VERSION 5.8 ;
BUSBITCHARS "[]" ;
DIVIDERCHAR "/" ;
UNITS
    DATABASE MICRONS 1000 ;
END UNITS

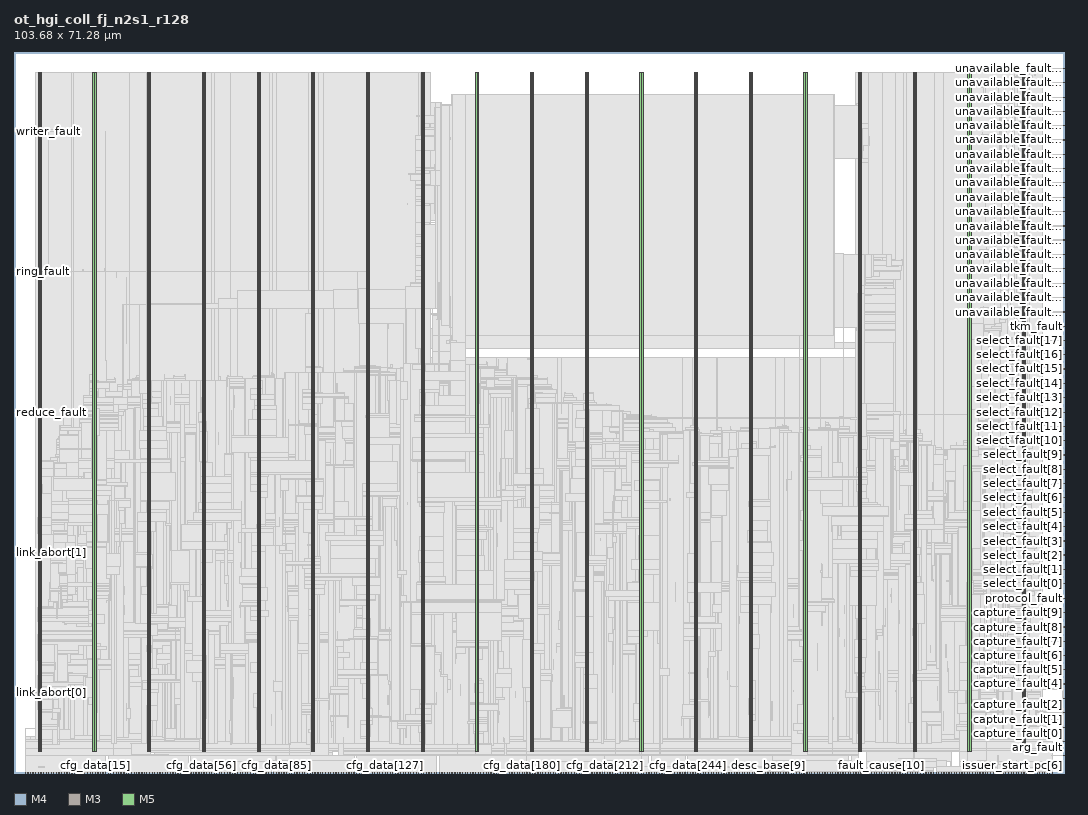
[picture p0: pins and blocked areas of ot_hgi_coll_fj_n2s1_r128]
MACRO ot_hgi_coll_fj_n2s1_r128
  FOREIGN ot_hgi_coll_fj_n2s1_r128 0 0 ;
  CLASS BLOCK ;
  SIZE 103.68 BY 71.28 ;
  PIN arg_fault
    DIRECTION INPUT ;
    USE SIGNAL ;
    PORT
      LAYER M4 ;
        RECT  103.596 1.68 103.68 1.704 ;
    END
  END arg_fault
  PIN capture_fault[0]
    DIRECTION INPUT ;
    USE SIGNAL ;
    PORT
      LAYER M4 ;
        RECT  103.596 3.12 103.68 3.144 ;
    END
  END capture_fault[0]
  PIN capture_fault[1]
    DIRECTION INPUT ;
    USE SIGNAL ;
    PORT
      LAYER M4 ;
        RECT  103.596 4.512 103.68 4.536 ;
    END
  END capture_fault[1]
  PIN capture_fault[2]
    DIRECTION INPUT ;
    USE SIGNAL ;
    PORT
      LAYER M4 ;
        RECT  103.596 5.952 103.68 5.976 ;
    END
  END capture_fault[2]
  PIN capture_fault[3]
    DIRECTION INPUT ;
    USE SIGNAL ;
    PORT
      LAYER M4 ;
        RECT  103.596 7.344 103.68 7.368 ;
    END
  END capture_fault[3]
  PIN capture_fault[4]
    DIRECTION INPUT ;
    USE SIGNAL ;
    PORT
      LAYER M4 ;
        RECT  103.596 8.784 103.68 8.808 ;
    END
  END capture_fault[4]
  PIN capture_fault[5]
    DIRECTION INPUT ;
    USE SIGNAL ;
    PORT
      LAYER M4 ;
        RECT  103.596 10.176 103.68 10.2 ;
    END
  END capture_fault[5]
  PIN capture_fault[6]
    DIRECTION INPUT ;
    USE SIGNAL ;
    PORT
      LAYER M4 ;
        RECT  103.596 11.616 103.68 11.64 ;
    END
  END capture_fault[6]
  PIN capture_fault[7]
    DIRECTION INPUT ;
    USE SIGNAL ;
    PORT
      LAYER M4 ;
        RECT  103.596 13.008 103.68 13.032 ;
    END
  END capture_fault[7]
  PIN capture_fault[8]
    DIRECTION INPUT ;
    USE SIGNAL ;
    PORT
      LAYER M4 ;
        RECT  103.596 14.4 103.68 14.424 ;
    END
  END capture_fault[8]
  PIN capture_fault[9]
    DIRECTION INPUT ;
    USE SIGNAL ;
    PORT
      LAYER M4 ;
        RECT  103.596 15.84 103.68 15.864 ;
    END
  END capture_fault[9]
  PIN cfg_addr[0]
    DIRECTION INPUT ;
    USE SIGNAL ;
    PORT
      LAYER M3 ;
        RECT  1.116 0 1.134 0.038 ;
    END
  END cfg_addr[0]
  PIN cfg_addr[10]
    DIRECTION INPUT ;
    USE SIGNAL ;
    PORT
      LAYER M3 ;
        RECT  3.672 0 3.69 0.038 ;
    END
  END cfg_addr[10]
  PIN cfg_addr[11]
    DIRECTION INPUT ;
    USE SIGNAL ;
    PORT
      LAYER M3 ;
        RECT  3.924 0 3.942 0.038 ;
    END
  END cfg_addr[11]
  PIN cfg_addr[1]
    DIRECTION INPUT ;
    USE SIGNAL ;
    PORT
      LAYER M3 ;
        RECT  1.368 0 1.386 0.038 ;
    END
  END cfg_addr[1]
  PIN cfg_addr[2]
    DIRECTION INPUT ;
    USE SIGNAL ;
    PORT
      LAYER M3 ;
        RECT  1.62 0 1.638 0.038 ;
    END
  END cfg_addr[2]
  PIN cfg_addr[3]
    DIRECTION INPUT ;
    USE SIGNAL ;
    PORT
      LAYER M3 ;
        RECT  1.872 0 1.89 0.038 ;
    END
  END cfg_addr[3]
  PIN cfg_addr[4]
    DIRECTION INPUT ;
    USE SIGNAL ;
    PORT
      LAYER M3 ;
        RECT  2.124 0 2.142 0.038 ;
    END
  END cfg_addr[4]
  PIN cfg_addr[5]
    DIRECTION INPUT ;
    USE SIGNAL ;
    PORT
      LAYER M3 ;
        RECT  2.412 0 2.43 0.038 ;
    END
  END cfg_addr[5]
  PIN cfg_addr[6]
    DIRECTION INPUT ;
    USE SIGNAL ;
    PORT
      LAYER M3 ;
        RECT  2.664 0 2.682 0.038 ;
    END
  END cfg_addr[6]
  PIN cfg_addr[7]
    DIRECTION INPUT ;
    USE SIGNAL ;
    PORT
      LAYER M3 ;
        RECT  2.916 0 2.934 0.038 ;
    END
  END cfg_addr[7]
  PIN cfg_addr[8]
    DIRECTION INPUT ;
    USE SIGNAL ;
    PORT
      LAYER M3 ;
        RECT  3.168 0 3.186 0.038 ;
    END
  END cfg_addr[8]
  PIN cfg_addr[9]
    DIRECTION INPUT ;
    USE SIGNAL ;
    PORT
      LAYER M3 ;
        RECT  3.42 0 3.438 0.038 ;
    END
  END cfg_addr[9]
  PIN cfg_data[0]
    DIRECTION INPUT ;
    USE SIGNAL ;
    PORT
      LAYER M3 ;
        RECT  4.176 0 4.194 0.038 ;
    END
  END cfg_data[0]
  PIN cfg_data[100]
    DIRECTION INPUT ;
    USE SIGNAL ;
    PORT
      LAYER M5 ;
        RECT  29.712 0 29.736 0.084 ;
    END
  END cfg_data[100]
  PIN cfg_data[101]
    DIRECTION INPUT ;
    USE SIGNAL ;
    PORT
      LAYER M5 ;
        RECT  30 0 30.024 0.084 ;
    END
  END cfg_data[101]
  PIN cfg_data[102]
    DIRECTION INPUT ;
    USE SIGNAL ;
    PORT
      LAYER M5 ;
        RECT  30.24 0 30.264 0.084 ;
    END
  END cfg_data[102]
  PIN cfg_data[103]
    DIRECTION INPUT ;
    USE SIGNAL ;
    PORT
      LAYER M5 ;
        RECT  30.48 0 30.504 0.084 ;
    END
  END cfg_data[103]
  PIN cfg_data[104]
    DIRECTION INPUT ;
    USE SIGNAL ;
    PORT
      LAYER M5 ;
        RECT  30.768 0 30.792 0.084 ;
    END
  END cfg_data[104]
  PIN cfg_data[105]
    DIRECTION INPUT ;
    USE SIGNAL ;
    PORT
      LAYER M5 ;
        RECT  31.008 0 31.032 0.084 ;
    END
  END cfg_data[105]
  PIN cfg_data[106]
    DIRECTION INPUT ;
    USE SIGNAL ;
    PORT
      LAYER M5 ;
        RECT  31.248 0 31.272 0.084 ;
    END
  END cfg_data[106]
  PIN cfg_data[107]
    DIRECTION INPUT ;
    USE SIGNAL ;
    PORT
      LAYER M5 ;
        RECT  31.536 0 31.56 0.084 ;
    END
  END cfg_data[107]
  PIN cfg_data[108]
    DIRECTION INPUT ;
    USE SIGNAL ;
    PORT
      LAYER M5 ;
        RECT  31.776 0 31.8 0.084 ;
    END
  END cfg_data[108]
  PIN cfg_data[109]
    DIRECTION INPUT ;
    USE SIGNAL ;
    PORT
      LAYER M5 ;
        RECT  32.016 0 32.04 0.084 ;
    END
  END cfg_data[109]
  PIN cfg_data[10]
    DIRECTION INPUT ;
    USE SIGNAL ;
    PORT
      LAYER M3 ;
        RECT  6.732 0 6.75 0.038 ;
    END
  END cfg_data[10]
  PIN cfg_data[110]
    DIRECTION INPUT ;
    USE SIGNAL ;
    PORT
      LAYER M5 ;
        RECT  32.304 0 32.328 0.084 ;
    END
  END cfg_data[110]
  PIN cfg_data[111]
    DIRECTION INPUT ;
    USE SIGNAL ;
    PORT
      LAYER M5 ;
        RECT  32.544 0 32.568 0.084 ;
    END
  END cfg_data[111]
  PIN cfg_data[112]
    DIRECTION INPUT ;
    USE SIGNAL ;
    PORT
      LAYER M5 ;
        RECT  32.784 0 32.808 0.084 ;
    END
  END cfg_data[112]
  PIN cfg_data[113]
    DIRECTION INPUT ;
    USE SIGNAL ;
    PORT
      LAYER M5 ;
        RECT  33.072 0 33.096 0.084 ;
    END
  END cfg_data[113]
  PIN cfg_data[114]
    DIRECTION INPUT ;
    USE SIGNAL ;
    PORT
      LAYER M5 ;
        RECT  33.312 0 33.336 0.084 ;
    END
  END cfg_data[114]
  PIN cfg_data[115]
    DIRECTION INPUT ;
    USE SIGNAL ;
    PORT
      LAYER M5 ;
        RECT  33.552 0 33.576 0.084 ;
    END
  END cfg_data[115]
  PIN cfg_data[116]
    DIRECTION INPUT ;
    USE SIGNAL ;
    PORT
      LAYER M3 ;
        RECT  33.804 0 33.822 0.038 ;
    END
  END cfg_data[116]
  PIN cfg_data[117]
    DIRECTION INPUT ;
    USE SIGNAL ;
    PORT
      LAYER M3 ;
        RECT  34.092 0 34.11 0.038 ;
    END
  END cfg_data[117]
  PIN cfg_data[118]
    DIRECTION INPUT ;
    USE SIGNAL ;
    PORT
      LAYER M3 ;
        RECT  34.344 0 34.362 0.038 ;
    END
  END cfg_data[118]
  PIN cfg_data[119]
    DIRECTION INPUT ;
    USE SIGNAL ;
    PORT
      LAYER M3 ;
        RECT  34.596 0 34.614 0.038 ;
    END
  END cfg_data[119]
  PIN cfg_data[11]
    DIRECTION INPUT ;
    USE SIGNAL ;
    PORT
      LAYER M3 ;
        RECT  6.984 0 7.002 0.038 ;
    END
  END cfg_data[11]
  PIN cfg_data[120]
    DIRECTION INPUT ;
    USE SIGNAL ;
    PORT
      LAYER M3 ;
        RECT  34.848 0 34.866 0.038 ;
    END
  END cfg_data[120]
  PIN cfg_data[121]
    DIRECTION INPUT ;
    USE SIGNAL ;
    PORT
      LAYER M3 ;
        RECT  35.1 0 35.118 0.038 ;
    END
  END cfg_data[121]
  PIN cfg_data[122]
    DIRECTION INPUT ;
    USE SIGNAL ;
    PORT
      LAYER M3 ;
        RECT  35.352 0 35.37 0.038 ;
    END
  END cfg_data[122]
  PIN cfg_data[123]
    DIRECTION INPUT ;
    USE SIGNAL ;
    PORT
      LAYER M3 ;
        RECT  35.604 0 35.622 0.038 ;
    END
  END cfg_data[123]
  PIN cfg_data[124]
    DIRECTION INPUT ;
    USE SIGNAL ;
    PORT
      LAYER M3 ;
        RECT  35.856 0 35.874 0.038 ;
    END
  END cfg_data[124]
  PIN cfg_data[125]
    DIRECTION INPUT ;
    USE SIGNAL ;
    PORT
      LAYER M3 ;
        RECT  36.108 0 36.126 0.038 ;
    END
  END cfg_data[125]
  PIN cfg_data[126]
    DIRECTION INPUT ;
    USE SIGNAL ;
    PORT
      LAYER M3 ;
        RECT  36.36 0 36.378 0.038 ;
    END
  END cfg_data[126]
  PIN cfg_data[127]
    DIRECTION INPUT ;
    USE SIGNAL ;
    PORT
      LAYER M3 ;
        RECT  36.648 0 36.666 0.038 ;
    END
  END cfg_data[127]
  PIN cfg_data[128]
    DIRECTION INPUT ;
    USE SIGNAL ;
    PORT
      LAYER M3 ;
        RECT  36.9 0 36.918 0.038 ;
    END
  END cfg_data[128]
  PIN cfg_data[129]
    DIRECTION INPUT ;
    USE SIGNAL ;
    PORT
      LAYER M3 ;
        RECT  37.152 0 37.17 0.038 ;
    END
  END cfg_data[129]
  PIN cfg_data[12]
    DIRECTION INPUT ;
    USE SIGNAL ;
    PORT
      LAYER M3 ;
        RECT  7.236 0 7.254 0.038 ;
    END
  END cfg_data[12]
  PIN cfg_data[130]
    DIRECTION INPUT ;
    USE SIGNAL ;
    PORT
      LAYER M3 ;
        RECT  37.404 0 37.422 0.038 ;
    END
  END cfg_data[130]
  PIN cfg_data[131]
    DIRECTION INPUT ;
    USE SIGNAL ;
    PORT
      LAYER M3 ;
        RECT  37.656 0 37.674 0.038 ;
    END
  END cfg_data[131]
  PIN cfg_data[132]
    DIRECTION INPUT ;
    USE SIGNAL ;
    PORT
      LAYER M3 ;
        RECT  37.908 0 37.926 0.038 ;
    END
  END cfg_data[132]
  PIN cfg_data[133]
    DIRECTION INPUT ;
    USE SIGNAL ;
    PORT
      LAYER M3 ;
        RECT  38.16 0 38.178 0.038 ;
    END
  END cfg_data[133]
  PIN cfg_data[134]
    DIRECTION INPUT ;
    USE SIGNAL ;
    PORT
      LAYER M3 ;
        RECT  38.412 0 38.43 0.038 ;
    END
  END cfg_data[134]
  PIN cfg_data[135]
    DIRECTION INPUT ;
    USE SIGNAL ;
    PORT
      LAYER M3 ;
        RECT  38.664 0 38.682 0.038 ;
    END
  END cfg_data[135]
  PIN cfg_data[136]
    DIRECTION INPUT ;
    USE SIGNAL ;
    PORT
      LAYER M3 ;
        RECT  38.916 0 38.934 0.038 ;
    END
  END cfg_data[136]
  PIN cfg_data[137]
    DIRECTION INPUT ;
    USE SIGNAL ;
    PORT
      LAYER M3 ;
        RECT  39.168 0 39.186 0.038 ;
    END
  END cfg_data[137]
  PIN cfg_data[138]
    DIRECTION INPUT ;
    USE SIGNAL ;
    PORT
      LAYER M3 ;
        RECT  39.456 0 39.474 0.038 ;
    END
  END cfg_data[138]
  PIN cfg_data[139]
    DIRECTION INPUT ;
    USE SIGNAL ;
    PORT
      LAYER M3 ;
        RECT  39.708 0 39.726 0.038 ;
    END
  END cfg_data[139]
  PIN cfg_data[13]
    DIRECTION INPUT ;
    USE SIGNAL ;
    PORT
      LAYER M3 ;
        RECT  7.524 0 7.542 0.038 ;
    END
  END cfg_data[13]
  PIN cfg_data[140]
    DIRECTION INPUT ;
    USE SIGNAL ;
    PORT
      LAYER M3 ;
        RECT  39.96 0 39.978 0.038 ;
    END
  END cfg_data[140]
  PIN cfg_data[141]
    DIRECTION INPUT ;
    USE SIGNAL ;
    PORT
      LAYER M3 ;
        RECT  40.212 0 40.23 0.038 ;
    END
  END cfg_data[141]
  PIN cfg_data[142]
    DIRECTION INPUT ;
    USE SIGNAL ;
    PORT
      LAYER M3 ;
        RECT  40.464 0 40.482 0.038 ;
    END
  END cfg_data[142]
  PIN cfg_data[143]
    DIRECTION INPUT ;
    USE SIGNAL ;
    PORT
      LAYER M3 ;
        RECT  40.716 0 40.734 0.038 ;
    END
  END cfg_data[143]
  PIN cfg_data[144]
    DIRECTION INPUT ;
    USE SIGNAL ;
    PORT
      LAYER M3 ;
        RECT  40.968 0 40.986 0.038 ;
    END
  END cfg_data[144]
  PIN cfg_data[145]
    DIRECTION INPUT ;
    USE SIGNAL ;
    PORT
      LAYER M3 ;
        RECT  41.22 0 41.238 0.038 ;
    END
  END cfg_data[145]
  PIN cfg_data[146]
    DIRECTION INPUT ;
    USE SIGNAL ;
    PORT
      LAYER M3 ;
        RECT  41.472 0 41.49 0.038 ;
    END
  END cfg_data[146]
  PIN cfg_data[147]
    DIRECTION INPUT ;
    USE SIGNAL ;
    PORT
      LAYER M3 ;
        RECT  41.724 0 41.742 0.038 ;
    END
  END cfg_data[147]
  PIN cfg_data[148]
    DIRECTION INPUT ;
    USE SIGNAL ;
    PORT
      LAYER M5 ;
        RECT  42 0 42.024 0.084 ;
    END
  END cfg_data[148]
  PIN cfg_data[149]
    DIRECTION INPUT ;
    USE SIGNAL ;
    PORT
      LAYER M5 ;
        RECT  42.24 0 42.264 0.084 ;
    END
  END cfg_data[149]
  PIN cfg_data[14]
    DIRECTION INPUT ;
    USE SIGNAL ;
    PORT
      LAYER M3 ;
        RECT  7.776 0 7.794 0.038 ;
    END
  END cfg_data[14]
  PIN cfg_data[150]
    DIRECTION INPUT ;
    USE SIGNAL ;
    PORT
      LAYER M5 ;
        RECT  42.48 0 42.504 0.084 ;
    END
  END cfg_data[150]
  PIN cfg_data[151]
    DIRECTION INPUT ;
    USE SIGNAL ;
    PORT
      LAYER M5 ;
        RECT  42.768 0 42.792 0.084 ;
    END
  END cfg_data[151]
  PIN cfg_data[152]
    DIRECTION INPUT ;
    USE SIGNAL ;
    PORT
      LAYER M5 ;
        RECT  43.008 0 43.032 0.084 ;
    END
  END cfg_data[152]
  PIN cfg_data[153]
    DIRECTION INPUT ;
    USE SIGNAL ;
    PORT
      LAYER M5 ;
        RECT  43.248 0 43.272 0.084 ;
    END
  END cfg_data[153]
  PIN cfg_data[154]
    DIRECTION INPUT ;
    USE SIGNAL ;
    PORT
      LAYER M5 ;
        RECT  43.536 0 43.56 0.084 ;
    END
  END cfg_data[154]
  PIN cfg_data[155]
    DIRECTION INPUT ;
    USE SIGNAL ;
    PORT
      LAYER M5 ;
        RECT  43.776 0 43.8 0.084 ;
    END
  END cfg_data[155]
  PIN cfg_data[156]
    DIRECTION INPUT ;
    USE SIGNAL ;
    PORT
      LAYER M5 ;
        RECT  44.016 0 44.04 0.084 ;
    END
  END cfg_data[156]
  PIN cfg_data[157]
    DIRECTION INPUT ;
    USE SIGNAL ;
    PORT
      LAYER M5 ;
        RECT  44.304 0 44.328 0.084 ;
    END
  END cfg_data[157]
  PIN cfg_data[158]
    DIRECTION INPUT ;
    USE SIGNAL ;
    PORT
      LAYER M5 ;
        RECT  44.544 0 44.568 0.084 ;
    END
  END cfg_data[158]
  PIN cfg_data[159]
    DIRECTION INPUT ;
    USE SIGNAL ;
    PORT
      LAYER M5 ;
        RECT  44.784 0 44.808 0.084 ;
    END
  END cfg_data[159]
  PIN cfg_data[15]
    DIRECTION INPUT ;
    USE SIGNAL ;
    PORT
      LAYER M3 ;
        RECT  8.028 0 8.046 0.038 ;
    END
  END cfg_data[15]
  PIN cfg_data[160]
    DIRECTION INPUT ;
    USE SIGNAL ;
    PORT
      LAYER M5 ;
        RECT  45.072 0 45.096 0.084 ;
    END
  END cfg_data[160]
  PIN cfg_data[161]
    DIRECTION INPUT ;
    USE SIGNAL ;
    PORT
      LAYER M5 ;
        RECT  45.312 0 45.336 0.084 ;
    END
  END cfg_data[161]
  PIN cfg_data[162]
    DIRECTION INPUT ;
    USE SIGNAL ;
    PORT
      LAYER M5 ;
        RECT  45.552 0 45.576 0.084 ;
    END
  END cfg_data[162]
  PIN cfg_data[163]
    DIRECTION INPUT ;
    USE SIGNAL ;
    PORT
      LAYER M5 ;
        RECT  45.84 0 45.864 0.084 ;
    END
  END cfg_data[163]
  PIN cfg_data[164]
    DIRECTION INPUT ;
    USE SIGNAL ;
    PORT
      LAYER M5 ;
        RECT  46.08 0 46.104 0.084 ;
    END
  END cfg_data[164]
  PIN cfg_data[165]
    DIRECTION INPUT ;
    USE SIGNAL ;
    PORT
      LAYER M5 ;
        RECT  46.32 0 46.344 0.084 ;
    END
  END cfg_data[165]
  PIN cfg_data[166]
    DIRECTION INPUT ;
    USE SIGNAL ;
    PORT
      LAYER M5 ;
        RECT  46.608 0 46.632 0.084 ;
    END
  END cfg_data[166]
  PIN cfg_data[167]
    DIRECTION INPUT ;
    USE SIGNAL ;
    PORT
      LAYER M5 ;
        RECT  46.848 0 46.872 0.084 ;
    END
  END cfg_data[167]
  PIN cfg_data[168]
    DIRECTION INPUT ;
    USE SIGNAL ;
    PORT
      LAYER M5 ;
        RECT  47.088 0 47.112 0.084 ;
    END
  END cfg_data[168]
  PIN cfg_data[169]
    DIRECTION INPUT ;
    USE SIGNAL ;
    PORT
      LAYER M5 ;
        RECT  47.376 0 47.4 0.084 ;
    END
  END cfg_data[169]
  PIN cfg_data[16]
    DIRECTION INPUT ;
    USE SIGNAL ;
    PORT
      LAYER M3 ;
        RECT  8.28 0 8.298 0.038 ;
    END
  END cfg_data[16]
  PIN cfg_data[170]
    DIRECTION INPUT ;
    USE SIGNAL ;
    PORT
      LAYER M5 ;
        RECT  47.616 0 47.64 0.084 ;
    END
  END cfg_data[170]
  PIN cfg_data[171]
    DIRECTION INPUT ;
    USE SIGNAL ;
    PORT
      LAYER M5 ;
        RECT  47.856 0 47.88 0.084 ;
    END
  END cfg_data[171]
  PIN cfg_data[172]
    DIRECTION INPUT ;
    USE SIGNAL ;
    PORT
      LAYER M5 ;
        RECT  48.144 0 48.168 0.084 ;
    END
  END cfg_data[172]
  PIN cfg_data[173]
    DIRECTION INPUT ;
    USE SIGNAL ;
    PORT
      LAYER M5 ;
        RECT  48.384 0 48.408 0.084 ;
    END
  END cfg_data[173]
  PIN cfg_data[174]
    DIRECTION INPUT ;
    USE SIGNAL ;
    PORT
      LAYER M5 ;
        RECT  48.624 0 48.648 0.084 ;
    END
  END cfg_data[174]
  PIN cfg_data[175]
    DIRECTION INPUT ;
    USE SIGNAL ;
    PORT
      LAYER M5 ;
        RECT  48.912 0 48.936 0.084 ;
    END
  END cfg_data[175]
  PIN cfg_data[176]
    DIRECTION INPUT ;
    USE SIGNAL ;
    PORT
      LAYER M5 ;
        RECT  49.152 0 49.176 0.084 ;
    END
  END cfg_data[176]
  PIN cfg_data[177]
    DIRECTION INPUT ;
    USE SIGNAL ;
    PORT
      LAYER M5 ;
        RECT  49.392 0 49.416 0.084 ;
    END
  END cfg_data[177]
  PIN cfg_data[178]
    DIRECTION INPUT ;
    USE SIGNAL ;
    PORT
      LAYER M5 ;
        RECT  49.68 0 49.704 0.084 ;
    END
  END cfg_data[178]
  PIN cfg_data[179]
    DIRECTION INPUT ;
    USE SIGNAL ;
    PORT
      LAYER M5 ;
        RECT  49.92 0 49.944 0.084 ;
    END
  END cfg_data[179]
  PIN cfg_data[17]
    DIRECTION INPUT ;
    USE SIGNAL ;
    PORT
      LAYER M3 ;
        RECT  8.532 0 8.55 0.038 ;
    END
  END cfg_data[17]
  PIN cfg_data[180]
    DIRECTION INPUT ;
    USE SIGNAL ;
    PORT
      LAYER M3 ;
        RECT  50.184 0 50.202 0.038 ;
    END
  END cfg_data[180]
  PIN cfg_data[181]
    DIRECTION INPUT ;
    USE SIGNAL ;
    PORT
      LAYER M3 ;
        RECT  50.436 0 50.454 0.038 ;
    END
  END cfg_data[181]
  PIN cfg_data[182]
    DIRECTION INPUT ;
    USE SIGNAL ;
    PORT
      LAYER M3 ;
        RECT  50.688 0 50.706 0.038 ;
    END
  END cfg_data[182]
  PIN cfg_data[183]
    DIRECTION INPUT ;
    USE SIGNAL ;
    PORT
      LAYER M3 ;
        RECT  50.94 0 50.958 0.038 ;
    END
  END cfg_data[183]
  PIN cfg_data[184]
    DIRECTION INPUT ;
    USE SIGNAL ;
    PORT
      LAYER M3 ;
        RECT  51.192 0 51.21 0.038 ;
    END
  END cfg_data[184]
  PIN cfg_data[185]
    DIRECTION INPUT ;
    USE SIGNAL ;
    PORT
      LAYER M3 ;
        RECT  51.444 0 51.462 0.038 ;
    END
  END cfg_data[185]
  PIN cfg_data[186]
    DIRECTION INPUT ;
    USE SIGNAL ;
    PORT
      LAYER M3 ;
        RECT  51.696 0 51.714 0.038 ;
    END
  END cfg_data[186]
  PIN cfg_data[187]
    DIRECTION INPUT ;
    USE SIGNAL ;
    PORT
      LAYER M3 ;
        RECT  51.948 0 51.966 0.038 ;
    END
  END cfg_data[187]
  PIN cfg_data[188]
    DIRECTION INPUT ;
    USE SIGNAL ;
    PORT
      LAYER M3 ;
        RECT  52.2 0 52.218 0.038 ;
    END
  END cfg_data[188]
  PIN cfg_data[189]
    DIRECTION INPUT ;
    USE SIGNAL ;
    PORT
      LAYER M3 ;
        RECT  52.488 0 52.506 0.038 ;
    END
  END cfg_data[189]
  PIN cfg_data[18]
    DIRECTION INPUT ;
    USE SIGNAL ;
    PORT
      LAYER M3 ;
        RECT  8.784 0 8.802 0.038 ;
    END
  END cfg_data[18]
  PIN cfg_data[190]
    DIRECTION INPUT ;
    USE SIGNAL ;
    PORT
      LAYER M3 ;
        RECT  52.74 0 52.758 0.038 ;
    END
  END cfg_data[190]
  PIN cfg_data[191]
    DIRECTION INPUT ;
    USE SIGNAL ;
    PORT
      LAYER M3 ;
        RECT  52.992 0 53.01 0.038 ;
    END
  END cfg_data[191]
  PIN cfg_data[192]
    DIRECTION INPUT ;
    USE SIGNAL ;
    PORT
      LAYER M3 ;
        RECT  53.244 0 53.262 0.038 ;
    END
  END cfg_data[192]
  PIN cfg_data[193]
    DIRECTION INPUT ;
    USE SIGNAL ;
    PORT
      LAYER M3 ;
        RECT  53.496 0 53.514 0.038 ;
    END
  END cfg_data[193]
  PIN cfg_data[194]
    DIRECTION INPUT ;
    USE SIGNAL ;
    PORT
      LAYER M3 ;
        RECT  53.748 0 53.766 0.038 ;
    END
  END cfg_data[194]
  PIN cfg_data[195]
    DIRECTION INPUT ;
    USE SIGNAL ;
    PORT
      LAYER M3 ;
        RECT  54 0 54.018 0.038 ;
    END
  END cfg_data[195]
  PIN cfg_data[196]
    DIRECTION INPUT ;
    USE SIGNAL ;
    PORT
      LAYER M3 ;
        RECT  54.252 0 54.27 0.038 ;
    END
  END cfg_data[196]
  PIN cfg_data[197]
    DIRECTION INPUT ;
    USE SIGNAL ;
    PORT
      LAYER M3 ;
        RECT  54.504 0 54.522 0.038 ;
    END
  END cfg_data[197]
  PIN cfg_data[198]
    DIRECTION INPUT ;
    USE SIGNAL ;
    PORT
      LAYER M3 ;
        RECT  54.756 0 54.774 0.038 ;
    END
  END cfg_data[198]
  PIN cfg_data[199]
    DIRECTION INPUT ;
    USE SIGNAL ;
    PORT
      LAYER M3 ;
        RECT  55.008 0 55.026 0.038 ;
    END
  END cfg_data[199]
  PIN cfg_data[19]
    DIRECTION INPUT ;
    USE SIGNAL ;
    PORT
      LAYER M3 ;
        RECT  9.036 0 9.054 0.038 ;
    END
  END cfg_data[19]
  PIN cfg_data[1]
    DIRECTION INPUT ;
    USE SIGNAL ;
    PORT
      LAYER M3 ;
        RECT  4.428 0 4.446 0.038 ;
    END
  END cfg_data[1]
  PIN cfg_data[200]
    DIRECTION INPUT ;
    USE SIGNAL ;
    PORT
      LAYER M3 ;
        RECT  55.296 0 55.314 0.038 ;
    END
  END cfg_data[200]
  PIN cfg_data[201]
    DIRECTION INPUT ;
    USE SIGNAL ;
    PORT
      LAYER M3 ;
        RECT  55.548 0 55.566 0.038 ;
    END
  END cfg_data[201]
  PIN cfg_data[202]
    DIRECTION INPUT ;
    USE SIGNAL ;
    PORT
      LAYER M3 ;
        RECT  55.8 0 55.818 0.038 ;
    END
  END cfg_data[202]
  PIN cfg_data[203]
    DIRECTION INPUT ;
    USE SIGNAL ;
    PORT
      LAYER M3 ;
        RECT  56.052 0 56.07 0.038 ;
    END
  END cfg_data[203]
  PIN cfg_data[204]
    DIRECTION INPUT ;
    USE SIGNAL ;
    PORT
      LAYER M3 ;
        RECT  56.304 0 56.322 0.038 ;
    END
  END cfg_data[204]
  PIN cfg_data[205]
    DIRECTION INPUT ;
    USE SIGNAL ;
    PORT
      LAYER M3 ;
        RECT  56.556 0 56.574 0.038 ;
    END
  END cfg_data[205]
  PIN cfg_data[206]
    DIRECTION INPUT ;
    USE SIGNAL ;
    PORT
      LAYER M3 ;
        RECT  56.808 0 56.826 0.038 ;
    END
  END cfg_data[206]
  PIN cfg_data[207]
    DIRECTION INPUT ;
    USE SIGNAL ;
    PORT
      LAYER M3 ;
        RECT  57.06 0 57.078 0.038 ;
    END
  END cfg_data[207]
  PIN cfg_data[208]
    DIRECTION INPUT ;
    USE SIGNAL ;
    PORT
      LAYER M3 ;
        RECT  57.312 0 57.33 0.038 ;
    END
  END cfg_data[208]
  PIN cfg_data[209]
    DIRECTION INPUT ;
    USE SIGNAL ;
    PORT
      LAYER M3 ;
        RECT  57.564 0 57.582 0.038 ;
    END
  END cfg_data[209]
  PIN cfg_data[20]
    DIRECTION INPUT ;
    USE SIGNAL ;
    PORT
      LAYER M5 ;
        RECT  9.312 0 9.336 0.084 ;
    END
  END cfg_data[20]
  PIN cfg_data[210]
    DIRECTION INPUT ;
    USE SIGNAL ;
    PORT
      LAYER M3 ;
        RECT  57.852 0 57.87 0.038 ;
    END
  END cfg_data[210]
  PIN cfg_data[211]
    DIRECTION INPUT ;
    USE SIGNAL ;
    PORT
      LAYER M3 ;
        RECT  58.104 0 58.122 0.038 ;
    END
  END cfg_data[211]
  PIN cfg_data[212]
    DIRECTION INPUT ;
    USE SIGNAL ;
    PORT
      LAYER M5 ;
        RECT  58.32 0 58.344 0.084 ;
    END
  END cfg_data[212]
  PIN cfg_data[213]
    DIRECTION INPUT ;
    USE SIGNAL ;
    PORT
      LAYER M5 ;
        RECT  58.608 0 58.632 0.084 ;
    END
  END cfg_data[213]
  PIN cfg_data[214]
    DIRECTION INPUT ;
    USE SIGNAL ;
    PORT
      LAYER M5 ;
        RECT  58.848 0 58.872 0.084 ;
    END
  END cfg_data[214]
  PIN cfg_data[215]
    DIRECTION INPUT ;
    USE SIGNAL ;
    PORT
      LAYER M5 ;
        RECT  59.088 0 59.112 0.084 ;
    END
  END cfg_data[215]
  PIN cfg_data[216]
    DIRECTION INPUT ;
    USE SIGNAL ;
    PORT
      LAYER M5 ;
        RECT  59.376 0 59.4 0.084 ;
    END
  END cfg_data[216]
  PIN cfg_data[217]
    DIRECTION INPUT ;
    USE SIGNAL ;
    PORT
      LAYER M5 ;
        RECT  59.616 0 59.64 0.084 ;
    END
  END cfg_data[217]
  PIN cfg_data[218]
    DIRECTION INPUT ;
    USE SIGNAL ;
    PORT
      LAYER M5 ;
        RECT  59.856 0 59.88 0.084 ;
    END
  END cfg_data[218]
  PIN cfg_data[219]
    DIRECTION INPUT ;
    USE SIGNAL ;
    PORT
      LAYER M5 ;
        RECT  60.144 0 60.168 0.084 ;
    END
  END cfg_data[219]
  PIN cfg_data[21]
    DIRECTION INPUT ;
    USE SIGNAL ;
    PORT
      LAYER M5 ;
        RECT  9.552 0 9.576 0.084 ;
    END
  END cfg_data[21]
  PIN cfg_data[220]
    DIRECTION INPUT ;
    USE SIGNAL ;
    PORT
      LAYER M5 ;
        RECT  60.384 0 60.408 0.084 ;
    END
  END cfg_data[220]
  PIN cfg_data[221]
    DIRECTION INPUT ;
    USE SIGNAL ;
    PORT
      LAYER M5 ;
        RECT  60.624 0 60.648 0.084 ;
    END
  END cfg_data[221]
  PIN cfg_data[222]
    DIRECTION INPUT ;
    USE SIGNAL ;
    PORT
      LAYER M5 ;
        RECT  60.912 0 60.936 0.084 ;
    END
  END cfg_data[222]
  PIN cfg_data[223]
    DIRECTION INPUT ;
    USE SIGNAL ;
    PORT
      LAYER M5 ;
        RECT  61.152 0 61.176 0.084 ;
    END
  END cfg_data[223]
  PIN cfg_data[224]
    DIRECTION INPUT ;
    USE SIGNAL ;
    PORT
      LAYER M5 ;
        RECT  61.392 0 61.416 0.084 ;
    END
  END cfg_data[224]
  PIN cfg_data[225]
    DIRECTION INPUT ;
    USE SIGNAL ;
    PORT
      LAYER M5 ;
        RECT  61.68 0 61.704 0.084 ;
    END
  END cfg_data[225]
  PIN cfg_data[226]
    DIRECTION INPUT ;
    USE SIGNAL ;
    PORT
      LAYER M5 ;
        RECT  61.92 0 61.944 0.084 ;
    END
  END cfg_data[226]
  PIN cfg_data[227]
    DIRECTION INPUT ;
    USE SIGNAL ;
    PORT
      LAYER M5 ;
        RECT  62.16 0 62.184 0.084 ;
    END
  END cfg_data[227]
  PIN cfg_data[228]
    DIRECTION INPUT ;
    USE SIGNAL ;
    PORT
      LAYER M5 ;
        RECT  62.448 0 62.472 0.084 ;
    END
  END cfg_data[228]
  PIN cfg_data[229]
    DIRECTION INPUT ;
    USE SIGNAL ;
    PORT
      LAYER M5 ;
        RECT  62.688 0 62.712 0.084 ;
    END
  END cfg_data[229]
  PIN cfg_data[22]
    DIRECTION INPUT ;
    USE SIGNAL ;
    PORT
      LAYER M5 ;
        RECT  9.792 0 9.816 0.084 ;
    END
  END cfg_data[22]
  PIN cfg_data[230]
    DIRECTION INPUT ;
    USE SIGNAL ;
    PORT
      LAYER M5 ;
        RECT  62.928 0 62.952 0.084 ;
    END
  END cfg_data[230]
  PIN cfg_data[231]
    DIRECTION INPUT ;
    USE SIGNAL ;
    PORT
      LAYER M5 ;
        RECT  63.216 0 63.24 0.084 ;
    END
  END cfg_data[231]
  PIN cfg_data[232]
    DIRECTION INPUT ;
    USE SIGNAL ;
    PORT
      LAYER M5 ;
        RECT  63.456 0 63.48 0.084 ;
    END
  END cfg_data[232]
  PIN cfg_data[233]
    DIRECTION INPUT ;
    USE SIGNAL ;
    PORT
      LAYER M5 ;
        RECT  63.696 0 63.72 0.084 ;
    END
  END cfg_data[233]
  PIN cfg_data[234]
    DIRECTION INPUT ;
    USE SIGNAL ;
    PORT
      LAYER M5 ;
        RECT  63.984 0 64.008 0.084 ;
    END
  END cfg_data[234]
  PIN cfg_data[235]
    DIRECTION INPUT ;
    USE SIGNAL ;
    PORT
      LAYER M5 ;
        RECT  64.224 0 64.248 0.084 ;
    END
  END cfg_data[235]
  PIN cfg_data[236]
    DIRECTION INPUT ;
    USE SIGNAL ;
    PORT
      LAYER M5 ;
        RECT  64.464 0 64.488 0.084 ;
    END
  END cfg_data[236]
  PIN cfg_data[237]
    DIRECTION INPUT ;
    USE SIGNAL ;
    PORT
      LAYER M5 ;
        RECT  64.752 0 64.776 0.084 ;
    END
  END cfg_data[237]
  PIN cfg_data[238]
    DIRECTION INPUT ;
    USE SIGNAL ;
    PORT
      LAYER M5 ;
        RECT  64.992 0 65.016 0.084 ;
    END
  END cfg_data[238]
  PIN cfg_data[239]
    DIRECTION INPUT ;
    USE SIGNAL ;
    PORT
      LAYER M5 ;
        RECT  65.232 0 65.256 0.084 ;
    END
  END cfg_data[239]
  PIN cfg_data[23]
    DIRECTION INPUT ;
    USE SIGNAL ;
    PORT
      LAYER M5 ;
        RECT  10.08 0 10.104 0.084 ;
    END
  END cfg_data[23]
  PIN cfg_data[240]
    DIRECTION INPUT ;
    USE SIGNAL ;
    PORT
      LAYER M5 ;
        RECT  65.52 0 65.544 0.084 ;
    END
  END cfg_data[240]
  PIN cfg_data[241]
    DIRECTION INPUT ;
    USE SIGNAL ;
    PORT
      LAYER M5 ;
        RECT  65.76 0 65.784 0.084 ;
    END
  END cfg_data[241]
  PIN cfg_data[242]
    DIRECTION INPUT ;
    USE SIGNAL ;
    PORT
      LAYER M5 ;
        RECT  66 0 66.024 0.084 ;
    END
  END cfg_data[242]
  PIN cfg_data[243]
    DIRECTION INPUT ;
    USE SIGNAL ;
    PORT
      LAYER M5 ;
        RECT  66.24 0 66.264 0.084 ;
    END
  END cfg_data[243]
  PIN cfg_data[244]
    DIRECTION INPUT ;
    USE SIGNAL ;
    PORT
      LAYER M3 ;
        RECT  66.528 0 66.546 0.038 ;
    END
  END cfg_data[244]
  PIN cfg_data[245]
    DIRECTION INPUT ;
    USE SIGNAL ;
    PORT
      LAYER M3 ;
        RECT  66.78 0 66.798 0.038 ;
    END
  END cfg_data[245]
  PIN cfg_data[246]
    DIRECTION INPUT ;
    USE SIGNAL ;
    PORT
      LAYER M3 ;
        RECT  67.032 0 67.05 0.038 ;
    END
  END cfg_data[246]
  PIN cfg_data[247]
    DIRECTION INPUT ;
    USE SIGNAL ;
    PORT
      LAYER M3 ;
        RECT  67.284 0 67.302 0.038 ;
    END
  END cfg_data[247]
  PIN cfg_data[248]
    DIRECTION INPUT ;
    USE SIGNAL ;
    PORT
      LAYER M3 ;
        RECT  67.536 0 67.554 0.038 ;
    END
  END cfg_data[248]
  PIN cfg_data[249]
    DIRECTION INPUT ;
    USE SIGNAL ;
    PORT
      LAYER M3 ;
        RECT  67.788 0 67.806 0.038 ;
    END
  END cfg_data[249]
  PIN cfg_data[24]
    DIRECTION INPUT ;
    USE SIGNAL ;
    PORT
      LAYER M5 ;
        RECT  10.32 0 10.344 0.084 ;
    END
  END cfg_data[24]
  PIN cfg_data[250]
    DIRECTION INPUT ;
    USE SIGNAL ;
    PORT
      LAYER M3 ;
        RECT  68.04 0 68.058 0.038 ;
    END
  END cfg_data[250]
  PIN cfg_data[251]
    DIRECTION INPUT ;
    USE SIGNAL ;
    PORT
      LAYER M3 ;
        RECT  68.292 0 68.31 0.038 ;
    END
  END cfg_data[251]
  PIN cfg_data[252]
    DIRECTION INPUT ;
    USE SIGNAL ;
    PORT
      LAYER M3 ;
        RECT  68.58 0 68.598 0.038 ;
    END
  END cfg_data[252]
  PIN cfg_data[253]
    DIRECTION INPUT ;
    USE SIGNAL ;
    PORT
      LAYER M3 ;
        RECT  68.832 0 68.85 0.038 ;
    END
  END cfg_data[253]
  PIN cfg_data[254]
    DIRECTION INPUT ;
    USE SIGNAL ;
    PORT
      LAYER M3 ;
        RECT  69.084 0 69.102 0.038 ;
    END
  END cfg_data[254]
  PIN cfg_data[255]
    DIRECTION INPUT ;
    USE SIGNAL ;
    PORT
      LAYER M3 ;
        RECT  69.336 0 69.354 0.038 ;
    END
  END cfg_data[255]
  PIN cfg_data[25]
    DIRECTION INPUT ;
    USE SIGNAL ;
    PORT
      LAYER M5 ;
        RECT  10.56 0 10.584 0.084 ;
    END
  END cfg_data[25]
  PIN cfg_data[26]
    DIRECTION INPUT ;
    USE SIGNAL ;
    PORT
      LAYER M5 ;
        RECT  10.848 0 10.872 0.084 ;
    END
  END cfg_data[26]
  PIN cfg_data[27]
    DIRECTION INPUT ;
    USE SIGNAL ;
    PORT
      LAYER M5 ;
        RECT  11.088 0 11.112 0.084 ;
    END
  END cfg_data[27]
  PIN cfg_data[28]
    DIRECTION INPUT ;
    USE SIGNAL ;
    PORT
      LAYER M5 ;
        RECT  11.328 0 11.352 0.084 ;
    END
  END cfg_data[28]
  PIN cfg_data[29]
    DIRECTION INPUT ;
    USE SIGNAL ;
    PORT
      LAYER M5 ;
        RECT  11.568 0 11.592 0.084 ;
    END
  END cfg_data[29]
  PIN cfg_data[2]
    DIRECTION INPUT ;
    USE SIGNAL ;
    PORT
      LAYER M3 ;
        RECT  4.68 0 4.698 0.038 ;
    END
  END cfg_data[2]
  PIN cfg_data[30]
    DIRECTION INPUT ;
    USE SIGNAL ;
    PORT
      LAYER M5 ;
        RECT  11.856 0 11.88 0.084 ;
    END
  END cfg_data[30]
  PIN cfg_data[31]
    DIRECTION INPUT ;
    USE SIGNAL ;
    PORT
      LAYER M5 ;
        RECT  12.096 0 12.12 0.084 ;
    END
  END cfg_data[31]
  PIN cfg_data[32]
    DIRECTION INPUT ;
    USE SIGNAL ;
    PORT
      LAYER M5 ;
        RECT  12.336 0 12.36 0.084 ;
    END
  END cfg_data[32]
  PIN cfg_data[33]
    DIRECTION INPUT ;
    USE SIGNAL ;
    PORT
      LAYER M5 ;
        RECT  12.624 0 12.648 0.084 ;
    END
  END cfg_data[33]
  PIN cfg_data[34]
    DIRECTION INPUT ;
    USE SIGNAL ;
    PORT
      LAYER M5 ;
        RECT  12.864 0 12.888 0.084 ;
    END
  END cfg_data[34]
  PIN cfg_data[35]
    DIRECTION INPUT ;
    USE SIGNAL ;
    PORT
      LAYER M5 ;
        RECT  13.104 0 13.128 0.084 ;
    END
  END cfg_data[35]
  PIN cfg_data[36]
    DIRECTION INPUT ;
    USE SIGNAL ;
    PORT
      LAYER M5 ;
        RECT  13.392 0 13.416 0.084 ;
    END
  END cfg_data[36]
  PIN cfg_data[37]
    DIRECTION INPUT ;
    USE SIGNAL ;
    PORT
      LAYER M5 ;
        RECT  13.632 0 13.656 0.084 ;
    END
  END cfg_data[37]
  PIN cfg_data[38]
    DIRECTION INPUT ;
    USE SIGNAL ;
    PORT
      LAYER M5 ;
        RECT  13.872 0 13.896 0.084 ;
    END
  END cfg_data[38]
  PIN cfg_data[39]
    DIRECTION INPUT ;
    USE SIGNAL ;
    PORT
      LAYER M5 ;
        RECT  14.16 0 14.184 0.084 ;
    END
  END cfg_data[39]
  PIN cfg_data[3]
    DIRECTION INPUT ;
    USE SIGNAL ;
    PORT
      LAYER M3 ;
        RECT  4.968 0 4.986 0.038 ;
    END
  END cfg_data[3]
  PIN cfg_data[40]
    DIRECTION INPUT ;
    USE SIGNAL ;
    PORT
      LAYER M5 ;
        RECT  14.4 0 14.424 0.084 ;
    END
  END cfg_data[40]
  PIN cfg_data[41]
    DIRECTION INPUT ;
    USE SIGNAL ;
    PORT
      LAYER M5 ;
        RECT  14.64 0 14.664 0.084 ;
    END
  END cfg_data[41]
  PIN cfg_data[42]
    DIRECTION INPUT ;
    USE SIGNAL ;
    PORT
      LAYER M5 ;
        RECT  14.928 0 14.952 0.084 ;
    END
  END cfg_data[42]
  PIN cfg_data[43]
    DIRECTION INPUT ;
    USE SIGNAL ;
    PORT
      LAYER M5 ;
        RECT  15.168 0 15.192 0.084 ;
    END
  END cfg_data[43]
  PIN cfg_data[44]
    DIRECTION INPUT ;
    USE SIGNAL ;
    PORT
      LAYER M5 ;
        RECT  15.408 0 15.432 0.084 ;
    END
  END cfg_data[44]
  PIN cfg_data[45]
    DIRECTION INPUT ;
    USE SIGNAL ;
    PORT
      LAYER M5 ;
        RECT  15.696 0 15.72 0.084 ;
    END
  END cfg_data[45]
  PIN cfg_data[46]
    DIRECTION INPUT ;
    USE SIGNAL ;
    PORT
      LAYER M5 ;
        RECT  15.936 0 15.96 0.084 ;
    END
  END cfg_data[46]
  PIN cfg_data[47]
    DIRECTION INPUT ;
    USE SIGNAL ;
    PORT
      LAYER M5 ;
        RECT  16.176 0 16.2 0.084 ;
    END
  END cfg_data[47]
  PIN cfg_data[48]
    DIRECTION INPUT ;
    USE SIGNAL ;
    PORT
      LAYER M5 ;
        RECT  16.464 0 16.488 0.084 ;
    END
  END cfg_data[48]
  PIN cfg_data[49]
    DIRECTION INPUT ;
    USE SIGNAL ;
    PORT
      LAYER M5 ;
        RECT  16.704 0 16.728 0.084 ;
    END
  END cfg_data[49]
  PIN cfg_data[4]
    DIRECTION INPUT ;
    USE SIGNAL ;
    PORT
      LAYER M3 ;
        RECT  5.22 0 5.238 0.038 ;
    END
  END cfg_data[4]
  PIN cfg_data[50]
    DIRECTION INPUT ;
    USE SIGNAL ;
    PORT
      LAYER M5 ;
        RECT  16.944 0 16.968 0.084 ;
    END
  END cfg_data[50]
  PIN cfg_data[51]
    DIRECTION INPUT ;
    USE SIGNAL ;
    PORT
      LAYER M5 ;
        RECT  17.232 0 17.256 0.084 ;
    END
  END cfg_data[51]
  PIN cfg_data[52]
    DIRECTION INPUT ;
    USE SIGNAL ;
    PORT
      LAYER M3 ;
        RECT  17.46 0 17.478 0.038 ;
    END
  END cfg_data[52]
  PIN cfg_data[53]
    DIRECTION INPUT ;
    USE SIGNAL ;
    PORT
      LAYER M3 ;
        RECT  17.712 0 17.73 0.038 ;
    END
  END cfg_data[53]
  PIN cfg_data[54]
    DIRECTION INPUT ;
    USE SIGNAL ;
    PORT
      LAYER M3 ;
        RECT  17.964 0 17.982 0.038 ;
    END
  END cfg_data[54]
  PIN cfg_data[55]
    DIRECTION INPUT ;
    USE SIGNAL ;
    PORT
      LAYER M3 ;
        RECT  18.252 0 18.27 0.038 ;
    END
  END cfg_data[55]
  PIN cfg_data[56]
    DIRECTION INPUT ;
    USE SIGNAL ;
    PORT
      LAYER M3 ;
        RECT  18.504 0 18.522 0.038 ;
    END
  END cfg_data[56]
  PIN cfg_data[57]
    DIRECTION INPUT ;
    USE SIGNAL ;
    PORT
      LAYER M3 ;
        RECT  18.756 0 18.774 0.038 ;
    END
  END cfg_data[57]
  PIN cfg_data[58]
    DIRECTION INPUT ;
    USE SIGNAL ;
    PORT
      LAYER M3 ;
        RECT  19.008 0 19.026 0.038 ;
    END
  END cfg_data[58]
  PIN cfg_data[59]
    DIRECTION INPUT ;
    USE SIGNAL ;
    PORT
      LAYER M3 ;
        RECT  19.26 0 19.278 0.038 ;
    END
  END cfg_data[59]
  PIN cfg_data[5]
    DIRECTION INPUT ;
    USE SIGNAL ;
    PORT
      LAYER M3 ;
        RECT  5.472 0 5.49 0.038 ;
    END
  END cfg_data[5]
  PIN cfg_data[60]
    DIRECTION INPUT ;
    USE SIGNAL ;
    PORT
      LAYER M3 ;
        RECT  19.512 0 19.53 0.038 ;
    END
  END cfg_data[60]
  PIN cfg_data[61]
    DIRECTION INPUT ;
    USE SIGNAL ;
    PORT
      LAYER M3 ;
        RECT  19.764 0 19.782 0.038 ;
    END
  END cfg_data[61]
  PIN cfg_data[62]
    DIRECTION INPUT ;
    USE SIGNAL ;
    PORT
      LAYER M3 ;
        RECT  20.016 0 20.034 0.038 ;
    END
  END cfg_data[62]
  PIN cfg_data[63]
    DIRECTION INPUT ;
    USE SIGNAL ;
    PORT
      LAYER M3 ;
        RECT  20.268 0 20.286 0.038 ;
    END
  END cfg_data[63]
  PIN cfg_data[64]
    DIRECTION INPUT ;
    USE SIGNAL ;
    PORT
      LAYER M3 ;
        RECT  20.52 0 20.538 0.038 ;
    END
  END cfg_data[64]
  PIN cfg_data[65]
    DIRECTION INPUT ;
    USE SIGNAL ;
    PORT
      LAYER M3 ;
        RECT  20.808 0 20.826 0.038 ;
    END
  END cfg_data[65]
  PIN cfg_data[66]
    DIRECTION INPUT ;
    USE SIGNAL ;
    PORT
      LAYER M3 ;
        RECT  21.06 0 21.078 0.038 ;
    END
  END cfg_data[66]
  PIN cfg_data[67]
    DIRECTION INPUT ;
    USE SIGNAL ;
    PORT
      LAYER M3 ;
        RECT  21.312 0 21.33 0.038 ;
    END
  END cfg_data[67]
  PIN cfg_data[68]
    DIRECTION INPUT ;
    USE SIGNAL ;
    PORT
      LAYER M3 ;
        RECT  21.564 0 21.582 0.038 ;
    END
  END cfg_data[68]
  PIN cfg_data[69]
    DIRECTION INPUT ;
    USE SIGNAL ;
    PORT
      LAYER M3 ;
        RECT  21.816 0 21.834 0.038 ;
    END
  END cfg_data[69]
  PIN cfg_data[6]
    DIRECTION INPUT ;
    USE SIGNAL ;
    PORT
      LAYER M3 ;
        RECT  5.724 0 5.742 0.038 ;
    END
  END cfg_data[6]
  PIN cfg_data[70]
    DIRECTION INPUT ;
    USE SIGNAL ;
    PORT
      LAYER M3 ;
        RECT  22.068 0 22.086 0.038 ;
    END
  END cfg_data[70]
  PIN cfg_data[71]
    DIRECTION INPUT ;
    USE SIGNAL ;
    PORT
      LAYER M3 ;
        RECT  22.32 0 22.338 0.038 ;
    END
  END cfg_data[71]
  PIN cfg_data[72]
    DIRECTION INPUT ;
    USE SIGNAL ;
    PORT
      LAYER M3 ;
        RECT  22.572 0 22.59 0.038 ;
    END
  END cfg_data[72]
  PIN cfg_data[73]
    DIRECTION INPUT ;
    USE SIGNAL ;
    PORT
      LAYER M3 ;
        RECT  22.824 0 22.842 0.038 ;
    END
  END cfg_data[73]
  PIN cfg_data[74]
    DIRECTION INPUT ;
    USE SIGNAL ;
    PORT
      LAYER M3 ;
        RECT  23.076 0 23.094 0.038 ;
    END
  END cfg_data[74]
  PIN cfg_data[75]
    DIRECTION INPUT ;
    USE SIGNAL ;
    PORT
      LAYER M3 ;
        RECT  23.328 0 23.346 0.038 ;
    END
  END cfg_data[75]
  PIN cfg_data[76]
    DIRECTION INPUT ;
    USE SIGNAL ;
    PORT
      LAYER M3 ;
        RECT  23.616 0 23.634 0.038 ;
    END
  END cfg_data[76]
  PIN cfg_data[77]
    DIRECTION INPUT ;
    USE SIGNAL ;
    PORT
      LAYER M3 ;
        RECT  23.868 0 23.886 0.038 ;
    END
  END cfg_data[77]
  PIN cfg_data[78]
    DIRECTION INPUT ;
    USE SIGNAL ;
    PORT
      LAYER M3 ;
        RECT  24.12 0 24.138 0.038 ;
    END
  END cfg_data[78]
  PIN cfg_data[79]
    DIRECTION INPUT ;
    USE SIGNAL ;
    PORT
      LAYER M3 ;
        RECT  24.372 0 24.39 0.038 ;
    END
  END cfg_data[79]
  PIN cfg_data[7]
    DIRECTION INPUT ;
    USE SIGNAL ;
    PORT
      LAYER M3 ;
        RECT  5.976 0 5.994 0.038 ;
    END
  END cfg_data[7]
  PIN cfg_data[80]
    DIRECTION INPUT ;
    USE SIGNAL ;
    PORT
      LAYER M3 ;
        RECT  24.624 0 24.642 0.038 ;
    END
  END cfg_data[80]
  PIN cfg_data[81]
    DIRECTION INPUT ;
    USE SIGNAL ;
    PORT
      LAYER M3 ;
        RECT  24.876 0 24.894 0.038 ;
    END
  END cfg_data[81]
  PIN cfg_data[82]
    DIRECTION INPUT ;
    USE SIGNAL ;
    PORT
      LAYER M3 ;
        RECT  25.128 0 25.146 0.038 ;
    END
  END cfg_data[82]
  PIN cfg_data[83]
    DIRECTION INPUT ;
    USE SIGNAL ;
    PORT
      LAYER M3 ;
        RECT  25.38 0 25.398 0.038 ;
    END
  END cfg_data[83]
  PIN cfg_data[84]
    DIRECTION INPUT ;
    USE SIGNAL ;
    PORT
      LAYER M5 ;
        RECT  25.632 0 25.656 0.084 ;
    END
  END cfg_data[84]
  PIN cfg_data[85]
    DIRECTION INPUT ;
    USE SIGNAL ;
    PORT
      LAYER M5 ;
        RECT  25.92 0 25.944 0.084 ;
    END
  END cfg_data[85]
  PIN cfg_data[86]
    DIRECTION INPUT ;
    USE SIGNAL ;
    PORT
      LAYER M5 ;
        RECT  26.16 0 26.184 0.084 ;
    END
  END cfg_data[86]
  PIN cfg_data[87]
    DIRECTION INPUT ;
    USE SIGNAL ;
    PORT
      LAYER M5 ;
        RECT  26.4 0 26.424 0.084 ;
    END
  END cfg_data[87]
  PIN cfg_data[88]
    DIRECTION INPUT ;
    USE SIGNAL ;
    PORT
      LAYER M5 ;
        RECT  26.64 0 26.664 0.084 ;
    END
  END cfg_data[88]
  PIN cfg_data[89]
    DIRECTION INPUT ;
    USE SIGNAL ;
    PORT
      LAYER M5 ;
        RECT  26.928 0 26.952 0.084 ;
    END
  END cfg_data[89]
  PIN cfg_data[8]
    DIRECTION INPUT ;
    USE SIGNAL ;
    PORT
      LAYER M3 ;
        RECT  6.228 0 6.246 0.038 ;
    END
  END cfg_data[8]
  PIN cfg_data[90]
    DIRECTION INPUT ;
    USE SIGNAL ;
    PORT
      LAYER M5 ;
        RECT  27.168 0 27.192 0.084 ;
    END
  END cfg_data[90]
  PIN cfg_data[91]
    DIRECTION INPUT ;
    USE SIGNAL ;
    PORT
      LAYER M5 ;
        RECT  27.408 0 27.432 0.084 ;
    END
  END cfg_data[91]
  PIN cfg_data[92]
    DIRECTION INPUT ;
    USE SIGNAL ;
    PORT
      LAYER M5 ;
        RECT  27.696 0 27.72 0.084 ;
    END
  END cfg_data[92]
  PIN cfg_data[93]
    DIRECTION INPUT ;
    USE SIGNAL ;
    PORT
      LAYER M5 ;
        RECT  27.936 0 27.96 0.084 ;
    END
  END cfg_data[93]
  PIN cfg_data[94]
    DIRECTION INPUT ;
    USE SIGNAL ;
    PORT
      LAYER M5 ;
        RECT  28.176 0 28.2 0.084 ;
    END
  END cfg_data[94]
  PIN cfg_data[95]
    DIRECTION INPUT ;
    USE SIGNAL ;
    PORT
      LAYER M5 ;
        RECT  28.464 0 28.488 0.084 ;
    END
  END cfg_data[95]
  PIN cfg_data[96]
    DIRECTION INPUT ;
    USE SIGNAL ;
    PORT
      LAYER M5 ;
        RECT  28.704 0 28.728 0.084 ;
    END
  END cfg_data[96]
  PIN cfg_data[97]
    DIRECTION INPUT ;
    USE SIGNAL ;
    PORT
      LAYER M5 ;
        RECT  28.944 0 28.968 0.084 ;
    END
  END cfg_data[97]
  PIN cfg_data[98]
    DIRECTION INPUT ;
    USE SIGNAL ;
    PORT
      LAYER M5 ;
        RECT  29.232 0 29.256 0.084 ;
    END
  END cfg_data[98]
  PIN cfg_data[99]
    DIRECTION INPUT ;
    USE SIGNAL ;
    PORT
      LAYER M5 ;
        RECT  29.472 0 29.496 0.084 ;
    END
  END cfg_data[99]
  PIN cfg_data[9]
    DIRECTION INPUT ;
    USE SIGNAL ;
    PORT
      LAYER M3 ;
        RECT  6.48 0 6.498 0.038 ;
    END
  END cfg_data[9]
  PIN cfg_target[0]
    DIRECTION INPUT ;
    USE SIGNAL ;
    PORT
      LAYER M3 ;
        RECT  69.588 0 69.606 0.038 ;
    END
  END cfg_target[0]
  PIN cfg_target[1]
    DIRECTION INPUT ;
    USE SIGNAL ;
    PORT
      LAYER M3 ;
        RECT  69.84 0 69.858 0.038 ;
    END
  END cfg_target[1]
  PIN cfg_target[2]
    DIRECTION INPUT ;
    USE SIGNAL ;
    PORT
      LAYER M3 ;
        RECT  70.092 0 70.11 0.038 ;
    END
  END cfg_target[2]
  PIN cfg_target[3]
    DIRECTION INPUT ;
    USE SIGNAL ;
    PORT
      LAYER M3 ;
        RECT  70.344 0 70.362 0.038 ;
    END
  END cfg_target[3]
  PIN cfg_target[4]
    DIRECTION INPUT ;
    USE SIGNAL ;
    PORT
      LAYER M3 ;
        RECT  70.596 0 70.614 0.038 ;
    END
  END cfg_target[4]
  PIN cfg_target[5]
    DIRECTION INPUT ;
    USE SIGNAL ;
    PORT
      LAYER M3 ;
        RECT  70.848 0 70.866 0.038 ;
    END
  END cfg_target[5]
  PIN cfg_target[6]
    DIRECTION INPUT ;
    USE SIGNAL ;
    PORT
      LAYER M3 ;
        RECT  71.136 0 71.154 0.038 ;
    END
  END cfg_target[6]
  PIN cfg_target[7]
    DIRECTION INPUT ;
    USE SIGNAL ;
    PORT
      LAYER M3 ;
        RECT  71.388 0 71.406 0.038 ;
    END
  END cfg_target[7]
  PIN cfg_v
    DIRECTION INPUT ;
    USE SIGNAL ;
    PORT
      LAYER M3 ;
        RECT  71.64 0 71.658 0.038 ;
    END
  END cfg_v
  PIN clk
    DIRECTION INPUT ;
    USE SIGNAL ;
    PORT
      LAYER M3 ;
        RECT  50.58 0 50.598 0.038 ;
    END
  END clk
  PIN configured
    DIRECTION OUTPUT ;
    USE SIGNAL ;
    PORT
      LAYER M3 ;
        RECT  71.892 0 71.91 0.038 ;
    END
  END configured
  PIN desc_base[0]
    DIRECTION INPUT ;
    USE SIGNAL ;
    PORT
      LAYER M3 ;
        RECT  72.144 0 72.162 0.038 ;
    END
  END desc_base[0]
  PIN desc_base[10]
    DIRECTION INPUT ;
    USE SIGNAL ;
    PORT
      LAYER M5 ;
        RECT  74.688 0 74.712 0.084 ;
    END
  END desc_base[10]
  PIN desc_base[11]
    DIRECTION INPUT ;
    USE SIGNAL ;
    PORT
      LAYER M5 ;
        RECT  74.928 0 74.952 0.084 ;
    END
  END desc_base[11]
  PIN desc_base[1]
    DIRECTION INPUT ;
    USE SIGNAL ;
    PORT
      LAYER M3 ;
        RECT  72.396 0 72.414 0.038 ;
    END
  END desc_base[1]
  PIN desc_base[2]
    DIRECTION INPUT ;
    USE SIGNAL ;
    PORT
      LAYER M3 ;
        RECT  72.648 0 72.666 0.038 ;
    END
  END desc_base[2]
  PIN desc_base[3]
    DIRECTION INPUT ;
    USE SIGNAL ;
    PORT
      LAYER M3 ;
        RECT  72.9 0 72.918 0.038 ;
    END
  END desc_base[3]
  PIN desc_base[4]
    DIRECTION INPUT ;
    USE SIGNAL ;
    PORT
      LAYER M3 ;
        RECT  73.152 0 73.17 0.038 ;
    END
  END desc_base[4]
  PIN desc_base[5]
    DIRECTION INPUT ;
    USE SIGNAL ;
    PORT
      LAYER M3 ;
        RECT  73.404 0 73.422 0.038 ;
    END
  END desc_base[5]
  PIN desc_base[6]
    DIRECTION INPUT ;
    USE SIGNAL ;
    PORT
      LAYER M3 ;
        RECT  73.692 0 73.71 0.038 ;
    END
  END desc_base[6]
  PIN desc_base[7]
    DIRECTION INPUT ;
    USE SIGNAL ;
    PORT
      LAYER M3 ;
        RECT  73.944 0 73.962 0.038 ;
    END
  END desc_base[7]
  PIN desc_base[8]
    DIRECTION INPUT ;
    USE SIGNAL ;
    PORT
      LAYER M3 ;
        RECT  74.196 0 74.214 0.038 ;
    END
  END desc_base[8]
  PIN desc_base[9]
    DIRECTION INPUT ;
    USE SIGNAL ;
    PORT
      LAYER M3 ;
        RECT  74.448 0 74.466 0.038 ;
    END
  END desc_base[9]
  PIN desc_limit[0]
    DIRECTION INPUT ;
    USE SIGNAL ;
    PORT
      LAYER M5 ;
        RECT  75.216 0 75.24 0.084 ;
    END
  END desc_limit[0]
  PIN desc_limit[10]
    DIRECTION INPUT ;
    USE SIGNAL ;
    PORT
      LAYER M5 ;
        RECT  77.76 0 77.784 0.084 ;
    END
  END desc_limit[10]
  PIN desc_limit[11]
    DIRECTION INPUT ;
    USE SIGNAL ;
    PORT
      LAYER M5 ;
        RECT  78 0 78.024 0.084 ;
    END
  END desc_limit[11]
  PIN desc_limit[12]
    DIRECTION INPUT ;
    USE SIGNAL ;
    PORT
      LAYER M5 ;
        RECT  78.288 0 78.312 0.084 ;
    END
  END desc_limit[12]
  PIN desc_limit[1]
    DIRECTION INPUT ;
    USE SIGNAL ;
    PORT
      LAYER M5 ;
        RECT  75.456 0 75.48 0.084 ;
    END
  END desc_limit[1]
  PIN desc_limit[2]
    DIRECTION INPUT ;
    USE SIGNAL ;
    PORT
      LAYER M5 ;
        RECT  75.696 0 75.72 0.084 ;
    END
  END desc_limit[2]
  PIN desc_limit[3]
    DIRECTION INPUT ;
    USE SIGNAL ;
    PORT
      LAYER M5 ;
        RECT  75.984 0 76.008 0.084 ;
    END
  END desc_limit[3]
  PIN desc_limit[4]
    DIRECTION INPUT ;
    USE SIGNAL ;
    PORT
      LAYER M5 ;
        RECT  76.224 0 76.248 0.084 ;
    END
  END desc_limit[4]
  PIN desc_limit[5]
    DIRECTION INPUT ;
    USE SIGNAL ;
    PORT
      LAYER M5 ;
        RECT  76.464 0 76.488 0.084 ;
    END
  END desc_limit[5]
  PIN desc_limit[6]
    DIRECTION INPUT ;
    USE SIGNAL ;
    PORT
      LAYER M5 ;
        RECT  76.752 0 76.776 0.084 ;
    END
  END desc_limit[6]
  PIN desc_limit[7]
    DIRECTION INPUT ;
    USE SIGNAL ;
    PORT
      LAYER M5 ;
        RECT  76.992 0 77.016 0.084 ;
    END
  END desc_limit[7]
  PIN desc_limit[8]
    DIRECTION INPUT ;
    USE SIGNAL ;
    PORT
      LAYER M5 ;
        RECT  77.232 0 77.256 0.084 ;
    END
  END desc_limit[8]
  PIN desc_limit[9]
    DIRECTION INPUT ;
    USE SIGNAL ;
    PORT
      LAYER M5 ;
        RECT  77.52 0 77.544 0.084 ;
    END
  END desc_limit[9]
  PIN desc_loops[0]
    DIRECTION INPUT ;
    USE SIGNAL ;
    PORT
      LAYER M5 ;
        RECT  78.528 0 78.552 0.084 ;
    END
  END desc_loops[0]
  PIN desc_loops[10]
    DIRECTION INPUT ;
    USE SIGNAL ;
    PORT
      LAYER M5 ;
        RECT  81.072 0 81.096 0.084 ;
    END
  END desc_loops[10]
  PIN desc_loops[11]
    DIRECTION INPUT ;
    USE SIGNAL ;
    PORT
      LAYER M5 ;
        RECT  81.36 0 81.384 0.084 ;
    END
  END desc_loops[11]
  PIN desc_loops[12]
    DIRECTION INPUT ;
    USE SIGNAL ;
    PORT
      LAYER M5 ;
        RECT  81.6 0 81.624 0.084 ;
    END
  END desc_loops[12]
  PIN desc_loops[13]
    DIRECTION INPUT ;
    USE SIGNAL ;
    PORT
      LAYER M5 ;
        RECT  81.84 0 81.864 0.084 ;
    END
  END desc_loops[13]
  PIN desc_loops[14]
    DIRECTION INPUT ;
    USE SIGNAL ;
    PORT
      LAYER M5 ;
        RECT  82.08 0 82.104 0.084 ;
    END
  END desc_loops[14]
  PIN desc_loops[15]
    DIRECTION INPUT ;
    USE SIGNAL ;
    PORT
      LAYER M5 ;
        RECT  82.368 0 82.392 0.084 ;
    END
  END desc_loops[15]
  PIN desc_loops[1]
    DIRECTION INPUT ;
    USE SIGNAL ;
    PORT
      LAYER M5 ;
        RECT  78.768 0 78.792 0.084 ;
    END
  END desc_loops[1]
  PIN desc_loops[2]
    DIRECTION INPUT ;
    USE SIGNAL ;
    PORT
      LAYER M5 ;
        RECT  79.056 0 79.08 0.084 ;
    END
  END desc_loops[2]
  PIN desc_loops[3]
    DIRECTION INPUT ;
    USE SIGNAL ;
    PORT
      LAYER M5 ;
        RECT  79.296 0 79.32 0.084 ;
    END
  END desc_loops[3]
  PIN desc_loops[4]
    DIRECTION INPUT ;
    USE SIGNAL ;
    PORT
      LAYER M5 ;
        RECT  79.536 0 79.56 0.084 ;
    END
  END desc_loops[4]
  PIN desc_loops[5]
    DIRECTION INPUT ;
    USE SIGNAL ;
    PORT
      LAYER M5 ;
        RECT  79.824 0 79.848 0.084 ;
    END
  END desc_loops[5]
  PIN desc_loops[6]
    DIRECTION INPUT ;
    USE SIGNAL ;
    PORT
      LAYER M5 ;
        RECT  80.064 0 80.088 0.084 ;
    END
  END desc_loops[6]
  PIN desc_loops[7]
    DIRECTION INPUT ;
    USE SIGNAL ;
    PORT
      LAYER M5 ;
        RECT  80.304 0 80.328 0.084 ;
    END
  END desc_loops[7]
  PIN desc_loops[8]
    DIRECTION INPUT ;
    USE SIGNAL ;
    PORT
      LAYER M5 ;
        RECT  80.592 0 80.616 0.084 ;
    END
  END desc_loops[8]
  PIN desc_loops[9]
    DIRECTION INPUT ;
    USE SIGNAL ;
    PORT
      LAYER M5 ;
        RECT  80.832 0 80.856 0.084 ;
    END
  END desc_loops[9]
  PIN desc_v
    DIRECTION INPUT ;
    USE SIGNAL ;
    PORT
      LAYER M5 ;
        RECT  82.608 0 82.632 0.084 ;
    END
  END desc_v
  PIN fault
    DIRECTION OUTPUT ;
    USE SIGNAL ;
    PORT
      LAYER M3 ;
        RECT  82.872 0 82.89 0.038 ;
    END
  END fault
  PIN fault_cause[0]
    DIRECTION OUTPUT ;
    USE SIGNAL ;
    PORT
      LAYER M3 ;
        RECT  83.124 0 83.142 0.038 ;
    END
  END fault_cause[0]
  PIN fault_cause[10]
    DIRECTION OUTPUT ;
    USE SIGNAL ;
    PORT
      LAYER M3 ;
        RECT  85.68 0 85.698 0.038 ;
    END
  END fault_cause[10]
  PIN fault_cause[11]
    DIRECTION OUTPUT ;
    USE SIGNAL ;
    PORT
      LAYER M3 ;
        RECT  85.932 0 85.95 0.038 ;
    END
  END fault_cause[11]
  PIN fault_cause[12]
    DIRECTION OUTPUT ;
    USE SIGNAL ;
    PORT
      LAYER M3 ;
        RECT  86.184 0 86.202 0.038 ;
    END
  END fault_cause[12]
  PIN fault_cause[13]
    DIRECTION OUTPUT ;
    USE SIGNAL ;
    PORT
      LAYER M3 ;
        RECT  86.436 0 86.454 0.038 ;
    END
  END fault_cause[13]
  PIN fault_cause[14]
    DIRECTION OUTPUT ;
    USE SIGNAL ;
    PORT
      LAYER M3 ;
        RECT  86.688 0 86.706 0.038 ;
    END
  END fault_cause[14]
  PIN fault_cause[15]
    DIRECTION OUTPUT ;
    USE SIGNAL ;
    PORT
      LAYER M3 ;
        RECT  86.976 0 86.994 0.038 ;
    END
  END fault_cause[15]
  PIN fault_cause[1]
    DIRECTION OUTPUT ;
    USE SIGNAL ;
    PORT
      LAYER M3 ;
        RECT  83.376 0 83.394 0.038 ;
    END
  END fault_cause[1]
  PIN fault_cause[2]
    DIRECTION OUTPUT ;
    USE SIGNAL ;
    PORT
      LAYER M3 ;
        RECT  83.628 0 83.646 0.038 ;
    END
  END fault_cause[2]
  PIN fault_cause[3]
    DIRECTION OUTPUT ;
    USE SIGNAL ;
    PORT
      LAYER M3 ;
        RECT  83.88 0 83.898 0.038 ;
    END
  END fault_cause[3]
  PIN fault_cause[4]
    DIRECTION OUTPUT ;
    USE SIGNAL ;
    PORT
      LAYER M3 ;
        RECT  84.132 0 84.15 0.038 ;
    END
  END fault_cause[4]
  PIN fault_cause[5]
    DIRECTION OUTPUT ;
    USE SIGNAL ;
    PORT
      LAYER M3 ;
        RECT  84.42 0 84.438 0.038 ;
    END
  END fault_cause[5]
  PIN fault_cause[6]
    DIRECTION OUTPUT ;
    USE SIGNAL ;
    PORT
      LAYER M3 ;
        RECT  84.672 0 84.69 0.038 ;
    END
  END fault_cause[6]
  PIN fault_cause[7]
    DIRECTION OUTPUT ;
    USE SIGNAL ;
    PORT
      LAYER M3 ;
        RECT  84.924 0 84.942 0.038 ;
    END
  END fault_cause[7]
  PIN fault_cause[8]
    DIRECTION OUTPUT ;
    USE SIGNAL ;
    PORT
      LAYER M3 ;
        RECT  85.176 0 85.194 0.038 ;
    END
  END fault_cause[8]
  PIN fault_cause[9]
    DIRECTION OUTPUT ;
    USE SIGNAL ;
    PORT
      LAYER M3 ;
        RECT  85.428 0 85.446 0.038 ;
    END
  END fault_cause[9]
  PIN init_busy
    DIRECTION OUTPUT ;
    USE SIGNAL ;
    PORT
      LAYER M3 ;
        RECT  87.228 0 87.246 0.038 ;
    END
  END init_busy
  PIN issuer_busy
    DIRECTION INPUT ;
    USE SIGNAL ;
    PORT
      LAYER M3 ;
        RECT  87.48 0 87.498 0.038 ;
    END
  END issuer_busy
  PIN issuer_cfg[0]
    DIRECTION OUTPUT ;
    USE SIGNAL ;
    PORT
      LAYER M3 ;
        RECT  87.732 0 87.75 0.038 ;
    END
  END issuer_cfg[0]
  PIN issuer_cfg[10]
    DIRECTION OUTPUT ;
    USE SIGNAL ;
    PORT
      LAYER M3 ;
        RECT  90.288 0 90.306 0.038 ;
    END
  END issuer_cfg[10]
  PIN issuer_cfg[11]
    DIRECTION OUTPUT ;
    USE SIGNAL ;
    PORT
      LAYER M3 ;
        RECT  90.54 0 90.558 0.038 ;
    END
  END issuer_cfg[11]
  PIN issuer_cfg[12]
    DIRECTION OUTPUT ;
    USE SIGNAL ;
    PORT
      LAYER M3 ;
        RECT  90.792 0 90.81 0.038 ;
    END
  END issuer_cfg[12]
  PIN issuer_cfg[13]
    DIRECTION OUTPUT ;
    USE SIGNAL ;
    PORT
      LAYER M5 ;
        RECT  91.056 0 91.08 0.084 ;
    END
  END issuer_cfg[13]
  PIN issuer_cfg[14]
    DIRECTION OUTPUT ;
    USE SIGNAL ;
    PORT
      LAYER M5 ;
        RECT  91.296 0 91.32 0.084 ;
    END
  END issuer_cfg[14]
  PIN issuer_cfg[15]
    DIRECTION OUTPUT ;
    USE SIGNAL ;
    PORT
      LAYER M5 ;
        RECT  91.536 0 91.56 0.084 ;
    END
  END issuer_cfg[15]
  PIN issuer_cfg[16]
    DIRECTION OUTPUT ;
    USE SIGNAL ;
    PORT
      LAYER M5 ;
        RECT  91.824 0 91.848 0.084 ;
    END
  END issuer_cfg[16]
  PIN issuer_cfg[17]
    DIRECTION OUTPUT ;
    USE SIGNAL ;
    PORT
      LAYER M5 ;
        RECT  92.064 0 92.088 0.084 ;
    END
  END issuer_cfg[17]
  PIN issuer_cfg[18]
    DIRECTION OUTPUT ;
    USE SIGNAL ;
    PORT
      LAYER M5 ;
        RECT  92.304 0 92.328 0.084 ;
    END
  END issuer_cfg[18]
  PIN issuer_cfg[19]
    DIRECTION OUTPUT ;
    USE SIGNAL ;
    PORT
      LAYER M5 ;
        RECT  92.592 0 92.616 0.084 ;
    END
  END issuer_cfg[19]
  PIN issuer_cfg[1]
    DIRECTION OUTPUT ;
    USE SIGNAL ;
    PORT
      LAYER M3 ;
        RECT  87.984 0 88.002 0.038 ;
    END
  END issuer_cfg[1]
  PIN issuer_cfg[20]
    DIRECTION OUTPUT ;
    USE SIGNAL ;
    PORT
      LAYER M5 ;
        RECT  92.832 0 92.856 0.084 ;
    END
  END issuer_cfg[20]
  PIN issuer_cfg[21]
    DIRECTION OUTPUT ;
    USE SIGNAL ;
    PORT
      LAYER M5 ;
        RECT  93.072 0 93.096 0.084 ;
    END
  END issuer_cfg[21]
  PIN issuer_cfg[22]
    DIRECTION OUTPUT ;
    USE SIGNAL ;
    PORT
      LAYER M5 ;
        RECT  93.36 0 93.384 0.084 ;
    END
  END issuer_cfg[22]
  PIN issuer_cfg[23]
    DIRECTION OUTPUT ;
    USE SIGNAL ;
    PORT
      LAYER M5 ;
        RECT  93.6 0 93.624 0.084 ;
    END
  END issuer_cfg[23]
  PIN issuer_cfg[24]
    DIRECTION OUTPUT ;
    USE SIGNAL ;
    PORT
      LAYER M5 ;
        RECT  93.84 0 93.864 0.084 ;
    END
  END issuer_cfg[24]
  PIN issuer_cfg[25]
    DIRECTION OUTPUT ;
    USE SIGNAL ;
    PORT
      LAYER M5 ;
        RECT  94.128 0 94.152 0.084 ;
    END
  END issuer_cfg[25]
  PIN issuer_cfg[26]
    DIRECTION OUTPUT ;
    USE SIGNAL ;
    PORT
      LAYER M5 ;
        RECT  94.368 0 94.392 0.084 ;
    END
  END issuer_cfg[26]
  PIN issuer_cfg[27]
    DIRECTION OUTPUT ;
    USE SIGNAL ;
    PORT
      LAYER M5 ;
        RECT  94.608 0 94.632 0.084 ;
    END
  END issuer_cfg[27]
  PIN issuer_cfg[28]
    DIRECTION OUTPUT ;
    USE SIGNAL ;
    PORT
      LAYER M5 ;
        RECT  94.896 0 94.92 0.084 ;
    END
  END issuer_cfg[28]
  PIN issuer_cfg[29]
    DIRECTION OUTPUT ;
    USE SIGNAL ;
    PORT
      LAYER M5 ;
        RECT  95.136 0 95.16 0.084 ;
    END
  END issuer_cfg[29]
  PIN issuer_cfg[2]
    DIRECTION OUTPUT ;
    USE SIGNAL ;
    PORT
      LAYER M3 ;
        RECT  88.236 0 88.254 0.038 ;
    END
  END issuer_cfg[2]
  PIN issuer_cfg[30]
    DIRECTION OUTPUT ;
    USE SIGNAL ;
    PORT
      LAYER M5 ;
        RECT  95.376 0 95.4 0.084 ;
    END
  END issuer_cfg[30]
  PIN issuer_cfg[31]
    DIRECTION OUTPUT ;
    USE SIGNAL ;
    PORT
      LAYER M5 ;
        RECT  95.664 0 95.688 0.084 ;
    END
  END issuer_cfg[31]
  PIN issuer_cfg[32]
    DIRECTION OUTPUT ;
    USE SIGNAL ;
    PORT
      LAYER M5 ;
        RECT  95.904 0 95.928 0.084 ;
    END
  END issuer_cfg[32]
  PIN issuer_cfg[33]
    DIRECTION OUTPUT ;
    USE SIGNAL ;
    PORT
      LAYER M5 ;
        RECT  96.144 0 96.168 0.084 ;
    END
  END issuer_cfg[33]
  PIN issuer_cfg[34]
    DIRECTION OUTPUT ;
    USE SIGNAL ;
    PORT
      LAYER M5 ;
        RECT  96.432 0 96.456 0.084 ;
    END
  END issuer_cfg[34]
  PIN issuer_cfg[35]
    DIRECTION OUTPUT ;
    USE SIGNAL ;
    PORT
      LAYER M5 ;
        RECT  96.672 0 96.696 0.084 ;
    END
  END issuer_cfg[35]
  PIN issuer_cfg[36]
    DIRECTION OUTPUT ;
    USE SIGNAL ;
    PORT
      LAYER M5 ;
        RECT  96.912 0 96.936 0.084 ;
    END
  END issuer_cfg[36]
  PIN issuer_cfg[3]
    DIRECTION OUTPUT ;
    USE SIGNAL ;
    PORT
      LAYER M3 ;
        RECT  88.488 0 88.506 0.038 ;
    END
  END issuer_cfg[3]
  PIN issuer_cfg[4]
    DIRECTION OUTPUT ;
    USE SIGNAL ;
    PORT
      LAYER M3 ;
        RECT  88.74 0 88.758 0.038 ;
    END
  END issuer_cfg[4]
  PIN issuer_cfg[5]
    DIRECTION OUTPUT ;
    USE SIGNAL ;
    PORT
      LAYER M3 ;
        RECT  88.992 0 89.01 0.038 ;
    END
  END issuer_cfg[5]
  PIN issuer_cfg[6]
    DIRECTION OUTPUT ;
    USE SIGNAL ;
    PORT
      LAYER M3 ;
        RECT  89.244 0 89.262 0.038 ;
    END
  END issuer_cfg[6]
  PIN issuer_cfg[7]
    DIRECTION OUTPUT ;
    USE SIGNAL ;
    PORT
      LAYER M3 ;
        RECT  89.532 0 89.55 0.038 ;
    END
  END issuer_cfg[7]
  PIN issuer_cfg[8]
    DIRECTION OUTPUT ;
    USE SIGNAL ;
    PORT
      LAYER M3 ;
        RECT  89.784 0 89.802 0.038 ;
    END
  END issuer_cfg[8]
  PIN issuer_cfg[9]
    DIRECTION OUTPUT ;
    USE SIGNAL ;
    PORT
      LAYER M3 ;
        RECT  90.036 0 90.054 0.038 ;
    END
  END issuer_cfg[9]
  PIN issuer_fault
    DIRECTION INPUT ;
    USE SIGNAL ;
    PORT
      LAYER M5 ;
        RECT  97.152 0 97.176 0.084 ;
    END
  END issuer_fault
  PIN issuer_start
    DIRECTION OUTPUT ;
    USE SIGNAL ;
    PORT
      LAYER M5 ;
        RECT  97.44 0 97.464 0.084 ;
    END
  END issuer_start
  PIN issuer_start_pc[0]
    DIRECTION OUTPUT ;
    USE SIGNAL ;
    PORT
      LAYER M5 ;
        RECT  97.68 0 97.704 0.084 ;
    END
  END issuer_start_pc[0]
  PIN issuer_start_pc[1]
    DIRECTION OUTPUT ;
    USE SIGNAL ;
    PORT
      LAYER M5 ;
        RECT  97.92 0 97.944 0.084 ;
    END
  END issuer_start_pc[1]
  PIN issuer_start_pc[2]
    DIRECTION OUTPUT ;
    USE SIGNAL ;
    PORT
      LAYER M5 ;
        RECT  98.208 0 98.232 0.084 ;
    END
  END issuer_start_pc[2]
  PIN issuer_start_pc[3]
    DIRECTION OUTPUT ;
    USE SIGNAL ;
    PORT
      LAYER M5 ;
        RECT  98.448 0 98.472 0.084 ;
    END
  END issuer_start_pc[3]
  PIN issuer_start_pc[4]
    DIRECTION OUTPUT ;
    USE SIGNAL ;
    PORT
      LAYER M5 ;
        RECT  98.688 0 98.712 0.084 ;
    END
  END issuer_start_pc[4]
  PIN issuer_start_pc[5]
    DIRECTION OUTPUT ;
    USE SIGNAL ;
    PORT
      LAYER M5 ;
        RECT  98.976 0 99 0.084 ;
    END
  END issuer_start_pc[5]
  PIN issuer_start_pc[6]
    DIRECTION OUTPUT ;
    USE SIGNAL ;
    PORT
      LAYER M3 ;
        RECT  99.216 0 99.234 0.038 ;
    END
  END issuer_start_pc[6]
  PIN issuer_uop_pc[0]
    DIRECTION INPUT ;
    USE SIGNAL ;
    PORT
      LAYER M3 ;
        RECT  99.468 0 99.486 0.038 ;
    END
  END issuer_uop_pc[0]
  PIN issuer_uop_pc[1]
    DIRECTION INPUT ;
    USE SIGNAL ;
    PORT
      LAYER M3 ;
        RECT  99.72 0 99.738 0.038 ;
    END
  END issuer_uop_pc[1]
  PIN issuer_uop_pc[2]
    DIRECTION INPUT ;
    USE SIGNAL ;
    PORT
      LAYER M3 ;
        RECT  99.972 0 99.99 0.038 ;
    END
  END issuer_uop_pc[2]
  PIN issuer_uop_pc[3]
    DIRECTION INPUT ;
    USE SIGNAL ;
    PORT
      LAYER M3 ;
        RECT  100.26 0 100.278 0.038 ;
    END
  END issuer_uop_pc[3]
  PIN issuer_uop_pc[4]
    DIRECTION INPUT ;
    USE SIGNAL ;
    PORT
      LAYER M3 ;
        RECT  100.512 0 100.53 0.038 ;
    END
  END issuer_uop_pc[4]
  PIN issuer_uop_pc[5]
    DIRECTION INPUT ;
    USE SIGNAL ;
    PORT
      LAYER M3 ;
        RECT  100.764 0 100.782 0.038 ;
    END
  END issuer_uop_pc[5]
  PIN issuer_uop_pc[6]
    DIRECTION INPUT ;
    USE SIGNAL ;
    PORT
      LAYER M3 ;
        RECT  101.016 0 101.034 0.038 ;
    END
  END issuer_uop_pc[6]
  PIN issuer_uop_v
    DIRECTION INPUT ;
    USE SIGNAL ;
    PORT
      LAYER M3 ;
        RECT  101.268 0 101.286 0.038 ;
    END
  END issuer_uop_v
  PIN launch_v
    DIRECTION INPUT ;
    USE SIGNAL ;
    PORT
      LAYER M3 ;
        RECT  101.52 0 101.538 0.038 ;
    END
  END launch_v
  PIN link_abort[0]
    DIRECTION INPUT ;
    USE SIGNAL ;
    PORT
      LAYER M4 ;
        RECT  0 7.92 0.084 7.944 ;
    END
  END link_abort[0]
  PIN link_abort[1]
    DIRECTION INPUT ;
    USE SIGNAL ;
    PORT
      LAYER M4 ;
        RECT  0 21.792 0.084 21.816 ;
    END
  END link_abort[1]
  PIN program_active
    DIRECTION INPUT ;
    USE SIGNAL ;
    PORT
      LAYER M3 ;
        RECT  101.772 0 101.79 0.038 ;
    END
  END program_active
  PIN program_fault
    DIRECTION OUTPUT ;
    USE SIGNAL ;
    PORT
      LAYER M3 ;
        RECT  102.024 0 102.042 0.038 ;
    END
  END program_fault
  PIN protocol_fault
    DIRECTION INPUT ;
    USE SIGNAL ;
    PORT
      LAYER M4 ;
        RECT  103.596 17.232 103.68 17.256 ;
    END
  END protocol_fault
  PIN qid[0]
    DIRECTION INPUT ;
    USE SIGNAL ;
    PORT
      LAYER M3 ;
        RECT  102.276 0 102.294 0.038 ;
    END
  END qid[0]
  PIN qid[1]
    DIRECTION INPUT ;
    USE SIGNAL ;
    PORT
      LAYER M3 ;
        RECT  102.528 0 102.546 0.038 ;
    END
  END qid[1]
  PIN reduce_fault
    DIRECTION INPUT ;
    USE SIGNAL ;
    PORT
      LAYER M4 ;
        RECT  0 35.616 0.084 35.64 ;
    END
  END reduce_fault
  PIN ring_fault
    DIRECTION INPUT ;
    USE SIGNAL ;
    PORT
      LAYER M4 ;
        RECT  0 49.488 0.084 49.512 ;
    END
  END ring_fault
  PIN rst_n
    DIRECTION INPUT ;
    USE SIGNAL ;
    PORT
      LAYER M3 ;
        RECT  51.804 0 51.822 0.038 ;
    END
  END rst_n
  PIN select_fault[0]
    DIRECTION INPUT ;
    USE SIGNAL ;
    PORT
      LAYER M4 ;
        RECT  103.596 18.672 103.68 18.696 ;
    END
  END select_fault[0]
  PIN select_fault[10]
    DIRECTION INPUT ;
    USE SIGNAL ;
    PORT
      LAYER M4 ;
        RECT  103.596 32.784 103.68 32.808 ;
    END
  END select_fault[10]
  PIN select_fault[11]
    DIRECTION INPUT ;
    USE SIGNAL ;
    PORT
      LAYER M4 ;
        RECT  103.596 34.224 103.68 34.248 ;
    END
  END select_fault[11]
  PIN select_fault[12]
    DIRECTION INPUT ;
    USE SIGNAL ;
    PORT
      LAYER M4 ;
        RECT  103.596 35.616 103.68 35.64 ;
    END
  END select_fault[12]
  PIN select_fault[13]
    DIRECTION INPUT ;
    USE SIGNAL ;
    PORT
      LAYER M4 ;
        RECT  103.596 37.056 103.68 37.08 ;
    END
  END select_fault[13]
  PIN select_fault[14]
    DIRECTION INPUT ;
    USE SIGNAL ;
    PORT
      LAYER M4 ;
        RECT  103.596 38.448 103.68 38.472 ;
    END
  END select_fault[14]
  PIN select_fault[15]
    DIRECTION INPUT ;
    USE SIGNAL ;
    PORT
      LAYER M4 ;
        RECT  103.596 39.888 103.68 39.912 ;
    END
  END select_fault[15]
  PIN select_fault[16]
    DIRECTION INPUT ;
    USE SIGNAL ;
    PORT
      LAYER M4 ;
        RECT  103.596 41.28 103.68 41.304 ;
    END
  END select_fault[16]
  PIN select_fault[17]
    DIRECTION INPUT ;
    USE SIGNAL ;
    PORT
      LAYER M4 ;
        RECT  103.596 42.72 103.68 42.744 ;
    END
  END select_fault[17]
  PIN select_fault[1]
    DIRECTION INPUT ;
    USE SIGNAL ;
    PORT
      LAYER M4 ;
        RECT  103.596 20.064 103.68 20.088 ;
    END
  END select_fault[1]
  PIN select_fault[2]
    DIRECTION INPUT ;
    USE SIGNAL ;
    PORT
      LAYER M4 ;
        RECT  103.596 21.504 103.68 21.528 ;
    END
  END select_fault[2]
  PIN select_fault[3]
    DIRECTION INPUT ;
    USE SIGNAL ;
    PORT
      LAYER M4 ;
        RECT  103.596 22.896 103.68 22.92 ;
    END
  END select_fault[3]
  PIN select_fault[4]
    DIRECTION INPUT ;
    USE SIGNAL ;
    PORT
      LAYER M4 ;
        RECT  103.596 24.336 103.68 24.36 ;
    END
  END select_fault[4]
  PIN select_fault[5]
    DIRECTION INPUT ;
    USE SIGNAL ;
    PORT
      LAYER M4 ;
        RECT  103.596 25.728 103.68 25.752 ;
    END
  END select_fault[5]
  PIN select_fault[6]
    DIRECTION INPUT ;
    USE SIGNAL ;
    PORT
      LAYER M4 ;
        RECT  103.596 27.168 103.68 27.192 ;
    END
  END select_fault[6]
  PIN select_fault[7]
    DIRECTION INPUT ;
    USE SIGNAL ;
    PORT
      LAYER M4 ;
        RECT  103.596 28.56 103.68 28.584 ;
    END
  END select_fault[7]
  PIN select_fault[8]
    DIRECTION INPUT ;
    USE SIGNAL ;
    PORT
      LAYER M4 ;
        RECT  103.596 29.952 103.68 29.976 ;
    END
  END select_fault[8]
  PIN select_fault[9]
    DIRECTION INPUT ;
    USE SIGNAL ;
    PORT
      LAYER M4 ;
        RECT  103.596 31.392 103.68 31.416 ;
    END
  END select_fault[9]
  PIN tkm_fault
    DIRECTION INPUT ;
    USE SIGNAL ;
    PORT
      LAYER M4 ;
        RECT  103.596 44.112 103.68 44.136 ;
    END
  END tkm_fault
  PIN unavailable_fault[0]
    DIRECTION INPUT ;
    USE SIGNAL ;
    PORT
      LAYER M4 ;
        RECT  103.596 45.504 103.68 45.528 ;
    END
  END unavailable_fault[0]
  PIN unavailable_fault[10]
    DIRECTION INPUT ;
    USE SIGNAL ;
    PORT
      LAYER M4 ;
        RECT  103.596 59.664 103.68 59.688 ;
    END
  END unavailable_fault[10]
  PIN unavailable_fault[11]
    DIRECTION INPUT ;
    USE SIGNAL ;
    PORT
      LAYER M4 ;
        RECT  103.596 61.056 103.68 61.08 ;
    END
  END unavailable_fault[11]
  PIN unavailable_fault[12]
    DIRECTION INPUT ;
    USE SIGNAL ;
    PORT
      LAYER M4 ;
        RECT  103.596 62.496 103.68 62.52 ;
    END
  END unavailable_fault[12]
  PIN unavailable_fault[13]
    DIRECTION INPUT ;
    USE SIGNAL ;
    PORT
      LAYER M4 ;
        RECT  103.596 63.888 103.68 63.912 ;
    END
  END unavailable_fault[13]
  PIN unavailable_fault[14]
    DIRECTION INPUT ;
    USE SIGNAL ;
    PORT
      LAYER M4 ;
        RECT  103.596 65.328 103.68 65.352 ;
    END
  END unavailable_fault[14]
  PIN unavailable_fault[15]
    DIRECTION INPUT ;
    USE SIGNAL ;
    PORT
      LAYER M4 ;
        RECT  103.596 66.72 103.68 66.744 ;
    END
  END unavailable_fault[15]
  PIN unavailable_fault[16]
    DIRECTION INPUT ;
    USE SIGNAL ;
    PORT
      LAYER M4 ;
        RECT  103.596 68.16 103.68 68.184 ;
    END
  END unavailable_fault[16]
  PIN unavailable_fault[17]
    DIRECTION INPUT ;
    USE SIGNAL ;
    PORT
      LAYER M4 ;
        RECT  103.596 69.552 103.68 69.576 ;
    END
  END unavailable_fault[17]
  PIN unavailable_fault[1]
    DIRECTION INPUT ;
    USE SIGNAL ;
    PORT
      LAYER M4 ;
        RECT  103.596 46.944 103.68 46.968 ;
    END
  END unavailable_fault[1]
  PIN unavailable_fault[2]
    DIRECTION INPUT ;
    USE SIGNAL ;
    PORT
      LAYER M4 ;
        RECT  103.596 48.336 103.68 48.36 ;
    END
  END unavailable_fault[2]
  PIN unavailable_fault[3]
    DIRECTION INPUT ;
    USE SIGNAL ;
    PORT
      LAYER M4 ;
        RECT  103.596 49.776 103.68 49.8 ;
    END
  END unavailable_fault[3]
  PIN unavailable_fault[4]
    DIRECTION INPUT ;
    USE SIGNAL ;
    PORT
      LAYER M4 ;
        RECT  103.596 51.168 103.68 51.192 ;
    END
  END unavailable_fault[4]
  PIN unavailable_fault[5]
    DIRECTION INPUT ;
    USE SIGNAL ;
    PORT
      LAYER M4 ;
        RECT  103.596 52.608 103.68 52.632 ;
    END
  END unavailable_fault[5]
  PIN unavailable_fault[6]
    DIRECTION INPUT ;
    USE SIGNAL ;
    PORT
      LAYER M4 ;
        RECT  103.596 54 103.68 54.024 ;
    END
  END unavailable_fault[6]
  PIN unavailable_fault[7]
    DIRECTION INPUT ;
    USE SIGNAL ;
    PORT
      LAYER M4 ;
        RECT  103.596 55.44 103.68 55.464 ;
    END
  END unavailable_fault[7]
  PIN unavailable_fault[8]
    DIRECTION INPUT ;
    USE SIGNAL ;
    PORT
      LAYER M4 ;
        RECT  103.596 56.832 103.68 56.856 ;
    END
  END unavailable_fault[8]
  PIN unavailable_fault[9]
    DIRECTION INPUT ;
    USE SIGNAL ;
    PORT
      LAYER M4 ;
        RECT  103.596 58.272 103.68 58.296 ;
    END
  END unavailable_fault[9]
  PIN writer_fault
    DIRECTION INPUT ;
    USE SIGNAL ;
    PORT
      LAYER M4 ;
        RECT  0 63.36 0.084 63.384 ;
    END
  END writer_fault
  PIN VDD
    DIRECTION INOUT ;
    USE POWER ;
    PORT
      LAYER M5 ;
        RECT  99.792 2.151 99.912 69.129 ;
        RECT  94.392 2.151 94.512 69.129 ;
        RECT  88.992 2.151 89.112 69.129 ;
        RECT  83.592 2.151 83.712 69.129 ;
        RECT  78.192 2.151 78.312 69.129 ;
        RECT  72.792 2.151 72.912 69.129 ;
        RECT  67.392 2.151 67.512 69.129 ;
        RECT  61.992 2.151 62.112 69.129 ;
        RECT  56.592 2.151 56.712 69.129 ;
        RECT  51.192 2.151 51.312 69.129 ;
        RECT  45.792 2.151 45.912 69.129 ;
        RECT  40.392 2.151 40.512 69.129 ;
        RECT  34.992 2.151 35.112 69.129 ;
        RECT  29.592 2.151 29.712 69.129 ;
        RECT  24.192 2.151 24.312 69.129 ;
        RECT  18.792 2.151 18.912 69.129 ;
        RECT  13.392 2.151 13.512 69.129 ;
        RECT  7.992 2.151 8.112 69.129 ;
        RECT  2.592 2.151 2.712 69.129 ;
    END
  END VDD
  PIN VSS
    DIRECTION INOUT ;
    USE GROUND ;
    PORT
      LAYER M5 ;
        RECT  99.6 2.137 99.72 69.143 ;
        RECT  94.2 2.137 94.32 69.143 ;
        RECT  88.8 2.137 88.92 69.143 ;
        RECT  83.4 2.137 83.52 69.143 ;
        RECT  78 2.137 78.12 69.129 ;
        RECT  72.6 2.137 72.72 69.129 ;
        RECT  67.2 2.137 67.32 69.129 ;
        RECT  61.8 2.137 61.92 69.129 ;
        RECT  56.4 2.137 56.52 69.129 ;
        RECT  51 2.137 51.12 69.129 ;
        RECT  45.6 2.137 45.72 69.129 ;
        RECT  40.2 2.137 40.32 69.143 ;
        RECT  34.8 2.137 34.92 69.143 ;
        RECT  29.4 2.137 29.52 69.143 ;
        RECT  24 2.137 24.12 69.143 ;
        RECT  18.6 2.137 18.72 69.143 ;
        RECT  13.2 2.137 13.32 69.143 ;
        RECT  7.8 2.137 7.92 69.143 ;
        RECT  2.4 2.137 2.52 69.143 ;
    END
  END VSS
  OBS
    LAYER RVTN ;
     RECT  2.16 2.16 101.52 2.295 ;
     RECT  2.16 2.565 101.52 2.835 ;
     RECT  2.16 3.105 101.52 3.375 ;
     RECT  2.16 3.645 101.52 3.915 ;
     RECT  2.16 4.185 101.52 4.455 ;
     RECT  2.16 4.725 101.52 4.995 ;
     RECT  2.16 5.265 101.52 5.535 ;
     RECT  2.16 5.805 101.52 6.075 ;
     RECT  2.16 6.345 101.52 6.615 ;
     RECT  2.16 6.885 101.52 7.155 ;
     RECT  2.16 7.425 101.52 7.695 ;
     RECT  2.16 7.965 101.52 8.235 ;
     RECT  2.16 8.505 101.52 8.775 ;
     RECT  2.16 9.045 101.52 9.315 ;
     RECT  2.16 9.585 101.52 9.855 ;
     RECT  2.16 10.125 101.52 10.395 ;
     RECT  2.16 10.665 101.52 10.935 ;
     RECT  2.16 11.205 101.52 11.475 ;
     RECT  2.16 11.745 101.52 12.015 ;
     RECT  2.16 12.285 101.52 12.555 ;
     RECT  2.16 12.825 101.52 13.095 ;
     RECT  2.16 13.365 101.52 13.635 ;
     RECT  2.16 13.905 101.52 14.175 ;
     RECT  2.16 14.445 101.52 14.715 ;
     RECT  2.16 14.985 101.52 15.255 ;
     RECT  2.16 15.525 101.52 15.795 ;
     RECT  2.16 16.065 101.52 16.335 ;
     RECT  2.16 16.605 101.52 16.875 ;
     RECT  2.16 17.145 101.52 17.415 ;
     RECT  2.16 17.685 101.52 17.955 ;
     RECT  2.16 18.225 101.52 18.495 ;
     RECT  2.16 18.765 101.52 19.035 ;
     RECT  2.16 19.305 101.52 19.575 ;
     RECT  2.16 19.845 101.52 20.115 ;
     RECT  2.16 20.385 101.52 20.655 ;
     RECT  2.16 20.925 101.52 21.195 ;
     RECT  2.16 21.465 101.52 21.735 ;
     RECT  2.16 22.005 101.52 22.275 ;
     RECT  2.16 22.545 101.52 22.815 ;
     RECT  2.16 23.085 101.52 23.355 ;
     RECT  2.16 23.625 101.52 23.895 ;
     RECT  2.16 24.165 101.52 24.435 ;
     RECT  2.16 24.705 101.52 24.975 ;
     RECT  2.16 25.245 101.52 25.515 ;
     RECT  2.16 25.785 101.52 26.055 ;
     RECT  2.16 26.325 101.52 26.595 ;
     RECT  2.16 26.865 101.52 27.135 ;
     RECT  2.16 27.405 101.52 27.675 ;
     RECT  2.16 27.945 101.52 28.215 ;
     RECT  2.16 28.485 101.52 28.755 ;
     RECT  2.16 29.025 101.52 29.295 ;
     RECT  2.16 29.565 101.52 29.835 ;
     RECT  2.16 30.105 101.52 30.375 ;
     RECT  2.16 30.645 101.52 30.915 ;
     RECT  2.16 31.185 101.52 31.455 ;
     RECT  2.16 31.725 101.52 31.995 ;
     RECT  2.16 32.265 101.52 32.535 ;
     RECT  2.16 32.805 101.52 33.075 ;
     RECT  2.16 33.345 101.52 33.615 ;
     RECT  2.16 33.885 101.52 34.155 ;
     RECT  2.16 34.425 101.52 34.695 ;
     RECT  2.16 34.965 101.52 35.235 ;
     RECT  2.16 35.505 101.52 35.775 ;
     RECT  2.16 36.045 101.52 36.315 ;
     RECT  2.16 36.585 101.52 36.855 ;
     RECT  2.16 37.125 101.52 37.395 ;
     RECT  2.16 37.665 101.52 37.935 ;
     RECT  2.16 38.205 101.52 38.475 ;
     RECT  2.16 38.745 101.52 39.015 ;
     RECT  2.16 39.285 101.52 39.555 ;
     RECT  2.16 39.825 101.52 40.095 ;
     RECT  2.16 40.365 101.52 40.635 ;
     RECT  2.16 40.905 101.52 41.04 ;
     RECT  2.16 41.04 41.148 41.175 ;
     RECT  83.052 41.04 101.52 41.175 ;
     RECT  2.16 41.445 41.148 41.715 ;
     RECT  83.052 41.445 101.52 41.715 ;
     RECT  2.16 41.985 41.148 42.255 ;
     RECT  83.052 41.985 101.52 42.255 ;
     RECT  2.16 42.525 41.148 42.795 ;
     RECT  83.052 42.525 101.52 42.795 ;
     RECT  2.16 43.065 41.148 43.335 ;
     RECT  83.052 43.065 101.52 43.335 ;
     RECT  2.16 43.605 41.148 43.875 ;
     RECT  83.052 43.605 101.52 43.875 ;
     RECT  2.16 44.145 41.148 44.415 ;
     RECT  83.052 44.145 101.52 44.415 ;
     RECT  2.16 44.685 41.148 44.955 ;
     RECT  83.052 44.685 101.52 44.955 ;
     RECT  2.16 45.225 41.148 45.495 ;
     RECT  83.052 45.225 101.52 45.495 ;
     RECT  2.16 45.765 41.148 46.035 ;
     RECT  83.052 45.765 101.52 46.035 ;
     RECT  2.16 46.305 41.148 46.575 ;
     RECT  83.052 46.305 101.52 46.575 ;
     RECT  2.16 46.845 41.148 47.115 ;
     RECT  83.052 46.845 101.52 47.115 ;
     RECT  2.16 47.385 41.148 47.655 ;
     RECT  83.052 47.385 101.52 47.655 ;
     RECT  2.16 47.925 41.148 48.195 ;
     RECT  83.052 47.925 101.52 48.195 ;
     RECT  2.16 48.465 41.148 48.735 ;
     RECT  83.052 48.465 101.52 48.735 ;
     RECT  2.16 49.005 41.148 49.275 ;
     RECT  83.052 49.005 101.52 49.275 ;
     RECT  2.16 49.545 41.148 49.815 ;
     RECT  83.052 49.545 101.52 49.815 ;
     RECT  2.16 50.085 41.148 50.355 ;
     RECT  83.052 50.085 101.52 50.355 ;
     RECT  2.16 50.625 41.148 50.895 ;
     RECT  83.052 50.625 101.52 50.895 ;
     RECT  2.16 51.165 41.148 51.435 ;
     RECT  83.052 51.165 101.52 51.435 ;
     RECT  2.16 51.705 41.148 51.975 ;
     RECT  83.052 51.705 101.52 51.975 ;
     RECT  2.16 52.245 41.148 52.515 ;
     RECT  83.052 52.245 101.52 52.515 ;
     RECT  2.16 52.785 41.148 53.055 ;
     RECT  83.052 52.785 101.52 53.055 ;
     RECT  2.16 53.325 41.148 53.595 ;
     RECT  83.052 53.325 101.52 53.595 ;
     RECT  2.16 53.865 41.148 54.135 ;
     RECT  83.052 53.865 101.52 54.135 ;
     RECT  2.16 54.405 41.148 54.675 ;
     RECT  83.052 54.405 101.52 54.675 ;
     RECT  2.16 54.945 41.148 55.215 ;
     RECT  83.052 54.945 101.52 55.215 ;
     RECT  2.16 55.485 41.148 55.755 ;
     RECT  83.052 55.485 101.52 55.755 ;
     RECT  2.16 56.025 41.148 56.295 ;
     RECT  83.052 56.025 101.52 56.295 ;
     RECT  2.16 56.565 41.148 56.835 ;
     RECT  83.052 56.565 101.52 56.835 ;
     RECT  2.16 57.105 41.148 57.375 ;
     RECT  83.052 57.105 101.52 57.375 ;
     RECT  2.16 57.645 41.148 57.915 ;
     RECT  83.052 57.645 101.52 57.915 ;
     RECT  2.16 58.185 41.148 58.455 ;
     RECT  83.052 58.185 101.52 58.455 ;
     RECT  2.16 58.725 41.148 58.995 ;
     RECT  83.052 58.725 101.52 58.995 ;
     RECT  2.16 59.265 41.148 59.535 ;
     RECT  83.052 59.265 101.52 59.535 ;
     RECT  2.16 59.805 41.148 60.075 ;
     RECT  83.052 59.805 101.52 60.075 ;
     RECT  2.16 60.345 41.148 60.615 ;
     RECT  83.052 60.345 101.52 60.615 ;
     RECT  2.16 60.885 41.148 61.155 ;
     RECT  83.052 60.885 101.52 61.155 ;
     RECT  2.16 61.425 41.148 61.695 ;
     RECT  83.052 61.425 101.52 61.695 ;
     RECT  2.16 61.965 41.148 62.235 ;
     RECT  83.052 61.965 101.52 62.235 ;
     RECT  2.16 62.505 41.148 62.775 ;
     RECT  83.052 62.505 101.52 62.775 ;
     RECT  2.16 63.045 41.148 63.315 ;
     RECT  83.052 63.045 101.52 63.315 ;
     RECT  2.16 63.585 41.148 63.855 ;
     RECT  83.052 63.585 101.52 63.855 ;
     RECT  2.16 64.125 41.148 64.395 ;
     RECT  83.052 64.125 101.52 64.395 ;
     RECT  2.16 64.665 41.148 64.935 ;
     RECT  83.052 64.665 101.52 64.935 ;
     RECT  2.16 65.205 41.148 65.475 ;
     RECT  83.052 65.205 101.52 65.475 ;
     RECT  2.16 65.745 41.148 66.015 ;
     RECT  83.052 65.745 101.52 66.015 ;
     RECT  2.16 66.285 41.148 66.555 ;
     RECT  83.052 66.285 101.52 66.555 ;
     RECT  2.16 66.825 41.148 67.095 ;
     RECT  83.052 66.825 101.52 67.095 ;
     RECT  2.16 67.365 41.148 67.635 ;
     RECT  83.052 67.365 101.52 67.635 ;
     RECT  2.16 67.905 41.148 68.175 ;
     RECT  83.052 67.905 101.52 68.175 ;
     RECT  2.16 68.445 41.148 68.715 ;
     RECT  83.052 68.445 101.52 68.715 ;
     RECT  2.16 68.985 41.148 69.12 ;
     RECT  83.052 68.985 101.52 69.12 ;
    LAYER RVTP ;
     RECT  2.16 2.295 101.52 2.565 ;
     RECT  2.16 2.835 101.52 3.105 ;
     RECT  2.16 3.375 101.52 3.645 ;
     RECT  2.16 3.915 101.52 4.185 ;
     RECT  2.16 4.455 101.52 4.725 ;
     RECT  2.16 4.995 101.52 5.265 ;
     RECT  2.16 5.535 101.52 5.805 ;
     RECT  2.16 6.075 101.52 6.345 ;
     RECT  2.16 6.615 101.52 6.885 ;
     RECT  2.16 7.155 101.52 7.425 ;
     RECT  2.16 7.695 101.52 7.965 ;
     RECT  2.16 8.235 101.52 8.505 ;
     RECT  2.16 8.775 101.52 9.045 ;
     RECT  2.16 9.315 101.52 9.585 ;
     RECT  2.16 9.855 101.52 10.125 ;
     RECT  2.16 10.395 101.52 10.665 ;
     RECT  2.16 10.935 101.52 11.205 ;
     RECT  2.16 11.475 101.52 11.745 ;
     RECT  2.16 12.015 101.52 12.285 ;
     RECT  2.16 12.555 101.52 12.825 ;
     RECT  2.16 13.095 101.52 13.365 ;
     RECT  2.16 13.635 101.52 13.905 ;
     RECT  2.16 14.175 101.52 14.445 ;
     RECT  2.16 14.715 101.52 14.985 ;
     RECT  2.16 15.255 101.52 15.525 ;
     RECT  2.16 15.795 101.52 16.065 ;
     RECT  2.16 16.335 101.52 16.605 ;
     RECT  2.16 16.875 101.52 17.145 ;
     RECT  2.16 17.415 101.52 17.685 ;
     RECT  2.16 17.955 101.52 18.225 ;
     RECT  2.16 18.495 101.52 18.765 ;
     RECT  2.16 19.035 101.52 19.305 ;
     RECT  2.16 19.575 101.52 19.845 ;
     RECT  2.16 20.115 101.52 20.385 ;
     RECT  2.16 20.655 101.52 20.925 ;
     RECT  2.16 21.195 101.52 21.465 ;
     RECT  2.16 21.735 101.52 22.005 ;
     RECT  2.16 22.275 101.52 22.545 ;
     RECT  2.16 22.815 101.52 23.085 ;
     RECT  2.16 23.355 101.52 23.625 ;
     RECT  2.16 23.895 101.52 24.165 ;
     RECT  2.16 24.435 101.52 24.705 ;
     RECT  2.16 24.975 101.52 25.245 ;
     RECT  2.16 25.515 101.52 25.785 ;
     RECT  2.16 26.055 101.52 26.325 ;
     RECT  2.16 26.595 101.52 26.865 ;
     RECT  2.16 27.135 101.52 27.405 ;
     RECT  2.16 27.675 101.52 27.945 ;
     RECT  2.16 28.215 101.52 28.485 ;
     RECT  2.16 28.755 101.52 29.025 ;
     RECT  2.16 29.295 101.52 29.565 ;
     RECT  2.16 29.835 101.52 30.105 ;
     RECT  2.16 30.375 101.52 30.645 ;
     RECT  2.16 30.915 101.52 31.185 ;
     RECT  2.16 31.455 101.52 31.725 ;
     RECT  2.16 31.995 101.52 32.265 ;
     RECT  2.16 32.535 101.52 32.805 ;
     RECT  2.16 33.075 101.52 33.345 ;
     RECT  2.16 33.615 101.52 33.885 ;
     RECT  2.16 34.155 101.52 34.425 ;
     RECT  2.16 34.695 101.52 34.965 ;
     RECT  2.16 35.235 101.52 35.505 ;
     RECT  2.16 35.775 101.52 36.045 ;
     RECT  2.16 36.315 101.52 36.585 ;
     RECT  2.16 36.855 101.52 37.125 ;
     RECT  2.16 37.395 101.52 37.665 ;
     RECT  2.16 37.935 101.52 38.205 ;
     RECT  2.16 38.475 101.52 38.745 ;
     RECT  2.16 39.015 101.52 39.285 ;
     RECT  2.16 39.555 101.52 39.825 ;
     RECT  2.16 40.095 101.52 40.365 ;
     RECT  2.16 40.635 101.52 40.905 ;
     RECT  2.16 41.175 41.148 41.445 ;
     RECT  83.052 41.175 101.52 41.445 ;
     RECT  2.16 41.715 41.148 41.985 ;
     RECT  83.052 41.715 101.52 41.985 ;
     RECT  2.16 42.255 41.148 42.525 ;
     RECT  83.052 42.255 101.52 42.525 ;
     RECT  2.16 42.795 41.148 43.065 ;
     RECT  83.052 42.795 101.52 43.065 ;
     RECT  2.16 43.335 41.148 43.605 ;
     RECT  83.052 43.335 101.52 43.605 ;
     RECT  2.16 43.875 41.148 44.145 ;
     RECT  83.052 43.875 101.52 44.145 ;
     RECT  2.16 44.415 41.148 44.685 ;
     RECT  83.052 44.415 101.52 44.685 ;
     RECT  2.16 44.955 41.148 45.225 ;
     RECT  83.052 44.955 101.52 45.225 ;
     RECT  2.16 45.495 41.148 45.765 ;
     RECT  83.052 45.495 101.52 45.765 ;
     RECT  2.16 46.035 41.148 46.305 ;
     RECT  83.052 46.035 101.52 46.305 ;
     RECT  2.16 46.575 41.148 46.845 ;
     RECT  83.052 46.575 101.52 46.845 ;
     RECT  2.16 47.115 41.148 47.385 ;
     RECT  83.052 47.115 101.52 47.385 ;
     RECT  2.16 47.655 41.148 47.925 ;
     RECT  83.052 47.655 101.52 47.925 ;
     RECT  2.16 48.195 41.148 48.465 ;
     RECT  83.052 48.195 101.52 48.465 ;
     RECT  2.16 48.735 41.148 49.005 ;
     RECT  83.052 48.735 101.52 49.005 ;
     RECT  2.16 49.275 41.148 49.545 ;
     RECT  83.052 49.275 101.52 49.545 ;
     RECT  2.16 49.815 41.148 50.085 ;
     RECT  83.052 49.815 101.52 50.085 ;
     RECT  2.16 50.355 41.148 50.625 ;
     RECT  83.052 50.355 101.52 50.625 ;
     RECT  2.16 50.895 41.148 51.165 ;
     RECT  83.052 50.895 101.52 51.165 ;
     RECT  2.16 51.435 41.148 51.705 ;
     RECT  83.052 51.435 101.52 51.705 ;
     RECT  2.16 51.975 41.148 52.245 ;
     RECT  83.052 51.975 101.52 52.245 ;
     RECT  2.16 52.515 41.148 52.785 ;
     RECT  83.052 52.515 101.52 52.785 ;
     RECT  2.16 53.055 41.148 53.325 ;
     RECT  83.052 53.055 101.52 53.325 ;
     RECT  2.16 53.595 41.148 53.865 ;
     RECT  83.052 53.595 101.52 53.865 ;
     RECT  2.16 54.135 41.148 54.405 ;
     RECT  83.052 54.135 101.52 54.405 ;
     RECT  2.16 54.675 41.148 54.945 ;
     RECT  83.052 54.675 101.52 54.945 ;
     RECT  2.16 55.215 41.148 55.485 ;
     RECT  83.052 55.215 101.52 55.485 ;
     RECT  2.16 55.755 41.148 56.025 ;
     RECT  83.052 55.755 101.52 56.025 ;
     RECT  2.16 56.295 41.148 56.565 ;
     RECT  83.052 56.295 101.52 56.565 ;
     RECT  2.16 56.835 41.148 57.105 ;
     RECT  83.052 56.835 101.52 57.105 ;
     RECT  2.16 57.375 41.148 57.645 ;
     RECT  83.052 57.375 101.52 57.645 ;
     RECT  2.16 57.915 41.148 58.185 ;
     RECT  83.052 57.915 101.52 58.185 ;
     RECT  2.16 58.455 41.148 58.725 ;
     RECT  83.052 58.455 101.52 58.725 ;
     RECT  2.16 58.995 41.148 59.265 ;
     RECT  83.052 58.995 101.52 59.265 ;
     RECT  2.16 59.535 41.148 59.805 ;
     RECT  83.052 59.535 101.52 59.805 ;
     RECT  2.16 60.075 41.148 60.345 ;
     RECT  83.052 60.075 101.52 60.345 ;
     RECT  2.16 60.615 41.148 60.885 ;
     RECT  83.052 60.615 101.52 60.885 ;
     RECT  2.16 61.155 41.148 61.425 ;
     RECT  83.052 61.155 101.52 61.425 ;
     RECT  2.16 61.695 41.148 61.965 ;
     RECT  83.052 61.695 101.52 61.965 ;
     RECT  2.16 62.235 41.148 62.505 ;
     RECT  83.052 62.235 101.52 62.505 ;
     RECT  2.16 62.775 41.148 63.045 ;
     RECT  83.052 62.775 101.52 63.045 ;
     RECT  2.16 63.315 41.148 63.585 ;
     RECT  83.052 63.315 101.52 63.585 ;
     RECT  2.16 63.855 41.148 64.125 ;
     RECT  83.052 63.855 101.52 64.125 ;
     RECT  2.16 64.395 41.148 64.665 ;
     RECT  83.052 64.395 101.52 64.665 ;
     RECT  2.16 64.935 41.148 65.205 ;
     RECT  83.052 64.935 101.52 65.205 ;
     RECT  2.16 65.475 41.148 65.745 ;
     RECT  83.052 65.475 101.52 65.745 ;
     RECT  2.16 66.015 41.148 66.285 ;
     RECT  83.052 66.015 101.52 66.285 ;
     RECT  2.16 66.555 41.148 66.825 ;
     RECT  83.052 66.555 101.52 66.825 ;
     RECT  2.16 67.095 41.148 67.365 ;
     RECT  83.052 67.095 101.52 67.365 ;
     RECT  2.16 67.635 41.148 67.905 ;
     RECT  83.052 67.635 101.52 67.905 ;
     RECT  2.16 68.175 41.148 68.445 ;
     RECT  83.052 68.175 101.52 68.445 ;
     RECT  2.16 68.715 41.148 68.985 ;
     RECT  83.052 68.715 101.52 68.985 ;
    LAYER M1 ;
     RECT  2.16 2.151 101.52 41.049 ;
     RECT  43.2 43.2 81 66.984 ;
     RECT  2.16 41.049 41.148 69.129 ;
     RECT  83.052 41.049 101.52 69.129 ;
    LAYER M2 ;
     RECT  1.363 3.042 1.615 3.06 ;
     RECT  1.615 3.042 2.16 3.6 ;
     RECT  1.111 4.392 2.16 4.41 ;
     RECT  0.103 21.78 2.16 21.798 ;
     RECT  0.103 35.712 2.16 35.73 ;
     RECT  0.535 49.482 2.16 49.5 ;
     RECT  1.723 63.252 2.16 63.27 ;
     RECT  2.16 2.151 5.719 69.129 ;
     RECT  5.719 1.728 5.891 69.129 ;
     RECT  8.023 0.036 8.195 0.054 ;
     RECT  5.891 2.151 11.443 69.129 ;
     RECT  11.443 2.106 13.099 69.129 ;
     RECT  13.099 2.034 19.507 69.129 ;
     RECT  19.507 1.728 19.823 69.129 ;
     RECT  19.255 0.036 20.039 0.054 ;
     RECT  19.823 2.034 21.371 69.129 ;
     RECT  23.971 0.036 24.143 0.054 ;
     RECT  21.371 2.106 25.267 69.129 ;
     RECT  25.267 2.07 25.547 69.129 ;
     RECT  25.547 2.106 25.871 69.129 ;
     RECT  25.871 2.151 29.083 69.129 ;
     RECT  29.083 2.106 30.055 69.129 ;
     RECT  30.055 2.07 30.551 69.129 ;
     RECT  33.799 1.152 33.899 1.17 ;
     RECT  34.771 0.036 34.871 0.054 ;
     RECT  37.651 0.036 37.751 0.054 ;
     RECT  30.551 2.106 39.955 69.129 ;
     RECT  39.955 1.728 40.127 69.129 ;
     RECT  40.135 0.036 40.235 0.054 ;
     RECT  40.127 2.106 41.148 69.129 ;
     RECT  41.148 49.32 41.603 53.352 ;
     RECT  41.148 54.576 41.603 61.65 ;
     RECT  41.148 62.406 41.603 66.204 ;
     RECT  41.603 54.576 41.639 56.358 ;
     RECT  41.603 57.186 41.639 61.344 ;
     RECT  41.603 51.876 41.675 53.352 ;
     RECT  41.148 2.106 41.719 41.049 ;
     RECT  41.639 60.858 41.783 61.344 ;
     RECT  41.719 1.728 41.855 41.049 ;
     RECT  41.783 60.93 41.855 61.344 ;
     RECT  41.855 61.236 42.143 61.344 ;
     RECT  41.603 65.25 42.143 66.204 ;
     RECT  41.603 49.32 42.179 50.886 ;
     RECT  41.675 52.416 42.179 53.352 ;
     RECT  41.639 54.954 42.179 56.358 ;
     RECT  41.639 57.186 42.179 59.49 ;
     RECT  42.143 61.326 42.179 61.344 ;
     RECT  41.603 62.406 42.179 64.386 ;
     RECT  42.143 65.412 42.179 66.204 ;
     RECT  41.148 41.886 42.215 43.866 ;
     RECT  41.148 45.306 42.215 45.324 ;
     RECT  42.179 52.416 42.215 53.28 ;
     RECT  42.179 54.954 42.215 54.972 ;
     RECT  42.179 55.8 42.215 56.358 ;
     RECT  42.179 64.368 42.251 64.386 ;
     RECT  42.215 41.886 42.287 43.794 ;
     RECT  42.179 57.186 42.727 57.204 ;
     RECT  41.855 2.106 43.123 41.049 ;
     RECT  42.287 41.886 43.123 42.75 ;
     RECT  43.123 2.106 43.2 42.75 ;
     RECT  42.287 43.776 43.2 43.794 ;
     RECT  42.179 50.796 43.2 50.886 ;
     RECT  42.215 52.722 43.2 53.28 ;
     RECT  42.215 55.962 43.2 56.124 ;
     RECT  42.727 57.006 43.2 57.204 ;
     RECT  42.179 57.996 43.2 59.49 ;
     RECT  42.179 62.478 43.2 63.504 ;
     RECT  42.179 65.952 43.2 65.97 ;
     RECT  43.2 2.106 43.691 66.984 ;
     RECT  43.691 2.106 47.659 41.049 ;
     RECT  47.659 2.07 48.731 41.049 ;
     RECT  50.791 0.036 50.963 0.054 ;
     RECT  48.731 2.106 53.671 41.049 ;
     RECT  53.671 1.728 54.023 41.049 ;
     RECT  55.363 0.036 55.571 0.054 ;
     RECT  54.023 2.151 66.055 41.049 ;
     RECT  66.055 2.106 66.983 41.049 ;
     RECT  67.279 0.036 67.379 0.054 ;
     RECT  66.983 2.151 69.331 41.049 ;
     RECT  69.331 1.728 69.503 41.049 ;
     RECT  70.519 0.036 70.619 0.054 ;
     RECT  72.643 0.036 72.779 0.054 ;
     RECT  74.335 0.036 74.471 0.054 ;
     RECT  69.503 2.151 75.163 41.049 ;
     RECT  75.163 2.106 76.091 41.049 ;
     RECT  76.963 1.152 77.063 1.17 ;
     RECT  76.963 0.036 79.051 0.054 ;
     RECT  76.091 2.151 79.663 41.049 ;
     RECT  79.051 0.036 80.347 0.09 ;
     RECT  43.691 41.886 81 66.984 ;
     RECT  79.663 2.106 83.052 41.049 ;
     RECT  81 41.886 83.052 42.516 ;
     RECT  82.651 44.352 83.052 44.37 ;
     RECT  82.651 46.746 83.052 46.764 ;
     RECT  82.651 48.132 83.052 48.15 ;
     RECT  82.651 63.522 83.052 63.54 ;
     RECT  82.651 65.142 83.052 65.7 ;
     RECT  80.347 0.036 83.147 0.279 ;
     RECT  83.147 0.144 83.399 0.279 ;
     RECT  83.399 0.216 83.651 0.279 ;
     RECT  83.651 0.261 83.903 0.279 ;
     RECT  83.052 2.106 84.371 69.129 ;
     RECT  84.775 0.576 84.947 0.594 ;
     RECT  84.371 2.151 85.711 69.129 ;
     RECT  85.099 0.036 85.855 0.054 ;
     RECT  85.351 0.846 85.855 0.864 ;
     RECT  85.855 0.036 85.955 0.864 ;
     RECT  85.955 0.036 86.747 0.054 ;
     RECT  85.711 2.106 87.035 69.129 ;
     RECT  87.035 2.151 87.835 69.129 ;
     RECT  87.835 2.106 88.159 69.129 ;
     RECT  85.955 0.846 88.511 0.864 ;
     RECT  87.907 0.036 88.555 0.054 ;
     RECT  88.555 0.036 89.167 0.09 ;
     RECT  89.167 0.036 89.267 0.162 ;
     RECT  89.267 0.036 90.059 0.126 ;
     RECT  90.059 0.036 90.167 0.09 ;
     RECT  90.167 0.036 90.311 0.054 ;
     RECT  88.159 2.034 90.887 69.129 ;
     RECT  90.887 2.106 91.751 69.129 ;
     RECT  94.351 1.152 94.847 1.17 ;
     RECT  91.751 2.151 98.743 69.129 ;
     RECT  98.743 2.106 99.175 69.129 ;
     RECT  99.175 1.728 99.491 69.129 ;
     RECT  98.779 0.108 99.571 0.126 ;
     RECT  99.491 2.106 100.247 69.129 ;
     RECT  99.571 0.036 100.535 0.126 ;
     RECT  100.247 2.151 101.52 69.129 ;
     RECT  101.52 2.268 101.543 3.33 ;
     RECT  100.535 0.108 101.795 0.126 ;
     RECT  101.52 8.28 101.939 9.036 ;
     RECT  101.52 11.718 101.939 11.736 ;
     RECT  101.52 13.068 101.939 13.086 ;
     RECT  101.52 37.098 101.939 37.116 ;
     RECT  101.52 54.108 101.939 54.126 ;
     RECT  101.52 61.128 101.939 61.146 ;
     RECT  101.52 66.798 101.939 66.816 ;
     RECT  101.52 6.048 102.011 6.336 ;
     RECT  101.52 20.088 102.011 20.106 ;
     RECT  101.52 31.428 102.011 31.446 ;
     RECT  101.52 32.778 102.011 32.796 ;
     RECT  101.52 34.362 102.011 34.38 ;
     RECT  101.52 38.448 102.011 38.466 ;
     RECT  101.52 40.032 102.011 40.05 ;
     RECT  101.52 49.752 102.011 49.77 ;
     RECT  101.52 55.422 102.011 55.44 ;
     RECT  101.52 62.514 102.011 62.532 ;
     RECT  101.52 65.412 102.011 65.43 ;
     RECT  101.52 4.536 102.047 5.256 ;
     RECT  101.52 10.17 102.047 10.188 ;
     RECT  101.52 16.11 102.047 16.128 ;
     RECT  101.52 22.788 102.047 22.806 ;
     RECT  101.543 3.078 102.299 3.33 ;
     RECT  101.543 2.268 102.515 2.286 ;
     RECT  102.299 3.078 102.551 3.096 ;
     RECT  101.52 17.352 102.587 17.37 ;
     RECT  101.52 18.702 102.587 18.72 ;
     RECT  101.52 21.672 102.587 21.69 ;
     RECT  101.52 24.372 102.587 24.39 ;
     RECT  101.52 25.722 102.587 25.74 ;
     RECT  101.52 27.342 102.587 27.36 ;
     RECT  101.52 30.042 102.587 30.06 ;
     RECT  101.52 35.712 102.587 35.73 ;
     RECT  101.52 41.382 102.587 41.4 ;
     RECT  101.52 42.732 102.587 42.75 ;
     RECT  101.52 45.702 102.587 45.72 ;
     RECT  101.52 51.372 102.587 51.39 ;
     RECT  101.52 52.452 102.587 52.47 ;
     RECT  101.52 56.772 102.587 56.79 ;
     RECT  101.52 58.122 102.587 58.14 ;
     RECT  101.52 59.742 102.587 59.76 ;
     RECT  101.52 63.828 102.587 63.846 ;
     RECT  101.52 28.458 102.623 28.476 ;
     RECT  102.047 5.238 103.559 5.256 ;
     RECT  102.011 6.318 103.595 6.336 ;
     RECT  101.939 8.28 103.595 8.298 ;
    LAYER M3 ;
     RECT  82.872 0.012 90.81 0.058 ;
     RECT  97.956 0.091 98.478 0.103 ;
     RECT  99.216 0.012 102.546 0.103 ;
     RECT  95.976 0.091 95.994 0.139 ;
     RECT  96.912 0.091 96.93 0.139 ;
     RECT  97.956 0.103 102.546 0.139 ;
     RECT  82.836 0.058 90.81 0.167 ;
     RECT  80.856 0.091 80.874 0.256 ;
     RECT  83.052 0.167 90.81 0.284 ;
     RECT  84.132 0.284 90.81 0.523 ;
     RECT  91.656 0.091 91.674 0.523 ;
     RECT  62.604 0.139 62.622 0.571 ;
     RECT  66.528 0.012 74.466 0.571 ;
     RECT  76.968 0.031 76.986 0.571 ;
     RECT  92.448 0.523 92.466 0.571 ;
     RECT  94.896 0.091 94.914 0.571 ;
     RECT  95.976 0.139 102.546 0.571 ;
     RECT  66.528 0.571 74.61 0.619 ;
     RECT  93.42 0.091 93.438 0.667 ;
     RECT  93.42 0.667 93.834 1.099 ;
     RECT  94.68 0.571 102.546 1.099 ;
     RECT  17.46 0.012 25.398 1.147 ;
     RECT  29.592 0.091 29.61 1.147 ;
     RECT  31.068 0.571 31.086 1.147 ;
     RECT  42.588 0.571 42.606 1.147 ;
     RECT  50.184 0.012 58.122 1.147 ;
     RECT  83.052 0.284 83.394 1.147 ;
     RECT  84.132 0.523 91.674 1.147 ;
     RECT  92.448 0.571 92.538 1.147 ;
     RECT  48.312 1.147 48.33 1.195 ;
     RECT  63.432 0.091 63.45 1.675 ;
     RECT  1.116 0.012 9.054 1.723 ;
     RECT  10.764 0.571 10.782 1.723 ;
     RECT  11.988 1.627 12.006 1.723 ;
     RECT  14.184 1.147 14.202 1.723 ;
     RECT  17.46 1.147 25.794 1.723 ;
     RECT  28.764 1.147 28.782 1.723 ;
     RECT  29.592 1.147 29.862 1.723 ;
     RECT  31.068 1.147 31.482 1.723 ;
     RECT  32.76 1.147 32.778 1.723 ;
     RECT  33.804 0.012 41.742 1.723 ;
     RECT  42.588 1.147 42.822 1.723 ;
     RECT  43.812 0.571 44.37 1.723 ;
     RECT  48.204 1.195 48.33 1.723 ;
     RECT  50.184 1.147 58.734 1.723 ;
     RECT  61.956 0.571 62.622 1.723 ;
     RECT  63.432 1.675 63.594 1.723 ;
     RECT  65.628 1.147 65.646 1.723 ;
     RECT  66.528 0.619 75.15 1.723 ;
     RECT  76.212 0.571 77.49 1.723 ;
     RECT  79.056 0.067 79.074 1.723 ;
     RECT  80.352 0.256 80.874 1.723 ;
     RECT  82.692 1.147 83.394 1.723 ;
     RECT  13.896 1.723 14.202 1.771 ;
     RECT  15.084 1.723 31.482 1.771 ;
     RECT  32.58 1.723 80.874 1.819 ;
     RECT  81.612 1.723 83.394 1.819 ;
     RECT  12.816 1.723 13.158 2.011 ;
     RECT  13.896 1.771 31.482 2.011 ;
     RECT  32.58 1.819 83.394 2.143 ;
     RECT  84.132 1.147 92.538 2.143 ;
     RECT  12.816 2.011 31.482 2.191 ;
     RECT  32.58 2.143 92.538 2.191 ;
     RECT  93.42 1.099 102.546 2.191 ;
     RECT  1.116 1.723 12.006 2.371 ;
     RECT  12.816 2.191 102.546 2.371 ;
     RECT  1.116 2.371 102.546 3.101 ;
     RECT  1.116 3.101 102.294 3.335 ;
     RECT  1.116 3.335 1.638 3.605 ;
     RECT  1.116 3.605 1.134 4.415 ;
     RECT  103.572 3.115 103.59 4.507 ;
     RECT  2.376 3.335 102.042 4.559 ;
     RECT  2.376 4.559 101.394 4.829 ;
     RECT  80.1 4.829 101.394 5.099 ;
     RECT  103.536 4.507 103.59 5.261 ;
     RECT  80.568 5.099 101.394 5.947 ;
     RECT  2.376 4.829 79.254 6.007 ;
     RECT  80.568 5.947 102.006 6.007 ;
     RECT  80.388 6.007 102.006 6.071 ;
     RECT  2.376 6.007 79.506 6.091 ;
     RECT  80.388 6.071 101.394 6.091 ;
     RECT  2.376 6.091 101.394 6.241 ;
     RECT  2.34 6.241 101.394 6.269 ;
     RECT  103.572 5.261 103.59 6.341 ;
     RECT  26.064 6.269 101.394 6.647 ;
     RECT  2.34 6.269 25.218 7.321 ;
     RECT  2.34 7.321 25.326 7.393 ;
     RECT  26.136 6.647 101.394 7.393 ;
     RECT  2.34 7.393 101.394 7.763 ;
     RECT  2.34 7.763 28.35 7.915 ;
     RECT  29.088 7.763 101.394 7.925 ;
     RECT  101.196 7.925 101.394 8.045 ;
     RECT  101.376 8.045 101.394 8.069 ;
     RECT  2.304 7.915 28.35 8.195 ;
     RECT  103.572 7.339 103.59 8.303 ;
     RECT  29.088 7.925 100.422 8.429 ;
     RECT  74.34 8.429 100.422 8.477 ;
     RECT  2.34 8.195 28.35 8.545 ;
     RECT  29.088 8.429 73.602 8.545 ;
     RECT  99.576 8.477 100.422 8.771 ;
     RECT  2.34 8.545 73.602 8.969 ;
     RECT  99.576 8.771 99.99 8.969 ;
     RECT  99.576 8.969 99.954 9.005 ;
     RECT  101.916 8.779 101.934 9.041 ;
     RECT  101.016 9.121 101.034 9.239 ;
     RECT  74.34 8.477 98.622 9.391 ;
     RECT  101.196 9.391 101.214 9.545 ;
     RECT  2.34 8.969 73.494 9.653 ;
     RECT  99.615 9.005 99.954 9.653 ;
     RECT  74.34 9.391 98.694 9.787 ;
     RECT  2.415 9.653 73.494 9.859 ;
     RECT  74.34 9.787 98.73 9.859 ;
     RECT  102.024 10.165 102.042 10.205 ;
     RECT  2.415 9.859 98.73 10.597 ;
     RECT  2.376 10.597 98.73 10.669 ;
     RECT  2.376 10.669 98.874 11.165 ;
     RECT  101.916 11.611 101.934 11.741 ;
     RECT  2.415 11.165 98.874 11.821 ;
     RECT  99.615 9.653 99.897 11.821 ;
     RECT  2.415 11.821 100.494 12.119 ;
     RECT  2.415 12.119 100.314 13.027 ;
     RECT  2.415 13.027 100.35 13.051 ;
     RECT  101.916 13.003 101.934 13.091 ;
     RECT  2.34 13.051 100.35 13.199 ;
     RECT  2.34 13.199 100.314 13.667 ;
     RECT  2.415 13.667 100.314 13.981 ;
     RECT  2.415 13.981 100.35 14.071 ;
     RECT  101.484 13.945 101.502 14.429 ;
     RECT  2.415 14.071 100.386 14.953 ;
     RECT  2.34 14.953 100.386 15.331 ;
     RECT  2.34 15.331 100.782 15.533 ;
     RECT  38.052 15.533 100.782 15.593 ;
     RECT  102.024 15.835 102.042 16.133 ;
     RECT  38.052 15.593 100.242 16.267 ;
     RECT  2.34 15.533 37.206 16.331 ;
     RECT  2.415 16.331 37.206 16.403 ;
     RECT  3.42 16.403 37.206 16.459 ;
     RECT  38.016 16.267 100.242 16.459 ;
     RECT  3.42 16.459 100.242 16.943 ;
     RECT  3.42 16.943 3.618 17.105 ;
     RECT  102.564 17.227 102.582 17.375 ;
     RECT  4.356 16.943 100.242 17.491 ;
     RECT  3.492 17.105 3.618 17.887 ;
     RECT  4.356 17.491 100.782 17.887 ;
     RECT  3.492 17.887 100.782 17.995 ;
     RECT  3.492 17.995 101.394 18.185 ;
     RECT  4.356 18.185 100.422 18.419 ;
     RECT  101.376 18.185 101.394 18.419 ;
     RECT  4.464 18.419 100.422 18.563 ;
     RECT  102.564 18.667 102.582 18.725 ;
     RECT  4.5 18.563 100.422 18.761 ;
     RECT  3.492 18.185 3.618 18.833 ;
     RECT  4.5 18.761 47.322 19.543 ;
     RECT  48.06 18.761 100.422 19.543 ;
     RECT  4.5 19.543 100.422 19.579 ;
     RECT  101.196 19.111 101.214 19.579 ;
     RECT  4.5 19.579 101.214 19.651 ;
     RECT  4.428 19.651 101.394 19.769 ;
     RECT  101.988 20.059 102.006 20.111 ;
     RECT  3.564 18.833 3.618 20.731 ;
     RECT  4.428 19.769 100.71 20.731 ;
     RECT  3.564 20.731 101.286 20.993 ;
     RECT  2.415 16.403 2.697 21.631 ;
     RECT  3.564 20.993 100.782 21.631 ;
     RECT  102.564 21.499 102.582 21.695 ;
     RECT  0.108 21.775 0.126 21.821 ;
     RECT  2.415 21.631 100.782 22.207 ;
     RECT  2.415 22.207 100.962 22.469 ;
     RECT  2.415 22.469 100.89 22.613 ;
     RECT  102.024 22.783 102.042 22.925 ;
     RECT  82.728 22.613 100.89 23.351 ;
     RECT  2.415 22.613 81.882 23.512 ;
     RECT  82.728 23.351 100.314 23.512 ;
     RECT  2.415 23.512 100.314 23.665 ;
     RECT  2.34 23.665 100.314 23.891 ;
     RECT  60.444 23.891 100.314 24.169 ;
     RECT  60.444 24.169 100.566 24.359 ;
     RECT  102.564 24.331 102.582 24.395 ;
     RECT  2.34 23.891 59.562 24.509 ;
     RECT  2.415 24.509 59.562 24.781 ;
     RECT  60.444 24.359 100.242 24.781 ;
     RECT  2.415 24.781 100.242 24.899 ;
     RECT  2.415 24.899 100.206 25.007 ;
     RECT  101.16 24.781 101.178 25.043 ;
     RECT  102.564 25.717 102.582 25.757 ;
     RECT  2.415 25.007 100.17 25.771 ;
     RECT  2.415 25.771 100.422 26.555 ;
     RECT  60.12 26.555 100.422 26.941 ;
     RECT  2.415 26.555 59.382 27.329 ;
     RECT  60.12 26.941 100.782 27.329 ;
     RECT  3.528 27.329 59.382 27.337 ;
     RECT  60.12 27.329 100.566 27.337 ;
     RECT  102.564 27.163 102.582 27.365 ;
     RECT  3.528 27.337 100.566 27.941 ;
     RECT  2.415 27.329 2.79 28.291 ;
     RECT  3.528 27.941 5.598 28.291 ;
     RECT  6.336 27.941 100.566 28.409 ;
     RECT  6.336 28.409 100.386 28.481 ;
     RECT  101.448 28.453 101.466 28.553 ;
     RECT  102.6 28.453 102.618 28.589 ;
     RECT  2.415 28.291 5.598 28.921 ;
     RECT  6.336 28.481 100.314 28.921 ;
     RECT  2.415 28.921 100.314 30.065 ;
     RECT  102.564 29.947 102.582 30.065 ;
     RECT  52.2 30.065 100.314 30.299 ;
     RECT  52.2 30.299 86.886 30.335 ;
     RECT  87.624 30.299 100.098 30.335 ;
     RECT  52.2 30.335 59.382 30.811 ;
     RECT  2.415 30.065 51.354 30.859 ;
     RECT  52.128 30.811 59.382 30.859 ;
     RECT  2.415 30.859 59.382 30.893 ;
     RECT  3.6 30.893 59.382 31.145 ;
     RECT  60.444 30.335 86.886 31.189 ;
     RECT  4.14 31.145 59.382 31.225 ;
     RECT  60.408 31.189 86.886 31.225 ;
     RECT  4.14 31.225 86.886 31.415 ;
     RECT  101.988 31.387 102.006 31.451 ;
     RECT  4.212 31.415 86.886 31.495 ;
     RECT  87.912 30.335 100.098 31.495 ;
     RECT  101.196 31.531 101.214 31.757 ;
     RECT  4.212 31.495 100.098 31.955 ;
     RECT  92.484 31.955 100.098 32.071 ;
     RECT  4.212 31.955 91.602 32.189 ;
     RECT  4.212 32.189 90.99 32.333 ;
     RECT  92.484 32.071 100.602 32.333 ;
     RECT  92.484 32.333 93.042 32.369 ;
     RECT  4.212 32.333 90.63 32.459 ;
     RECT  93.78 32.333 100.602 32.603 ;
     RECT  96.624 32.603 100.602 32.611 ;
     RECT  4.212 32.459 58.302 32.621 ;
     RECT  93.024 32.369 93.042 32.639 ;
     RECT  59.148 32.459 90.63 32.729 ;
     RECT  96.624 32.611 100.746 32.729 ;
     RECT  59.256 32.729 90.63 32.765 ;
     RECT  96.624 32.729 100.098 32.765 ;
     RECT  59.256 32.765 89.694 32.801 ;
     RECT  101.988 32.773 102.006 32.813 ;
     RECT  90.612 32.765 90.63 32.837 ;
     RECT  98.172 32.765 100.098 32.837 ;
     RECT  93.78 32.603 95.814 32.873 ;
     RECT  4.212 32.621 58.086 32.909 ;
     RECT  4.284 32.909 58.086 33.071 ;
     RECT  59.472 32.801 89.694 33.071 ;
     RECT  4.392 33.071 58.086 33.179 ;
     RECT  94.215 32.873 95.814 33.179 ;
     RECT  77.544 33.071 89.694 33.341 ;
     RECT  4.464 33.179 58.086 33.449 ;
     RECT  4.464 33.449 58.014 33.533 ;
     RECT  59.472 33.071 76.734 33.539 ;
     RECT  77.544 33.341 88.038 33.539 ;
     RECT  88.815 33.341 89.694 33.539 ;
     RECT  59.472 33.539 67.842 33.547 ;
     RECT  59.364 33.547 67.842 33.575 ;
     RECT  4.5 33.533 58.014 33.611 ;
     RECT  77.544 33.539 86.886 33.611 ;
     RECT  59.364 33.575 67.662 33.619 ;
     RECT  58.932 33.619 67.662 33.691 ;
     RECT  58.752 33.691 67.662 33.719 ;
     RECT  68.796 33.539 76.734 33.809 ;
     RECT  83.304 33.611 86.886 33.809 ;
     RECT  87.84 33.539 88.038 33.809 ;
     RECT  68.796 33.809 69.822 33.845 ;
     RECT  70.704 33.809 76.734 33.845 ;
     RECT  66.276 33.719 67.662 33.881 ;
     RECT  70.704 33.845 70.866 33.881 ;
     RECT  77.544 33.611 82.458 33.881 ;
     RECT  88.815 33.539 89.514 33.881 ;
     RECT  88.02 33.809 88.038 33.953 ;
     RECT  71.748 33.845 76.518 33.989 ;
     RECT  79.416 33.881 82.458 33.989 ;
     RECT  73.872 33.989 76.518 34.013 ;
     RECT  4.536 33.611 58.014 34.079 ;
     RECT  58.752 33.719 65.358 34.079 ;
     RECT  66.276 33.881 67.626 34.079 ;
     RECT  69.48 33.845 69.822 34.079 ;
     RECT  71.748 33.989 72.897 34.079 ;
     RECT  74.592 34.013 76.518 34.079 ;
     RECT  77.544 33.881 78.57 34.079 ;
     RECT  79.416 33.989 80.622 34.079 ;
     RECT  58.752 34.079 65.25 34.115 ;
     RECT  66.276 34.079 67.554 34.115 ;
     RECT  69.804 34.079 69.822 34.115 ;
     RECT  71.748 34.079 71.766 34.115 ;
     RECT  74.592 34.079 74.61 34.115 ;
     RECT  77.544 34.079 78.462 34.115 ;
     RECT  66.816 34.115 67.554 34.151 ;
     RECT  96.624 32.765 97.398 34.159 ;
     RECT  70.704 33.881 70.794 34.187 ;
     RECT  75.384 34.079 76.518 34.187 ;
     RECT  81.468 33.989 82.458 34.187 ;
     RECT  4.536 34.079 5.706 34.349 ;
     RECT  66.816 34.151 67.497 34.349 ;
     RECT  75.888 34.187 76.266 34.349 ;
     RECT  80.1 34.079 80.622 34.349 ;
     RECT  4.536 34.349 4.878 34.355 ;
     RECT  75.888 34.349 75.906 34.385 ;
     RECT  80.1 34.349 80.514 34.385 ;
     RECT  101.988 34.219 102.006 34.385 ;
     RECT  94.215 33.179 95.202 34.429 ;
     RECT  98.568 32.837 100.098 34.429 ;
     RECT  6.444 34.079 58.014 34.465 ;
     RECT  58.752 34.115 65.07 34.465 ;
     RECT  6.444 34.465 65.07 34.493 ;
     RECT  96.264 34.159 97.398 34.501 ;
     RECT  98.532 34.429 100.098 34.529 ;
     RECT  5.688 34.349 5.706 34.619 ;
     RECT  96.12 34.501 97.398 34.619 ;
     RECT  6.444 34.493 64.746 34.655 ;
     RECT  80.1 34.385 80.442 34.655 ;
     RECT  80.1 34.655 80.118 34.727 ;
     RECT  94.215 34.429 95.346 34.735 ;
     RECT  96.12 34.619 97.362 34.735 ;
     RECT  94.215 34.735 97.362 34.763 ;
     RECT  95.904 34.763 97.362 34.889 ;
     RECT  6.444 34.655 64.566 34.925 ;
     RECT  4.86 34.355 4.878 34.997 ;
     RECT  6.444 34.925 63.918 34.997 ;
     RECT  67.104 34.349 67.497 35.069 ;
     RECT  82.656 34.939 82.674 35.069 ;
     RECT  6.444 34.997 63.414 35.159 ;
     RECT  81.468 34.187 81.882 35.195 ;
     RECT  6.444 35.159 62.982 35.267 ;
     RECT  83.415 33.809 86.886 35.323 ;
     RECT  83.415 35.323 87.462 35.419 ;
     RECT  6.444 35.267 62.097 35.429 ;
     RECT  62.964 35.267 62.982 35.429 ;
     RECT  98.568 34.529 100.098 35.545 ;
     RECT  98.568 35.545 100.314 35.573 ;
     RECT  98.748 35.573 100.314 35.581 ;
     RECT  6.444 35.429 60.894 35.699 ;
     RECT  83.415 35.419 87.498 35.699 ;
     RECT  98.748 35.581 100.782 35.699 ;
     RECT  0.108 35.611 0.126 35.735 ;
     RECT  60.876 35.699 60.894 35.735 ;
     RECT  102.564 35.611 102.582 35.735 ;
     RECT  6.444 35.699 60.138 35.771 ;
     RECT  6.84 35.771 60.138 35.843 ;
     RECT  6.84 35.843 59.742 36.239 ;
     RECT  6.84 36.239 59.022 36.347 ;
     RECT  58.464 36.347 59.022 36.383 ;
     RECT  58.464 36.383 58.482 36.509 ;
     RECT  6.84 36.347 57.474 36.617 ;
     RECT  54.216 36.617 57.294 36.779 ;
     RECT  54.216 36.779 57.222 36.815 ;
     RECT  96.264 34.889 97.362 36.931 ;
     RECT  6.84 36.617 53.442 37.049 ;
     RECT  96.264 36.931 97.578 37.049 ;
     RECT  98.748 35.699 100.098 37.057 ;
     RECT  9.036 37.049 13.806 37.085 ;
     RECT  54.216 36.815 55.494 37.085 ;
     RECT  9.036 37.085 13.734 37.121 ;
     RECT  54.216 37.085 55.278 37.121 ;
     RECT  101.916 37.051 101.934 37.121 ;
     RECT  9.036 37.121 13.662 37.193 ;
     RECT  6.84 37.049 8.298 37.319 ;
     RECT  54.396 37.121 55.278 37.319 ;
     RECT  54.396 37.319 55.134 37.427 ;
     RECT  14.616 37.049 53.442 37.435 ;
     RECT  54.396 37.427 54.954 37.499 ;
     RECT  56.268 36.815 57.222 37.499 ;
     RECT  54.396 37.499 54.414 37.589 ;
     RECT  56.415 37.499 57.222 37.589 ;
     RECT  9.036 37.193 13.554 37.661 ;
     RECT  14.616 37.435 53.55 37.895 ;
     RECT  14.616 37.895 53.154 37.967 ;
     RECT  7.416 37.319 8.298 38.011 ;
     RECT  9.036 37.661 9.45 38.011 ;
     RECT  96.264 37.049 97.362 38.011 ;
     RECT  98.172 37.057 100.098 38.011 ;
     RECT  14.616 37.967 53.118 38.039 ;
     RECT  96.264 38.011 100.098 38.101 ;
     RECT  10.26 37.661 13.554 38.129 ;
     RECT  14.616 38.039 46.674 38.129 ;
     RECT  47.484 38.039 53.118 38.201 ;
     RECT  10.26 38.129 12.438 38.399 ;
     RECT  47.484 38.201 53.082 38.399 ;
     RECT  96.264 38.101 100.818 38.399 ;
     RECT  11.16 38.399 12.438 38.435 ;
     RECT  13.215 38.129 13.554 38.435 ;
     RECT  14.724 38.129 46.674 38.435 ;
     RECT  101.988 38.443 102.006 38.48 ;
     RECT  14.724 38.435 18.897 38.507 ;
     RECT  26.748 38.435 46.674 38.543 ;
     RECT  7.416 38.011 9.45 38.551 ;
     RECT  18.432 38.507 18.897 38.579 ;
     RECT  14.832 38.507 17.154 38.669 ;
     RECT  20.088 38.435 25.758 38.669 ;
     RECT  38.16 38.543 46.674 38.669 ;
     RECT  96.264 38.399 100.098 38.669 ;
     RECT  38.196 38.669 46.674 38.675 ;
     RECT  7.416 38.551 9.99 38.705 ;
     RECT  98.64 38.669 100.098 38.705 ;
     RECT  7.416 38.705 8.298 38.741 ;
     RECT  26.748 38.543 37.386 38.741 ;
     RECT  11.232 38.435 12.438 38.765 ;
     RECT  20.088 38.669 20.358 38.765 ;
     RECT  11.232 38.765 12.402 38.813 ;
     RECT  26.748 38.741 36.45 38.813 ;
     RECT  39.348 38.675 46.674 38.821 ;
     RECT  47.484 38.399 52.686 38.821 ;
     RECT  9.108 38.705 9.99 38.849 ;
     RECT  9.936 38.849 9.99 38.939 ;
     RECT  11.7 38.813 12.366 38.939 ;
     RECT  14.832 38.669 16.902 38.939 ;
     RECT  21.096 38.669 25.758 38.939 ;
     RECT  39.348 38.821 52.686 38.975 ;
     RECT  52.632 38.975 52.686 39.011 ;
     RECT  39.348 38.975 51.678 39.047 ;
     RECT  9.936 38.939 9.954 39.083 ;
     RECT  12.024 38.939 12.366 39.083 ;
     RECT  52.632 39.011 52.65 39.083 ;
     RECT  15.732 38.939 16.902 39.119 ;
     RECT  20.16 38.765 20.358 39.119 ;
     RECT  21.096 38.939 22.518 39.119 ;
     RECT  23.58 38.939 25.722 39.119 ;
     RECT  12.06 39.083 12.366 39.209 ;
     RECT  15.732 39.119 15.894 39.209 ;
     RECT  21.096 39.119 21.222 39.209 ;
     RECT  23.688 39.119 25.722 39.209 ;
     RECT  26.748 38.813 31.626 39.209 ;
     RECT  39.348 39.047 49.662 39.209 ;
     RECT  51.015 39.047 51.678 39.209 ;
     RECT  15.732 39.209 15.75 39.245 ;
     RECT  21.096 39.209 21.114 39.245 ;
     RECT  23.688 39.209 24.462 39.245 ;
     RECT  51.015 39.209 51.354 39.245 ;
     RECT  7.416 38.741 8.097 39.317 ;
     RECT  14.832 38.939 14.85 39.317 ;
     RECT  16.884 39.119 16.902 39.317 ;
     RECT  25.38 39.209 25.722 39.317 ;
     RECT  26.748 39.209 30.582 39.341 ;
     RECT  28.764 39.341 30.582 39.389 ;
     RECT  25.38 39.317 25.614 39.479 ;
     RECT  26.748 39.341 27.774 39.479 ;
     RECT  37.296 38.741 37.386 39.487 ;
     RECT  38.196 38.675 38.538 39.487 ;
     RECT  25.38 39.479 25.398 39.515 ;
     RECT  26.748 39.479 27.63 39.515 ;
     RECT  31.356 39.209 31.626 39.515 ;
     RECT  37.296 39.487 38.538 39.547 ;
     RECT  39.348 39.209 48.654 39.547 ;
     RECT  26.856 39.515 27.63 39.581 ;
     RECT  26.856 39.581 27.522 39.587 ;
     RECT  32.508 38.813 36.45 39.631 ;
     RECT  37.296 39.547 48.654 39.721 ;
     RECT  32.508 39.631 36.486 39.749 ;
     RECT  37.224 39.721 48.654 39.821 ;
     RECT  32.508 39.749 32.526 39.893 ;
     RECT  37.224 39.821 47.862 39.893 ;
     RECT  33.588 39.749 36.486 39.901 ;
     RECT  37.224 39.893 37.386 39.901 ;
     RECT  103.572 39.883 103.59 40.013 ;
     RECT  33.588 39.901 37.386 40.019 ;
     RECT  38.196 39.893 47.862 40.019 ;
     RECT  28.764 39.389 30.474 40.055 ;
     RECT  38.196 40.019 47.826 40.055 ;
     RECT  101.988 39.979 102.006 40.055 ;
     RECT  33.588 40.019 36.162 40.091 ;
     RECT  38.7 40.055 47.826 40.091 ;
     RECT  96.264 38.669 97.362 40.099 ;
     RECT  98.64 38.705 98.874 40.099 ;
     RECT  28.764 40.055 30.294 40.127 ;
     RECT  38.7 40.091 46.782 40.127 ;
     RECT  33.588 40.091 35.694 40.163 ;
     RECT  99.615 38.705 100.098 40.171 ;
     RECT  34.128 40.163 35.694 40.199 ;
     RECT  38.7 40.127 44.694 40.199 ;
     RECT  37.224 40.019 37.386 40.289 ;
     RECT  38.7 40.199 39.474 40.289 ;
     RECT  45.468 40.127 46.782 40.289 ;
     RECT  98.172 40.099 98.874 40.289 ;
     RECT  95.652 40.099 97.362 40.297 ;
     RECT  37.368 40.289 37.386 40.325 ;
     RECT  40.215 40.199 44.694 40.325 ;
     RECT  95.508 40.297 97.362 40.325 ;
     RECT  45.468 40.289 45.897 40.349 ;
     RECT  95.508 40.325 95.526 40.349 ;
     RECT  40.215 40.325 44.442 40.361 ;
     RECT  40.215 40.361 43.686 40.397 ;
     RECT  99.615 40.171 100.35 40.397 ;
     RECT  39.456 40.289 39.474 40.433 ;
     RECT  48.636 39.821 48.654 40.469 ;
     RECT  46.62 40.289 46.782 40.559 ;
     RECT  46.62 40.559 46.638 40.595 ;
     RECT  45.576 40.349 45.897 40.703 ;
     RECT  9.108 38.849 9.126 40.711 ;
     RECT  9.036 40.711 9.126 40.739 ;
     RECT  45.615 40.703 45.897 40.787 ;
     RECT  51.015 39.245 51.297 40.787 ;
     RECT  56.415 37.589 56.697 40.787 ;
     RECT  61.815 35.429 62.097 40.787 ;
     RECT  67.215 35.069 67.497 40.787 ;
     RECT  72.615 34.079 72.897 40.787 ;
     RECT  77.544 34.115 78.297 40.787 ;
     RECT  47.808 40.091 47.826 40.829 ;
     RECT  51.015 40.787 51.105 40.837 ;
     RECT  96.264 40.325 97.362 40.865 ;
     RECT  50.688 40.837 51.105 40.973 ;
     RECT  45.615 40.787 45.705 41.057 ;
     RECT  51.015 40.973 51.105 41.057 ;
     RECT  56.415 40.787 56.505 41.057 ;
     RECT  61.815 40.787 61.905 41.057 ;
     RECT  67.215 40.787 67.305 41.057 ;
     RECT  72.615 40.787 72.705 41.057 ;
     RECT  77.544 40.787 78.105 41.057 ;
     RECT  99.615 40.397 100.098 41.251 ;
     RECT  98.64 40.289 98.874 41.279 ;
     RECT  102.564 41.275 102.582 41.405 ;
     RECT  98.748 41.279 98.874 41.449 ;
     RECT  99.615 41.251 100.314 41.449 ;
     RECT  98.748 41.449 100.314 41.521 ;
     RECT  41.292 40.397 43.686 41.594 ;
     RECT  98.748 41.521 100.566 41.675 ;
     RECT  98.748 41.675 100.098 41.819 ;
     RECT  40.215 40.397 40.497 41.881 ;
     RECT  83.415 35.699 86.886 42.493 ;
     RECT  97.344 40.865 97.362 42.601 ;
     RECT  98.748 41.819 98.874 42.601 ;
     RECT  99.615 41.819 100.098 42.601 ;
     RECT  97.344 42.601 97.578 42.719 ;
     RECT  98.748 42.601 100.098 42.727 ;
     RECT  102.564 42.715 102.582 42.755 ;
     RECT  98.748 42.727 100.35 42.835 ;
     RECT  98.244 42.835 100.35 42.899 ;
     RECT  98.244 42.899 100.098 42.989 ;
     RECT  98.748 42.989 100.098 43.025 ;
     RECT  41.292 41.594 43.218 43.2 ;
     RECT  77.544 41.057 77.562 43.2 ;
     RECT  96.264 40.865 96.282 43.609 ;
     RECT  97.344 42.719 97.434 43.609 ;
     RECT  83.415 42.493 86.994 43.645 ;
     RECT  95.868 43.609 96.282 43.681 ;
     RECT  97.344 43.609 97.506 43.681 ;
     RECT  88.815 33.881 89.226 43.709 ;
     RECT  83.196 43.645 86.994 43.807 ;
     RECT  95.868 43.681 97.506 43.907 ;
     RECT  95.724 43.909 95.742 43.949 ;
     RECT  36.864 43.915 36.882 44.069 ;
     RECT  96.552 43.907 97.506 44.069 ;
     RECT  101.448 44.104 101.466 44.141 ;
     RECT  96.804 44.069 97.506 44.339 ;
     RECT  83.16 43.807 86.994 44.347 ;
     RECT  37.008 44.221 37.026 44.381 ;
     RECT  97.344 44.339 97.506 44.491 ;
     RECT  82.656 44.347 86.994 44.573 ;
     RECT  98.748 43.025 98.766 44.645 ;
     RECT  99.615 43.025 100.098 44.761 ;
     RECT  97.344 44.491 97.902 44.813 ;
     RECT  41.292 43.2 81 45.149 ;
     RECT  83.196 44.573 86.994 45.307 ;
     RECT  28.764 40.127 29.697 45.329 ;
     RECT  82.656 45.307 86.994 45.485 ;
     RECT  83.232 45.485 86.994 45.533 ;
     RECT  95.58 45.643 95.598 45.697 ;
     RECT  18.576 38.579 18.897 45.725 ;
     RECT  42.084 45.149 81 45.725 ;
     RECT  102.564 45.499 102.582 45.725 ;
     RECT  95.58 45.697 96.282 45.733 ;
     RECT  95.58 45.733 96.534 45.805 ;
     RECT  24.015 39.245 24.297 45.832 ;
     RECT  95.436 45.805 96.534 45.841 ;
     RECT  97.344 44.813 97.362 45.841 ;
     RECT  98.964 44.761 100.098 45.931 ;
     RECT  95.436 45.841 97.362 45.959 ;
     RECT  95.724 45.959 95.742 46.031 ;
     RECT  12.348 39.209 12.366 46.253 ;
     RECT  83.304 45.533 86.994 46.373 ;
     RECT  23.904 45.832 24.297 46.409 ;
     RECT  42.084 45.725 42.282 46.685 ;
     RECT  20.16 39.119 20.178 46.877 ;
     RECT  98.352 45.931 100.098 46.921 ;
     RECT  101.484 46.849 101.502 46.921 ;
     RECT  98.352 46.921 101.502 46.973 ;
     RECT  43.02 45.725 81 47.261 ;
     RECT  82.656 46.459 82.674 47.281 ;
     RECT  83.415 46.373 86.994 47.281 ;
     RECT  98.352 46.973 100.89 47.281 ;
     RECT  98.172 47.281 100.89 47.309 ;
     RECT  34.128 40.199 35.097 47.323 ;
     RECT  98.964 47.309 100.89 47.381 ;
     RECT  41.292 45.149 41.31 47.453 ;
     RECT  98.964 47.381 100.314 47.489 ;
     RECT  96.84 45.959 97.362 47.623 ;
     RECT  98.172 47.309 98.19 47.623 ;
     RECT  22.068 39.119 22.086 47.645 ;
     RECT  96.84 47.623 98.19 47.687 ;
     RECT  31.608 39.515 31.626 47.741 ;
     RECT  38.7 40.289 38.718 47.821 ;
     RECT  39.6 41.881 40.497 47.821 ;
     RECT  33.948 47.323 35.097 47.849 ;
     RECT  82.656 47.281 86.994 47.849 ;
     RECT  33.948 47.849 33.966 47.891 ;
     RECT  38.7 47.821 40.497 48.029 ;
     RECT  82.656 47.849 86.886 48.155 ;
     RECT  42.084 46.685 42.102 48.221 ;
     RECT  97.164 47.687 98.19 48.271 ;
     RECT  98.964 47.489 99.99 48.271 ;
     RECT  83.232 48.155 86.886 48.299 ;
     RECT  39.132 48.029 40.497 48.361 ;
     RECT  83.268 48.299 86.886 48.389 ;
     RECT  97.164 48.271 99.99 48.389 ;
     RECT  39.132 48.361 40.554 48.425 ;
     RECT  101.376 48.331 101.394 48.461 ;
     RECT  43.092 47.261 81 48.475 ;
     RECT  97.164 48.389 98.226 48.695 ;
     RECT  83.304 48.389 86.886 48.701 ;
     RECT  39.6 48.425 40.554 48.775 ;
     RECT  83.415 48.701 86.886 48.775 ;
     RECT  43.056 48.475 81 48.797 ;
     RECT  11.088 42.457 11.106 48.929 ;
     RECT  39.6 48.775 41.058 48.989 ;
     RECT  43.2 48.797 81 49.051 ;
     RECT  43.2 49.051 81.09 49.181 ;
     RECT  7.815 39.317 8.097 49.441 ;
     RECT  10.08 48.937 10.098 49.469 ;
     RECT  9.036 40.739 9.054 49.477 ;
     RECT  0.54 49.477 0.558 49.517 ;
     RECT  7.815 49.441 8.154 49.517 ;
     RECT  83.415 48.775 87.534 49.549 ;
     RECT  39.6 48.989 41.022 49.577 ;
     RECT  83.376 49.549 87.534 49.579 ;
     RECT  97.164 48.695 98.19 49.613 ;
     RECT  83.304 49.579 87.534 49.621 ;
     RECT  96.336 49.585 96.354 49.711 ;
     RECT  97.164 49.613 97.758 49.711 ;
     RECT  6.804 49.477 6.822 49.739 ;
     RECT  5.688 49.549 5.706 49.775 ;
     RECT  8.892 49.477 9.054 49.775 ;
     RECT  101.988 49.747 102.006 49.805 ;
     RECT  96.336 49.711 97.758 49.891 ;
     RECT  98.964 48.389 99.99 49.891 ;
     RECT  42.156 49.315 42.174 49.915 ;
     RECT  41.58 49.915 42.174 50.045 ;
     RECT  98.964 49.891 100.242 50.045 ;
     RECT  95.94 49.891 97.758 50.089 ;
     RECT  83.304 49.621 87.642 50.125 ;
     RECT  39.6 49.577 40.554 50.141 ;
     RECT  95.76 50.089 97.758 50.141 ;
     RECT  42.156 50.045 42.174 50.333 ;
     RECT  43.2 49.181 81 50.395 ;
     RECT  43.2 50.395 81.09 50.491 ;
     RECT  42.768 50.491 81.09 50.525 ;
     RECT  83.304 50.125 87.714 50.593 ;
     RECT  83.304 50.593 87.858 50.621 ;
     RECT  87.66 50.621 87.858 50.657 ;
     RECT  83.304 50.621 85.518 50.693 ;
     RECT  86.4 50.621 86.922 50.693 ;
     RECT  87.84 50.657 87.858 50.693 ;
     RECT  83.304 50.693 84.978 50.717 ;
     RECT  83.415 50.717 84.978 50.729 ;
     RECT  86.4 50.693 86.67 50.729 ;
     RECT  42.768 50.525 81 50.891 ;
     RECT  86.58 50.729 86.634 50.909 ;
     RECT  39.6 50.141 40.497 50.935 ;
     RECT  39.6 50.935 41.058 51.101 ;
     RECT  82.656 51.067 82.674 51.197 ;
     RECT  86.58 50.909 86.598 51.197 ;
     RECT  81.864 35.195 81.882 51.293 ;
     RECT  102.564 51.163 102.582 51.395 ;
     RECT  95.292 51.307 95.31 51.439 ;
     RECT  96.336 50.141 97.758 51.511 ;
     RECT  98.964 50.045 99.99 51.511 ;
     RECT  98.964 51.511 100.422 51.629 ;
     RECT  95.292 51.439 95.454 51.637 ;
     RECT  96.228 51.511 97.758 51.637 ;
     RECT  98.964 51.629 99.99 51.637 ;
     RECT  95.292 51.637 97.758 51.665 ;
     RECT  96.012 51.665 97.758 51.701 ;
     RECT  41.58 51.451 41.598 51.835 ;
     RECT  41.58 51.835 41.634 51.871 ;
     RECT  96.012 51.701 96.03 51.935 ;
     RECT  98.568 51.637 99.99 51.935 ;
     RECT  39.6 51.101 40.662 52.027 ;
     RECT  41.58 51.871 41.67 52.027 ;
     RECT  96.912 51.701 97.758 52.079 ;
     RECT  39.6 52.027 41.67 52.253 ;
     RECT  43.2 50.891 81 52.411 ;
     RECT  98.964 51.935 99.99 52.591 ;
     RECT  42.192 52.411 42.21 52.637 ;
     RECT  102.564 52.447 102.582 52.637 ;
     RECT  98.964 52.591 101.034 52.709 ;
     RECT  39.6 52.253 41.022 52.987 ;
     RECT  98.964 52.709 100.422 53.123 ;
     RECT  39.6 52.987 42.174 53.213 ;
     RECT  43.092 52.411 81 53.285 ;
     RECT  97.02 52.079 97.758 53.591 ;
     RECT  42.156 53.213 42.174 53.597 ;
     RECT  97.272 53.591 97.758 53.941 ;
     RECT  97.272 53.941 98.082 54.031 ;
     RECT  98.964 53.123 100.314 54.031 ;
     RECT  101.916 53.995 101.934 54.131 ;
     RECT  39.6 53.213 41.058 54.331 ;
     RECT  39.6 54.331 41.634 54.365 ;
     RECT  97.272 54.031 100.314 54.509 ;
     RECT  41.616 54.365 41.634 54.523 ;
     RECT  41.616 54.523 42.21 55.291 ;
     RECT  41.58 55.291 42.21 55.445 ;
     RECT  97.272 54.509 97.758 55.453 ;
     RECT  101.988 55.417 102.006 55.469 ;
     RECT  98.676 54.509 100.314 55.589 ;
     RECT  96.876 55.453 97.794 55.651 ;
     RECT  98.676 55.589 98.874 55.651 ;
     RECT  42.156 55.445 42.21 55.675 ;
     RECT  43.2 53.285 81 55.675 ;
     RECT  42.156 55.675 81 55.679 ;
     RECT  96.876 55.651 98.874 55.679 ;
     RECT  96.876 55.679 98.766 55.715 ;
     RECT  97.02 55.715 98.766 55.751 ;
     RECT  99.615 55.589 100.314 55.787 ;
     RECT  97.02 55.751 97.794 55.823 ;
     RECT  97.02 55.823 97.758 55.853 ;
     RECT  42.192 55.679 81 55.985 ;
     RECT  39.6 54.365 40.497 56.029 ;
     RECT  43.092 55.985 81 56.129 ;
     RECT  38.844 56.101 38.862 56.219 ;
     RECT  39.6 56.029 41.058 56.443 ;
     RECT  42.192 55.985 42.21 56.443 ;
     RECT  94.215 34.763 94.497 56.569 ;
     RECT  97.272 55.853 97.758 56.569 ;
     RECT  98.568 55.751 98.766 56.569 ;
     RECT  95.904 53.563 95.922 56.641 ;
     RECT  39.6 56.443 42.21 56.669 ;
     RECT  95.58 56.641 95.922 56.759 ;
     RECT  102.564 56.767 102.582 56.861 ;
     RECT  95.58 56.759 95.598 56.867 ;
     RECT  94.215 56.569 94.806 56.875 ;
     RECT  39.6 56.669 41.598 56.903 ;
     RECT  94.215 56.875 95.382 56.909 ;
     RECT  99.615 55.787 99.897 56.911 ;
     RECT  43.2 56.129 81 57.001 ;
     RECT  95.364 56.909 95.382 57.029 ;
     RECT  97.272 56.569 98.766 57.029 ;
     RECT  99.615 56.911 100.494 57.137 ;
     RECT  42.732 57.001 81 57.245 ;
     RECT  41.544 56.903 41.598 57.437 ;
     RECT  42.156 57.595 42.174 57.641 ;
     RECT  39.6 56.903 40.497 57.721 ;
     RECT  43.2 57.245 81 57.991 ;
     RECT  39.6 57.721 41.058 58.013 ;
     RECT  39.6 58.013 41.022 58.145 ;
     RECT  97.272 57.029 97.758 58.261 ;
     RECT  98.532 57.029 98.766 58.261 ;
     RECT  99.615 57.137 99.897 58.261 ;
     RECT  102.564 58.117 102.582 58.301 ;
     RECT  42.732 57.991 81 58.363 ;
     RECT  97.272 58.261 98.766 58.459 ;
     RECT  99.576 58.261 99.954 58.459 ;
     RECT  39.6 58.145 40.497 58.531 ;
     RECT  97.272 58.459 99.954 58.531 ;
     RECT  42.156 58.363 81 58.589 ;
     RECT  97.272 58.531 100.314 58.649 ;
     RECT  97.272 58.649 99.954 58.955 ;
     RECT  39.168 58.531 40.497 59.071 ;
     RECT  43.056 58.589 81 59.099 ;
     RECT  38.988 59.071 40.497 59.189 ;
     RECT  42.156 58.589 42.174 59.189 ;
     RECT  39.6 59.189 40.497 59.233 ;
     RECT  43.092 59.099 81 59.495 ;
     RECT  39.6 59.233 41.058 59.515 ;
     RECT  97.272 58.955 99.897 59.729 ;
     RECT  39.6 59.515 41.598 59.741 ;
     RECT  102.564 59.659 102.582 59.765 ;
     RECT  100.872 59.701 100.89 59.837 ;
     RECT  98.172 59.729 99.897 59.999 ;
     RECT  99.576 59.999 99.897 60.071 ;
     RECT  41.58 59.741 41.598 60.151 ;
     RECT  41.58 60.151 41.634 60.269 ;
     RECT  83.415 50.729 83.697 60.277 ;
     RECT  41.616 60.269 41.634 60.509 ;
     RECT  83.415 60.277 84.33 60.701 ;
     RECT  83.415 60.701 83.79 60.817 ;
     RECT  41.76 60.667 41.778 60.859 ;
     RECT  41.76 60.859 41.85 60.881 ;
     RECT  97.272 59.729 97.29 61.003 ;
     RECT  41.832 60.881 41.85 61.051 ;
     RECT  101.916 61.051 101.934 61.151 ;
     RECT  97.164 61.003 97.29 61.159 ;
     RECT  98.172 59.999 98.586 61.159 ;
     RECT  41.832 61.051 42.174 61.349 ;
     RECT  97.164 61.159 98.586 61.349 ;
     RECT  101.196 61.231 101.214 61.385 ;
     RECT  39.6 59.741 40.497 61.435 ;
     RECT  97.2 61.349 98.586 61.457 ;
     RECT  83.232 60.817 83.79 61.465 ;
     RECT  39.6 61.435 41.022 61.493 ;
     RECT  97.272 61.457 98.586 61.619 ;
     RECT  41.58 61.627 41.598 61.664 ;
     RECT  43.2 59.495 81 61.819 ;
     RECT  83.232 61.465 83.898 61.915 ;
     RECT  83.232 61.915 84.438 61.925 ;
     RECT  43.2 61.819 81.09 62.011 ;
     RECT  83.268 61.925 84.438 62.045 ;
     RECT  43.092 62.011 81.09 62.395 ;
     RECT  42.156 62.203 42.174 62.429 ;
     RECT  43.02 62.395 81.09 62.525 ;
     RECT  101.988 62.491 102.006 62.537 ;
     RECT  39.6 61.493 40.59 62.545 ;
     RECT  43.02 62.525 81 62.573 ;
     RECT  83.304 62.045 84.438 62.671 ;
     RECT  83.304 62.671 84.474 62.813 ;
     RECT  83.304 62.813 84.402 62.968 ;
     RECT  39.6 62.545 41.058 62.969 ;
     RECT  43.056 62.573 81 62.969 ;
     RECT  100.836 62.581 100.854 62.969 ;
     RECT  40.215 62.969 41.058 62.971 ;
     RECT  95.508 62.968 95.526 63.005 ;
     RECT  96.3 62.851 96.462 63.005 ;
     RECT  96.444 63.005 96.462 63.041 ;
     RECT  99.615 60.071 99.897 63.121 ;
     RECT  83.232 62.968 84.402 63.163 ;
     RECT  5.976 63.085 5.994 63.239 ;
     RECT  95.652 63.121 95.67 63.239 ;
     RECT  2.415 30.893 2.697 63.247 ;
     RECT  1.728 63.247 2.697 63.259 ;
     RECT  9.036 49.775 9.054 63.347 ;
     RECT  1.728 63.259 3.402 63.389 ;
     RECT  2.415 63.389 3.402 63.391 ;
     RECT  4.212 63.355 4.23 63.391 ;
     RECT  2.415 63.391 4.23 63.509 ;
     RECT  43.092 62.969 81 63.509 ;
     RECT  2.415 63.509 3.15 63.545 ;
     RECT  82.656 63.163 84.402 63.545 ;
     RECT  40.215 62.971 41.598 63.547 ;
     RECT  43.2 63.509 81 63.595 ;
     RECT  40.215 63.547 42.174 63.773 ;
     RECT  43.2 63.595 81.09 63.773 ;
     RECT  102.564 63.823 102.582 63.917 ;
     RECT  99.615 63.121 99.954 63.931 ;
     RECT  83.232 63.545 84.402 64.085 ;
     RECT  98.028 61.619 98.586 64.129 ;
     RECT  99.615 63.931 100.494 64.129 ;
     RECT  98.028 64.129 100.494 64.201 ;
     RECT  98.028 64.201 100.674 64.355 ;
     RECT  42.156 63.773 42.174 64.363 ;
     RECT  98.028 64.355 100.314 64.397 ;
     RECT  99.576 64.397 100.314 64.427 ;
     RECT  83.232 64.085 83.697 64.507 ;
     RECT  42.156 64.363 42.246 64.541 ;
     RECT  40.215 63.773 41.058 64.699 ;
     RECT  42.156 64.541 42.174 64.699 ;
     RECT  40.215 64.699 42.174 64.867 ;
     RECT  83.196 64.507 83.697 64.891 ;
     RECT  39.744 64.867 42.174 64.895 ;
     RECT  39.744 64.895 41.022 64.967 ;
     RECT  101.988 65.323 102.006 65.435 ;
     RECT  42.12 64.895 42.174 65.467 ;
     RECT  43.2 63.773 81 65.467 ;
     RECT  97.272 61.619 97.29 65.551 ;
     RECT  98.028 64.397 98.586 65.551 ;
     RECT  99.615 64.427 100.314 65.551 ;
     RECT  97.02 65.551 97.29 65.611 ;
     RECT  98.028 65.551 98.694 65.611 ;
     RECT  42.12 65.467 81 65.641 ;
     RECT  97.02 65.611 98.694 65.669 ;
     RECT  99.615 65.551 100.674 65.669 ;
     RECT  41.58 65.641 81 65.693 ;
     RECT  82.656 64.891 83.697 65.705 ;
     RECT  83.16 65.705 83.697 65.777 ;
     RECT  97.02 65.669 98.622 65.939 ;
     RECT  42.156 65.693 81 65.975 ;
     RECT  99.615 65.669 100.386 65.975 ;
     RECT  99.615 65.975 100.314 66.047 ;
     RECT  83.232 65.777 83.697 66.083 ;
     RECT  97.02 65.939 98.586 66.083 ;
     RECT  42.156 65.975 42.174 66.209 ;
     RECT  97.02 66.083 97.182 66.757 ;
     RECT  96.516 66.757 97.182 66.793 ;
     RECT  101.916 66.715 101.934 66.821 ;
     RECT  96.336 66.793 97.182 66.829 ;
     RECT  95.76 66.829 97.182 66.893 ;
     RECT  43.2 65.975 81 66.984 ;
     RECT  101.196 66.901 101.214 67.055 ;
     RECT  97.956 66.083 98.586 67.127 ;
     RECT  95.94 66.893 97.182 67.711 ;
     RECT  99.615 66.047 99.99 67.801 ;
     RECT  95.436 67.711 97.182 67.819 ;
     RECT  95.292 67.819 97.182 67.829 ;
     RECT  95.292 67.829 96.93 67.865 ;
     RECT  96.012 67.865 96.93 67.901 ;
     RECT  98.568 67.127 98.586 67.981 ;
     RECT  101.448 68.143 101.466 68.189 ;
     RECT  96.912 67.901 96.93 68.279 ;
     RECT  96.012 67.901 96.03 68.369 ;
     RECT  98.568 67.981 98.622 68.395 ;
     RECT  99.615 67.801 100.062 68.395 ;
     RECT  98.568 68.395 100.062 68.683 ;
     RECT  98.568 68.683 100.566 68.819 ;
     RECT  2.415 63.545 2.697 68.867 ;
     RECT  7.815 49.517 8.097 68.867 ;
     RECT  13.215 38.435 13.497 68.867 ;
     RECT  18.615 45.725 18.897 68.867 ;
     RECT  24.015 46.409 24.297 68.867 ;
     RECT  29.415 45.329 29.697 68.867 ;
     RECT  34.815 47.849 35.097 68.867 ;
     RECT  40.215 64.967 40.497 68.867 ;
     RECT  83.415 66.083 83.697 68.867 ;
     RECT  88.815 43.709 89.097 68.867 ;
     RECT  94.215 56.909 94.497 68.867 ;
     RECT  99.036 68.819 100.566 68.909 ;
     RECT  99.615 68.909 99.99 68.981 ;
     RECT  2.415 68.867 2.505 69.137 ;
     RECT  7.815 68.867 7.905 69.137 ;
     RECT  13.215 68.867 13.305 69.137 ;
     RECT  18.615 68.867 18.705 69.137 ;
     RECT  24.015 68.867 24.105 69.137 ;
     RECT  29.415 68.867 29.505 69.137 ;
     RECT  34.815 68.867 34.905 69.137 ;
     RECT  40.215 68.867 40.305 69.137 ;
     RECT  83.415 68.867 83.505 69.137 ;
     RECT  88.815 68.867 88.905 69.137 ;
     RECT  94.215 68.867 94.305 69.137 ;
     RECT  99.615 68.981 99.705 69.137 ;
     RECT  100.8 68.917 100.818 69.581 ;
    LAYER M4 ;
     RECT  0.06 21.792 0.137 21.816 ;
     RECT  0.06 35.616 0.137 35.64 ;
     RECT  0.06 49.488 0.569 49.512 ;
     RECT  0.06 7.92 2.329 7.944 ;
     RECT  2.293 11.712 2.365 11.736 ;
     RECT  2.329 7.92 2.408 8.52 ;
     RECT  2.365 11.136 2.408 11.736 ;
     RECT  2.293 13.056 2.408 13.08 ;
     RECT  2.329 16.272 2.408 16.296 ;
     RECT  2.293 24.48 2.408 25.224 ;
     RECT  0.06 63.36 2.408 63.384 ;
     RECT  2.408 2.148 2.512 69.132 ;
     RECT  2.401 0.576 2.653 0.6 ;
     RECT  2.512 2.418 2.704 68.862 ;
     RECT  2.653 0.576 2.873 0.648 ;
     RECT  2.873 0.576 2.981 0.6 ;
     RECT  2.704 7.248 3.305 8.52 ;
     RECT  2.704 63.264 3.413 63.288 ;
     RECT  2.704 25.2 3.665 25.224 ;
     RECT  2.704 26.208 3.665 29.256 ;
     RECT  2.704 23.376 3.683 24.168 ;
     RECT  2.704 2.832 3.805 2.856 ;
     RECT  2.704 4.272 3.805 4.296 ;
     RECT  3.697 5.328 3.829 5.352 ;
     RECT  3.305 7.248 3.845 7.992 ;
     RECT  2.704 21.888 3.877 22.248 ;
     RECT  3.683 23.376 3.877 23.976 ;
     RECT  2.704 30.768 3.884 30.888 ;
     RECT  2.704 16.272 3.913 16.296 ;
     RECT  2.704 9.888 3.941 9.912 ;
     RECT  3.877 21.888 3.945 23.976 ;
     RECT  3.941 9.072 4.021 9.912 ;
     RECT  2.704 10.944 4.021 12.648 ;
     RECT  3.913 16.272 4.213 16.872 ;
     RECT  3.805 2.832 4.261 4.296 ;
     RECT  3.829 5.328 4.261 6.024 ;
     RECT  3.884 30.576 4.273 30.888 ;
     RECT  4.021 9.072 4.277 12.648 ;
     RECT  4.213 15.312 4.3 16.872 ;
     RECT  4.261 2.832 4.307 6.024 ;
     RECT  4.3 16.272 4.345 16.872 ;
     RECT  4.307 4.272 4.381 6.024 ;
     RECT  3.845 7.248 4.381 7.8 ;
     RECT  4.273 30.576 4.453 31.128 ;
     RECT  4.453 33.264 4.501 33.528 ;
     RECT  4.307 2.832 4.537 2.856 ;
     RECT  4.501 33.264 4.588 34.344 ;
     RECT  4.345 16.272 4.633 17.688 ;
     RECT  4.633 16.272 4.709 18.456 ;
     RECT  4.709 16.272 4.745 17.112 ;
     RECT  3.769 20.736 4.745 20.76 ;
     RECT  3.665 26.784 4.787 29.256 ;
     RECT  4.381 4.272 4.921 7.8 ;
     RECT  3.945 23.904 4.957 23.976 ;
     RECT  4.921 4.272 4.993 7.944 ;
     RECT  4.777 14.832 4.993 14.952 ;
     RECT  4.993 14.688 5.033 14.952 ;
     RECT  3.945 21.888 5.077 22.776 ;
     RECT  5.033 14.688 5.141 14.76 ;
     RECT  4.745 16.848 5.213 17.112 ;
     RECT  4.277 9.072 5.245 11.736 ;
     RECT  5.245 9.072 5.249 11.784 ;
     RECT  4.453 30.576 5.308 31.944 ;
     RECT  4.709 18.432 5.315 18.456 ;
     RECT  5.077 21.648 5.321 22.776 ;
     RECT  5.308 30.864 5.353 31.944 ;
     RECT  4.588 33.264 5.353 33.816 ;
     RECT  5.249 9.072 5.393 9.912 ;
     RECT  4.993 4.272 5.425 7.992 ;
     RECT  5.425 4.272 5.533 8.76 ;
     RECT  5.125 19.632 5.533 19.656 ;
     RECT  5.249 10.944 5.537 11.784 ;
     RECT  4.787 28.944 5.537 29.256 ;
     RECT  5.321 21.888 5.653 22.776 ;
     RECT  4.957 23.904 5.653 24.744 ;
     RECT  5.213 16.896 5.756 17.112 ;
     RECT  5.393 9.888 5.789 9.912 ;
     RECT  5.533 3.408 6.005 8.76 ;
     RECT  4.787 26.784 6.113 27.912 ;
     RECT  5.141 14.736 6.181 14.76 ;
     RECT  6.113 26.784 6.229 27.672 ;
     RECT  5.533 18.816 6.253 19.656 ;
     RECT  6.229 26.112 6.253 27.672 ;
     RECT  5.653 21.888 6.257 24.744 ;
     RECT  5.756 16.896 6.277 17.64 ;
     RECT  6.253 18.816 6.277 20.328 ;
     RECT  6.257 23.328 6.329 24.744 ;
     RECT  5.353 30.864 6.329 33.816 ;
     RECT  5.537 11.712 6.361 11.784 ;
     RECT  6.257 21.888 6.541 22.344 ;
     RECT  6.329 23.568 6.613 24.744 ;
     RECT  6.253 26.016 6.613 27.672 ;
     RECT  6.329 31.104 6.649 33.816 ;
     RECT  5.537 29.232 6.685 29.256 ;
     RECT  6.649 31.104 6.685 34.152 ;
     RECT  6.005 3.696 6.829 8.76 ;
     RECT  6.361 11.712 6.829 12.552 ;
     RECT  6.277 16.896 6.829 20.328 ;
     RECT  6.541 21.6 6.829 22.344 ;
     RECT  6.685 28.944 6.829 29.256 ;
     RECT  6.829 28.944 6.937 29.688 ;
     RECT  6.829 11.232 7.117 12.552 ;
     RECT  6.829 3.696 7.285 9.528 ;
     RECT  6.829 16.896 7.369 22.344 ;
     RECT  6.181 14.448 7.381 14.76 ;
     RECT  7.369 15.984 7.381 22.344 ;
     RECT  6.685 31.104 7.665 34.632 ;
     RECT  7.381 14.448 7.669 22.344 ;
     RECT  6.613 23.568 7.669 27.672 ;
     RECT  7.665 30.912 7.693 34.632 ;
     RECT  7.285 3.696 7.808 10.2 ;
     RECT  7.117 11.232 7.808 12.6 ;
     RECT  7.669 14.448 7.808 27.672 ;
     RECT  6.937 28.8 7.808 29.688 ;
     RECT  7.693 30.912 7.808 34.776 ;
     RECT  7.549 37.68 7.808 37.704 ;
     RECT  2.704 49.488 7.808 49.512 ;
     RECT  7.808 2.148 7.912 69.132 ;
     RECT  7.912 2.418 8.104 68.862 ;
     RECT  8.104 28.944 8.243 35.976 ;
     RECT  8.104 37.152 8.243 37.704 ;
     RECT  8.243 37.152 8.273 37.176 ;
     RECT  8.104 3.168 8.417 10.248 ;
     RECT  8.243 35.568 8.483 35.976 ;
     RECT  8.243 28.944 9.109 33.864 ;
     RECT  9.109 28.416 9.137 33.864 ;
     RECT  8.104 11.232 9.313 17.208 ;
     RECT  9.313 11.232 9.421 17.64 ;
     RECT  8.104 18.72 9.421 27.432 ;
     RECT  8.417 3.696 9.637 10.248 ;
     RECT  9.421 11.232 9.637 27.432 ;
     RECT  9.137 28.416 9.637 30.024 ;
     RECT  9.637 3.696 9.673 30.024 ;
     RECT  8.483 35.568 9.788 35.832 ;
     RECT  9.637 37.056 9.788 37.08 ;
     RECT  9.673 2.88 9.893 30.024 ;
     RECT  9.893 2.88 10.073 22.872 ;
     RECT  9.893 24.144 10.141 30.024 ;
     RECT  9.137 31.008 10.141 33.864 ;
     RECT  10.141 24.144 10.501 33.864 ;
     RECT  10.501 24.144 10.573 34.056 ;
     RECT  9.788 35.568 10.573 37.08 ;
     RECT  10.073 3.552 10.829 22.872 ;
     RECT  10.753 0.576 10.883 0.6 ;
     RECT  10.573 24.144 10.973 37.08 ;
     RECT  10.829 3.552 11.261 13.416 ;
     RECT  11.261 3.936 11.297 13.416 ;
     RECT  11.297 11.76 11.333 13.416 ;
     RECT  11.297 3.936 11.405 10.248 ;
     RECT  11.193 37.2 11.581 37.896 ;
     RECT  10.829 14.832 11.761 22.872 ;
     RECT  10.973 24.144 11.761 35.976 ;
     RECT  11.761 14.832 11.941 35.976 ;
     RECT  9.241 1.728 11.977 1.752 ;
     RECT  11.941 14.832 11.977 36.072 ;
     RECT  11.977 1.632 12.131 1.752 ;
     RECT  11.405 9.552 12.301 10.248 ;
     RECT  10.741 46.272 12.337 46.296 ;
     RECT  11.333 11.76 12.445 13.368 ;
     RECT  12.301 9.552 12.517 10.68 ;
     RECT  12.445 11.76 12.517 13.416 ;
     RECT  11.977 14.784 12.517 36.072 ;
     RECT  11.581 37.2 12.517 38.76 ;
     RECT  11.537 2.88 12.589 2.904 ;
     RECT  11.405 3.936 12.589 8.568 ;
     RECT  12.517 9.552 12.589 13.416 ;
     RECT  12.517 14.784 13.201 38.76 ;
     RECT  12.131 1.728 13.208 1.752 ;
     RECT  12.589 2.88 13.208 13.416 ;
     RECT  13.201 14.64 13.208 38.76 ;
     RECT  12.337 46.224 13.208 46.296 ;
     RECT  8.104 49.488 13.208 49.512 ;
     RECT  13.208 1.728 13.312 69.132 ;
     RECT  13.312 1.728 13.504 68.862 ;
     RECT  13.504 15.792 13.619 38.76 ;
     RECT  13.504 1.728 13.621 1.848 ;
     RECT  13.504 3.648 13.673 14.76 ;
     RECT  13.619 15.792 13.763 36.6 ;
     RECT  13.673 3.648 14.033 12.264 ;
     RECT  13.763 15.792 14.069 33.672 ;
     RECT  14.033 11.712 14.177 12.264 ;
     RECT  13.673 13.632 14.195 14.76 ;
     RECT  13.621 1.152 14.213 1.848 ;
     RECT  13.763 34.704 14.605 36.6 ;
     RECT  13.619 37.68 14.605 38.76 ;
     RECT  14.033 3.648 14.641 10.68 ;
     RECT  14.177 11.76 14.641 12.264 ;
     RECT  14.213 1.728 14.675 1.848 ;
     RECT  14.069 16.608 14.785 33.672 ;
     RECT  14.605 34.704 14.785 38.76 ;
     RECT  14.641 3.552 14.821 10.68 ;
     RECT  14.821 3.168 14.933 10.68 ;
     RECT  14.785 16.608 15.107 38.76 ;
     RECT  14.195 14.16 15.113 14.76 ;
     RECT  14.933 4.416 15.181 10.68 ;
     RECT  14.675 1.728 15.229 1.8 ;
     RECT  15.113 14.256 15.293 14.76 ;
     RECT  15.107 16.608 15.365 33.624 ;
     RECT  15.181 4.416 15.433 10.776 ;
     RECT  14.641 11.76 15.433 12.552 ;
     RECT  15.433 4.416 15.469 12.552 ;
     RECT  15.365 16.608 15.541 33.576 ;
     RECT  15.469 4.416 15.577 12.84 ;
     RECT  14.933 3.168 15.833 3.432 ;
     RECT  15.107 34.704 15.833 38.76 ;
     RECT  15.833 3.408 16.045 3.432 ;
     RECT  15.577 4.416 16.045 13.08 ;
     RECT  15.932 15.36 16.153 15.384 ;
     RECT  15.541 16.512 16.153 33.576 ;
     RECT  15.293 14.256 16.225 14.328 ;
     RECT  16.045 3.408 16.477 13.08 ;
     RECT  16.225 14.064 16.477 14.328 ;
     RECT  16.153 15.36 16.477 33.576 ;
     RECT  15.833 34.704 16.477 36.408 ;
     RECT  16.477 3.408 16.805 14.328 ;
     RECT  16.477 15.36 16.805 36.408 ;
     RECT  16.805 12.816 16.945 14.328 ;
     RECT  16.805 15.36 16.945 33.384 ;
     RECT  16.945 12.816 16.949 33.384 ;
     RECT  15.229 1.728 17.281 1.752 ;
     RECT  16.805 34.368 17.305 36.408 ;
     RECT  15.833 37.392 17.305 38.76 ;
     RECT  16.949 12.816 17.917 22.968 ;
     RECT  16.949 24.144 17.917 33.384 ;
     RECT  17.917 12.816 17.989 33.384 ;
     RECT  17.305 34.368 17.989 38.76 ;
     RECT  16.805 3.408 18.061 11.784 ;
     RECT  17.989 12.816 18.061 38.76 ;
     RECT  18.284 2.256 18.385 2.28 ;
     RECT  18.061 3.408 18.385 38.76 ;
     RECT  13.504 46.272 18.565 46.392 ;
     RECT  18.385 2.256 18.608 38.76 ;
     RECT  18.565 45.696 18.608 46.392 ;
     RECT  13.504 49.488 18.608 49.512 ;
     RECT  18.608 2.148 18.712 69.132 ;
     RECT  18.712 2.418 18.904 68.862 ;
     RECT  18.904 2.88 19.181 14.184 ;
     RECT  19.181 2.88 19.757 13.656 ;
     RECT  18.904 16.032 19.937 38.76 ;
     RECT  19.757 2.88 20.045 10.344 ;
     RECT  18.904 45.84 20.149 46.392 ;
     RECT  19.757 11.376 20.293 13.656 ;
     RECT  19.937 16.032 20.369 21 ;
     RECT  20.293 11.376 20.405 14.52 ;
     RECT  20.045 3.12 20.869 10.344 ;
     RECT  20.405 11.376 20.869 11.832 ;
     RECT  20.405 12.816 20.941 14.52 ;
     RECT  19.937 21.984 21.013 38.76 ;
     RECT  20.941 12.816 21.157 14.568 ;
     RECT  21.013 21.984 21.269 39 ;
     RECT  20.869 3.12 21.365 11.832 ;
     RECT  21.365 2.832 21.449 11.832 ;
     RECT  21.157 12.816 21.481 14.856 ;
     RECT  20.369 16.032 21.481 20.808 ;
     RECT  21.449 2.88 21.557 11.832 ;
     RECT  21.481 12.816 21.625 20.808 ;
     RECT  21.269 21.984 21.625 37.944 ;
     RECT  20.149 45.84 22.057 46.872 ;
     RECT  21.625 12.816 22.777 37.944 ;
     RECT  21.269 38.976 22.777 39 ;
     RECT  21.557 2.88 22.813 10.488 ;
     RECT  21.557 11.568 22.813 11.832 ;
     RECT  22.777 12.816 22.817 39 ;
     RECT  22.813 2.88 23.137 11.832 ;
     RECT  22.817 12.816 23.137 12.84 ;
     RECT  23.137 2.88 24.008 12.84 ;
     RECT  22.817 13.92 24.008 39 ;
     RECT  22.057 45.84 24.008 47.64 ;
     RECT  18.904 49.488 24.008 49.512 ;
     RECT  24.008 2.148 24.112 69.132 ;
     RECT  24.112 2.418 24.304 68.862 ;
     RECT  24.304 2.832 24.797 39.096 ;
     RECT  24.797 25.584 25.733 39.096 ;
     RECT  25.621 1.152 25.805 1.176 ;
     RECT  24.797 2.832 25.837 24.36 ;
     RECT  25.733 25.584 25.837 39 ;
     RECT  25.837 2.832 26.525 39 ;
     RECT  26.525 23.904 26.633 39 ;
     RECT  26.633 25.584 26.777 39 ;
     RECT  26.525 2.832 26.813 22.632 ;
     RECT  26.777 31.488 26.821 39 ;
     RECT  26.813 18.48 26.885 22.632 ;
     RECT  26.813 2.832 27.059 17.496 ;
     RECT  27.059 2.832 27.317 15.048 ;
     RECT  26.633 23.904 27.673 24.216 ;
     RECT  27.673 23.904 27.781 24.312 ;
     RECT  26.885 18.528 27.817 22.632 ;
     RECT  27.781 23.616 27.817 24.312 ;
     RECT  26.777 25.584 27.817 30.456 ;
     RECT  26.821 31.488 27.817 39.576 ;
     RECT  27.317 3.024 27.965 15.048 ;
     RECT  27.817 18.528 28.069 24.312 ;
     RECT  27.817 25.584 28.069 39.576 ;
     RECT  27.965 12.816 28.141 15.048 ;
     RECT  27.059 16.272 28.141 17.496 ;
     RECT  28.069 18.528 28.141 39.576 ;
     RECT  27.965 3.024 28.397 11.832 ;
     RECT  25.873 1.728 28.453 1.752 ;
     RECT  28.397 3.024 28.897 5.784 ;
     RECT  28.397 6.816 29.041 11.832 ;
     RECT  28.141 12.816 29.041 39.576 ;
     RECT  28.453 1.152 29.269 1.752 ;
     RECT  28.897 2.832 29.269 5.784 ;
     RECT  29.269 1.152 29.365 5.784 ;
     RECT  29.041 6.816 29.365 39.576 ;
     RECT  29.365 1.152 29.408 39.576 ;
     RECT  24.304 45.84 29.408 47.64 ;
     RECT  24.304 49.488 29.408 49.512 ;
     RECT  29.408 1.152 29.512 69.132 ;
     RECT  29.512 1.152 29.704 68.862 ;
     RECT  29.581 0.096 29.747 0.12 ;
     RECT  29.704 1.152 29.873 1.752 ;
     RECT  29.704 2.88 29.945 39.576 ;
     RECT  29.945 25.584 30.089 39.576 ;
     RECT  29.945 2.88 30.125 24.504 ;
     RECT  30.089 34.128 30.233 39.576 ;
     RECT  30.089 25.584 30.773 32.856 ;
     RECT  30.757 0.096 30.899 0.12 ;
     RECT  30.125 2.88 31.093 12.84 ;
     RECT  30.125 13.92 31.093 24.504 ;
     RECT  31.057 0.576 31.237 0.6 ;
     RECT  29.873 1.728 31.237 1.752 ;
     RECT  30.233 34.224 31.561 39.576 ;
     RECT  31.237 0.576 31.571 1.752 ;
     RECT  31.093 2.88 31.597 24.504 ;
     RECT  30.773 25.584 31.597 32.664 ;
     RECT  29.704 45.84 31.597 47.64 ;
     RECT  31.597 2.88 31.741 32.664 ;
     RECT  31.561 34.08 31.741 39.576 ;
     RECT  31.571 0.576 31.811 1.176 ;
     RECT  31.811 1.152 32.569 1.176 ;
     RECT  32.569 1.152 32.789 1.752 ;
     RECT  31.741 2.88 33.587 39.576 ;
     RECT  32.789 1.728 33.589 1.752 ;
     RECT  33.587 14.4 33.797 39.576 ;
     RECT  31.597 45.84 33.925 47.736 ;
     RECT  33.587 2.88 34.808 13.368 ;
     RECT  33.797 14.4 34.808 15.24 ;
     RECT  33.797 16.272 34.808 39.576 ;
     RECT  33.973 44.352 34.808 44.376 ;
     RECT  33.925 45.84 34.808 47.88 ;
     RECT  29.704 49.488 34.808 49.512 ;
     RECT  34.808 2.148 34.912 69.132 ;
     RECT  34.912 2.418 35.104 68.862 ;
     RECT  35.104 3.072 35.957 39.576 ;
     RECT  35.957 14.16 36.029 39.576 ;
     RECT  36.029 14.208 36.092 39.576 ;
     RECT  36.092 14.208 36.179 40.056 ;
     RECT  36.179 14.208 36.677 39.912 ;
     RECT  35.104 44.352 36.853 44.376 ;
     RECT  36.853 43.92 36.937 44.376 ;
     RECT  35.957 3.072 37.033 13.128 ;
     RECT  37.033 2.88 37.321 13.128 ;
     RECT  36.677 14.208 37.321 33.096 ;
     RECT  36.677 34.56 37.789 39.912 ;
     RECT  37.321 2.88 38.113 33.096 ;
     RECT  38.113 2.784 38.149 33.096 ;
     RECT  37.789 34.416 38.149 39.912 ;
     RECT  38.149 2.784 38.437 39.912 ;
     RECT  36.937 44.352 38.483 44.376 ;
     RECT  35.104 45.84 38.689 47.736 ;
     RECT  38.437 2.784 39.161 40.392 ;
     RECT  39.161 2.784 40.208 13.944 ;
     RECT  39.161 15.168 40.208 40.392 ;
     RECT  38.689 45.84 40.208 48.024 ;
     RECT  40.165 49.008 40.208 49.032 ;
     RECT  39.949 50.88 40.208 50.904 ;
     RECT  40.208 2.148 40.312 69.132 ;
     RECT  40.312 2.418 40.504 68.862 ;
     RECT  40.504 2.784 40.601 40.392 ;
     RECT  40.504 61.44 41.497 62.808 ;
     RECT  40.504 64.128 41.497 64.92 ;
     RECT  40.601 2.784 41.5 40.344 ;
     RECT  40.504 56.256 41.569 58.008 ;
     RECT  40.504 59.712 41.569 59.736 ;
     RECT  41.497 61.44 41.569 64.92 ;
     RECT  40.504 45.888 41.605 54.168 ;
     RECT  41.569 55.296 41.605 58.008 ;
     RECT  41.569 59.52 41.605 60.12 ;
     RECT  41.569 61.44 41.605 65.688 ;
     RECT  41.677 44.736 41.785 44.76 ;
     RECT  41.605 45.888 41.785 58.008 ;
     RECT  41.785 44.736 42.145 58.008 ;
     RECT  41.605 59.52 42.145 65.688 ;
     RECT  42.145 44.736 42.181 65.88 ;
     RECT  41.5 2.784 42.401 38.28 ;
     RECT  41.989 1.728 42.469 1.752 ;
     RECT  42.469 1.152 42.577 1.752 ;
     RECT  42.685 42.432 42.721 42.456 ;
     RECT  42.577 0.576 42.803 1.752 ;
     RECT  42.803 1.152 42.833 1.752 ;
     RECT  42.401 34.368 42.901 38.28 ;
     RECT  41.5 39.264 42.901 40.344 ;
     RECT  42.901 34.368 42.985 40.344 ;
     RECT  42.721 42.432 42.997 42.744 ;
     RECT  42.985 39.504 43.045 40.344 ;
     RECT  42.181 44.16 43.045 65.88 ;
     RECT  43.045 39.504 43.261 40.728 ;
     RECT  42.997 42.432 43.272 42.792 ;
     RECT  43.045 43.968 43.272 65.88 ;
     RECT  42.401 2.784 43.337 33.144 ;
     RECT  43.261 39.504 43.553 40.824 ;
     RECT  43.337 15.216 43.573 33.144 ;
     RECT  42.985 34.368 43.573 38.424 ;
     RECT  43.573 15.216 44.269 38.424 ;
     RECT  43.553 39.504 44.269 40.344 ;
     RECT  42.833 1.728 44.293 1.752 ;
     RECT  43.801 0.576 44.579 0.6 ;
     RECT  43.272 42.432 44.579 66.984 ;
     RECT  43.337 2.784 44.845 13.896 ;
     RECT  44.845 2.784 45.013 14.232 ;
     RECT  44.269 15.216 45.013 40.344 ;
     RECT  44.293 1.728 45.608 1.8 ;
     RECT  45.013 2.784 45.608 40.344 ;
     RECT  45.608 1.728 45.712 41.052 ;
     RECT  45.712 1.728 45.904 40.782 ;
     RECT  45.904 14.496 46.019 39.912 ;
     RECT  46.019 14.496 46.325 37.992 ;
     RECT  46.325 14.496 46.865 37.896 ;
     RECT  45.904 2.88 46.897 13.464 ;
     RECT  46.865 14.496 46.897 37.416 ;
     RECT  46.897 2.88 47.041 37.416 ;
     RECT  47.041 2.736 47.081 37.416 ;
     RECT  47.081 2.736 47.369 37.032 ;
     RECT  46.019 39.024 47.405 39.912 ;
     RECT  45.904 1.728 47.605 1.752 ;
     RECT  47.369 16.656 47.621 37.032 ;
     RECT  47.369 2.88 47.765 15.48 ;
     RECT  47.405 39.024 47.869 39.048 ;
     RECT  47.765 14.64 47.981 15.48 ;
     RECT  47.621 27.936 48.179 37.032 ;
     RECT  47.605 1.152 48.341 1.752 ;
     RECT  48.179 27.984 48.521 37.032 ;
     RECT  47.621 16.656 48.733 26.952 ;
     RECT  48.521 28.416 48.805 37.032 ;
     RECT  47.765 2.88 48.917 13.464 ;
     RECT  48.805 28.416 49.165 37.08 ;
     RECT  47.869 38.736 49.165 39.048 ;
     RECT  47.981 14.832 49.349 15.48 ;
     RECT  49.165 28.416 49.349 39.048 ;
     RECT  49.349 29.472 49.529 39.048 ;
     RECT  49.529 29.568 49.637 39.048 ;
     RECT  49.637 29.616 49.673 39.048 ;
     RECT  48.733 16.512 49.705 26.952 ;
     RECT  49.349 28.416 49.741 28.44 ;
     RECT  49.705 16.512 50.065 27.048 ;
     RECT  48.341 1.728 50.069 1.752 ;
     RECT  49.349 15.024 50.101 15.48 ;
     RECT  50.065 16.512 50.101 27.144 ;
     RECT  48.917 3.6 50.341 13.464 ;
     RECT  50.341 3.6 50.353 13.896 ;
     RECT  50.101 15.024 50.353 27.144 ;
     RECT  50.353 3.168 50.605 27.144 ;
     RECT  49.741 28.176 50.605 28.44 ;
     RECT  50.54 0.096 50.627 0.12 ;
     RECT  50.605 3.168 50.725 28.44 ;
     RECT  49.673 29.616 50.725 38.184 ;
     RECT  50.725 3.168 51.008 38.28 ;
     RECT  51.008 2.148 51.112 41.052 ;
     RECT  51.112 2.418 51.304 40.782 ;
     RECT  51.304 25.536 51.401 25.56 ;
     RECT  51.304 28.464 51.445 38.232 ;
     RECT  51.445 28.464 51.509 37.608 ;
     RECT  51.509 28.464 51.545 36.6 ;
     RECT  51.304 12.816 51.653 20.76 ;
     RECT  51.304 3.36 52.013 11.784 ;
     RECT  51.653 16.656 52.163 20.76 ;
     RECT  51.509 37.584 52.229 37.608 ;
     RECT  52.013 10.176 52.405 11.784 ;
     RECT  51.653 12.816 52.405 15.624 ;
     RECT  52.405 10.176 52.837 15.624 ;
     RECT  52.163 16.656 52.837 20.472 ;
     RECT  52.013 3.36 52.981 9.096 ;
     RECT  52.981 3.168 53.029 9.096 ;
     RECT  51.304 21.792 53.089 24.504 ;
     RECT  52.837 25.584 53.089 25.608 ;
     RECT  53.029 3.168 53.117 9.144 ;
     RECT  52.837 10.176 53.117 20.472 ;
     RECT  51.545 28.464 53.197 36.504 ;
     RECT  51.304 26.736 53.413 27.096 ;
     RECT  53.197 28.416 53.413 36.504 ;
     RECT  53.413 26.736 53.525 36.504 ;
     RECT  53.525 31.104 53.633 36.504 ;
     RECT  53.633 35.04 53.669 36.504 ;
     RECT  53.089 21.792 53.845 25.608 ;
     RECT  53.525 26.736 53.845 30.024 ;
     RECT  53.845 21.792 53.849 30.024 ;
     RECT  53.117 3.168 53.989 20.472 ;
     RECT  53.849 21.792 53.989 29.88 ;
     RECT  53.989 3.168 54.097 29.88 ;
     RECT  54.097 3.072 54.179 29.88 ;
     RECT  53.633 31.104 54.641 34.056 ;
     RECT  54.641 32.736 54.781 34.056 ;
     RECT  53.669 35.04 54.781 36.456 ;
     RECT  54.179 3.072 54.785 23.928 ;
     RECT  54.179 24.912 54.817 29.88 ;
     RECT  54.641 31.104 54.817 31.752 ;
     RECT  54.817 24.912 55.037 31.752 ;
     RECT  54.781 32.736 55.145 36.456 ;
     RECT  54.785 3.264 55.177 23.928 ;
     RECT  55.037 24.912 55.177 27.192 ;
     RECT  55.177 3.264 55.361 27.192 ;
     RECT  55.361 3.264 55.397 24.168 ;
     RECT  55.397 3.264 55.897 23.736 ;
     RECT  55.145 32.736 56.221 36.36 ;
     RECT  55.037 28.464 56.329 31.752 ;
     RECT  56.221 32.736 56.329 36.504 ;
     RECT  55.897 3.024 56.408 23.736 ;
     RECT  55.361 25.296 56.408 27.192 ;
     RECT  56.329 28.464 56.408 36.504 ;
     RECT  56.408 2.148 56.512 41.052 ;
     RECT  56.512 2.418 56.704 40.782 ;
     RECT  56.704 21.504 56.819 35.928 ;
     RECT  56.819 33.648 56.845 35.928 ;
     RECT  56.819 21.504 57.053 32.424 ;
     RECT  56.704 3.024 57.233 20.472 ;
     RECT  57.053 21.504 57.341 30.072 ;
     RECT  57.233 3.024 58.021 18.888 ;
     RECT  57.053 31.104 58.069 32.424 ;
     RECT  56.845 33.648 58.115 35.784 ;
     RECT  58.021 2.88 58.205 18.888 ;
     RECT  57.341 24.672 58.205 30.072 ;
     RECT  58.205 3.312 58.273 18.888 ;
     RECT  57.233 19.872 58.273 20.472 ;
     RECT  58.069 31.104 58.405 32.616 ;
     RECT  58.273 3.312 58.511 20.472 ;
     RECT  57.341 21.504 58.511 23.64 ;
     RECT  58.165 1.728 58.597 1.752 ;
     RECT  58.597 1.152 58.745 1.752 ;
     RECT  58.205 24.672 58.781 24.696 ;
     RECT  58.115 34.224 59.033 35.784 ;
     RECT  58.405 31.104 59.219 33 ;
     RECT  58.205 25.68 59.257 29.784 ;
     RECT  58.511 3.312 59.365 23.64 ;
     RECT  59.257 28.032 59.425 29.784 ;
     RECT  59.033 34.224 59.785 35.736 ;
     RECT  59.219 32.736 59.797 33 ;
     RECT  59.785 34.176 59.797 35.736 ;
     RECT  59.365 2.88 59.825 23.64 ;
     RECT  59.825 2.976 59.933 23.64 ;
     RECT  59.257 25.68 59.965 26.952 ;
     RECT  59.425 28.032 60.005 30.072 ;
     RECT  59.933 3.168 60.113 23.64 ;
     RECT  59.797 32.736 60.113 35.736 ;
     RECT  60.113 32.736 60.185 35.496 ;
     RECT  60.113 12.72 60.469 23.64 ;
     RECT  60.005 28.704 60.469 30.072 ;
     RECT  59.219 31.104 60.469 31.752 ;
     RECT  60.185 35.04 60.473 35.496 ;
     RECT  59.965 25.2 60.613 26.952 ;
     RECT  60.113 3.168 60.689 11.688 ;
     RECT  58.745 1.728 60.721 1.752 ;
     RECT  60.613 25.2 60.973 27.336 ;
     RECT  60.469 28.704 60.973 31.752 ;
     RECT  60.689 3.408 61.405 11.688 ;
     RECT  60.469 12.72 61.405 24.168 ;
     RECT  60.721 1.728 61.733 1.8 ;
     RECT  60.185 32.736 61.765 33.816 ;
     RECT  61.405 3.408 61.808 24.168 ;
     RECT  60.973 25.2 61.808 31.752 ;
     RECT  61.765 32.736 61.808 33.96 ;
     RECT  60.473 35.04 61.808 35.064 ;
     RECT  61.808 2.148 61.912 41.052 ;
     RECT  61.909 1.152 61.945 1.176 ;
     RECT  61.912 2.418 62.104 40.782 ;
     RECT  61.945 0.576 62.165 1.176 ;
     RECT  62.165 0.576 62.195 0.6 ;
     RECT  62.437 0.096 62.723 0.168 ;
     RECT  62.104 2.88 63.173 33.96 ;
     RECT  62.723 0.096 63.461 0.12 ;
     RECT  62.917 1.728 63.565 1.752 ;
     RECT  63.565 1.68 63.74 1.752 ;
     RECT  63.173 2.88 63.74 33.72 ;
     RECT  63.74 1.68 63.821 33.72 ;
     RECT  63.821 1.68 63.827 33.384 ;
     RECT  63.827 2.88 64.001 33.384 ;
     RECT  63.827 1.68 64.019 1.752 ;
     RECT  64.001 3.456 64.577 33.384 ;
     RECT  64.019 1.728 65.509 1.752 ;
     RECT  65.509 1.152 65.657 1.752 ;
     RECT  64.577 3.456 66.085 33.048 ;
     RECT  65.657 1.728 66.313 1.752 ;
     RECT  66.085 3.456 66.661 33.816 ;
     RECT  66.661 3.456 66.844 33.864 ;
     RECT  66.844 3.408 67.208 33.864 ;
     RECT  62.104 35.04 67.208 35.064 ;
     RECT  67.208 2.148 67.312 41.052 ;
     RECT  67.312 2.418 67.504 40.782 ;
     RECT  67.504 3.408 67.619 33.672 ;
     RECT  67.619 3.408 67.673 33.384 ;
     RECT  67.673 3.408 67.781 33.336 ;
     RECT  67.781 3.408 68.773 24.696 ;
     RECT  67.781 25.728 68.773 33.336 ;
     RECT  68.773 3.408 69.109 33.336 ;
     RECT  69.109 3.408 69.473 33.384 ;
     RECT  69.473 3.408 69.581 17.88 ;
     RECT  69.473 18.912 69.829 33.384 ;
     RECT  69.829 18.912 69.916 33.672 ;
     RECT  69.581 3.648 70.621 17.88 ;
     RECT  69.916 18.912 70.621 33.576 ;
     RECT  70.621 3.648 71.305 33.576 ;
     RECT  71.305 3.648 71.521 33.72 ;
     RECT  71.521 3.552 72.608 33.72 ;
     RECT  67.504 35.04 72.608 35.064 ;
     RECT  72.608 2.148 72.712 41.052 ;
     RECT  72.712 2.418 72.904 40.782 ;
     RECT  72.904 3.648 73.541 34.008 ;
     RECT  74.437 0.096 74.581 0.12 ;
     RECT  74.581 0.096 74.723 0.6 ;
     RECT  73.541 3.648 74.725 20.424 ;
     RECT  73.541 21.456 74.725 34.008 ;
     RECT  74.723 0.576 75.121 0.6 ;
     RECT  74.725 3.648 75.557 34.008 ;
     RECT  75.557 3.648 76.021 33.624 ;
     RECT  74.869 1.728 76.033 1.752 ;
     RECT  75.121 0.576 76.213 0.648 ;
     RECT  76.021 3.6 76.385 33.624 ;
     RECT  76.213 0.576 76.421 1.176 ;
     RECT  76.385 14.448 76.421 33.624 ;
     RECT  76.385 3.6 76.741 13.08 ;
     RECT  76.421 14.448 77.425 18.216 ;
     RECT  76.421 19.2 77.425 33.624 ;
     RECT  77.425 14.448 77.569 33.624 ;
     RECT  76.741 2.88 77.852 13.08 ;
     RECT  77.569 14.16 77.852 33.624 ;
     RECT  77.569 1.728 78.008 1.752 ;
     RECT  77.852 2.88 78.008 33.624 ;
     RECT  72.904 35.04 78.008 35.064 ;
     RECT  76.421 0.576 78.035 0.6 ;
     RECT  78.008 1.728 78.112 41.052 ;
     RECT  78.112 1.728 78.304 40.782 ;
     RECT  78.304 3.6 80.413 33.864 ;
     RECT  80.413 2.88 80.867 33.864 ;
     RECT  44.579 43.2 80.928 66.984 ;
     RECT  80.928 43.968 81 65.88 ;
     RECT  78.304 1.728 81.061 1.752 ;
     RECT  80.867 3.072 81.353 33.864 ;
     RECT  81.353 3.072 81.389 22.344 ;
     RECT  80.845 0.096 81.395 0.12 ;
     RECT  81.061 1.728 81.425 1.848 ;
     RECT  81.353 23.424 81.425 33.864 ;
     RECT  81.425 23.424 81.605 33.144 ;
     RECT  81 43.968 81.893 51.288 ;
     RECT  81.425 1.728 82.115 1.8 ;
     RECT  81.389 3.648 82.181 22.344 ;
     RECT  81.605 23.52 82.361 33.144 ;
     RECT  82.181 3.648 82.465 22.008 ;
     RECT  82.115 1.728 82.469 1.752 ;
     RECT  78.304 35.04 82.645 35.064 ;
     RECT  82.597 1.152 82.721 1.176 ;
     RECT  82.361 23.52 82.789 23.928 ;
     RECT  82.465 3.408 82.825 22.008 ;
     RECT  82.361 25.056 82.897 33.144 ;
     RECT  82.825 2.88 83.149 22.008 ;
     RECT  82.789 22.992 83.149 23.928 ;
     RECT  83.149 2.88 83.408 23.928 ;
     RECT  82.897 25.056 83.408 33.288 ;
     RECT  82.645 34.944 83.408 35.064 ;
     RECT  81.893 43.968 83.408 51.192 ;
     RECT  81 60.672 83.408 65.88 ;
     RECT  83.408 2.148 83.512 69.132 ;
     RECT  83.512 2.418 83.704 68.862 ;
     RECT  83.704 60.672 83.801 63.624 ;
     RECT  83.704 47.136 83.939 51.192 ;
     RECT  83.704 2.88 84.017 29.88 ;
     RECT  83.939 48.144 84.125 51.192 ;
     RECT  83.801 60.672 84.341 60.696 ;
     RECT  83.801 61.92 84.413 63.624 ;
     RECT  83.704 30.864 84.449 33.288 ;
     RECT  84.413 61.92 84.449 62.808 ;
     RECT  83.704 45.456 84.485 45.48 ;
     RECT  84.449 62.784 84.485 62.808 ;
     RECT  83.939 47.136 84.665 47.16 ;
     RECT  84.125 48.96 84.665 51.192 ;
     RECT  84.665 49.056 84.881 51.192 ;
     RECT  84.017 3.12 85.021 29.88 ;
     RECT  84.449 30.864 85.021 33.144 ;
     RECT  85.021 3.12 85.057 33.144 ;
     RECT  85.057 3.024 85.097 33.144 ;
     RECT  83.704 34.944 85.385 34.968 ;
     RECT  84.881 49.056 85.493 49.56 ;
     RECT  85.097 3.024 85.889 33.048 ;
     RECT  85.777 47.856 85.957 47.88 ;
     RECT  84.881 50.88 86.173 51.192 ;
     RECT  85.957 47.856 86.177 47.976 ;
     RECT  85.889 3.024 86.213 19.08 ;
     RECT  86.177 47.856 86.357 47.88 ;
     RECT  85.889 20.112 86.573 33.048 ;
     RECT  86.573 21.648 86.609 33.048 ;
     RECT  86.173 50.016 86.609 51.192 ;
     RECT  86.609 50.016 86.645 50.904 ;
     RECT  83.704 36.48 86.717 36.504 ;
     RECT  86.609 21.648 86.753 33 ;
     RECT  86.753 23.28 86.825 33 ;
     RECT  86.825 23.28 86.861 29.928 ;
     RECT  86.825 30.96 86.867 33 ;
     RECT  86.645 50.016 87.005 50.088 ;
     RECT  86.861 23.856 87.148 29.928 ;
     RECT  86.213 3.024 87.181 9.048 ;
     RECT  87.181 2.88 87.289 9.048 ;
     RECT  86.213 10.128 87.289 19.08 ;
     RECT  87.289 2.88 87.325 19.08 ;
     RECT  86.573 20.112 87.325 20.424 ;
     RECT  87.005 50.016 87.329 50.04 ;
     RECT  86.821 35.424 87.433 35.448 ;
     RECT  87.433 35.328 87.517 35.448 ;
     RECT  86.753 21.648 87.721 22.248 ;
     RECT  87.721 21.648 87.901 22.584 ;
     RECT  87.325 2.88 88.045 20.424 ;
     RECT  86.867 30.96 88.117 32.28 ;
     RECT  88.117 30.96 88.261 32.664 ;
     RECT  87.148 23.856 88.333 29.88 ;
     RECT  88.261 30.864 88.333 32.664 ;
     RECT  88.045 2.88 88.513 20.616 ;
     RECT  87.901 21.648 88.513 22.824 ;
     RECT  88.513 2.88 88.549 22.824 ;
     RECT  88.333 23.856 88.549 32.664 ;
     RECT  87.289 1.392 88.808 1.416 ;
     RECT  88.549 2.88 88.808 32.664 ;
     RECT  87.517 35.424 88.808 35.448 ;
     RECT  88.808 1.392 88.912 69.132 ;
     RECT  88.912 2.418 89.104 68.862 ;
     RECT  89.104 10.128 89.273 33.144 ;
     RECT  89.104 2.88 89.561 9.096 ;
     RECT  89.273 10.128 89.633 32.328 ;
     RECT  89.633 10.176 90.101 32.328 ;
     RECT  89.561 2.88 90.137 5.064 ;
     RECT  90.101 10.176 90.137 21.576 ;
     RECT  90.137 2.88 90.245 4.92 ;
     RECT  90.101 22.752 90.245 32.328 ;
     RECT  90.245 2.88 90.641 4.728 ;
     RECT  90.245 22.752 90.785 26.808 ;
     RECT  90.245 27.936 90.785 32.328 ;
     RECT  90.137 10.992 90.965 21.576 ;
     RECT  90.785 31.44 91.001 32.328 ;
     RECT  88.912 1.392 91.091 1.416 ;
     RECT  90.965 10.992 91.105 21.528 ;
     RECT  91.244 0.528 91.331 1.176 ;
     RECT  89.561 6.048 91.429 9.096 ;
     RECT  91.105 10.368 91.429 21.528 ;
     RECT  91.429 6.048 91.468 21.528 ;
     RECT  91.468 16.032 91.469 21.528 ;
     RECT  91.468 6.048 91.477 15.048 ;
     RECT  90.641 2.976 91.541 4.728 ;
     RECT  91.541 3.792 91.609 4.728 ;
     RECT  91.477 6.048 91.609 15 ;
     RECT  91.469 16.368 91.613 21.528 ;
     RECT  90.785 22.752 91.765 23.304 ;
     RECT  90.785 24.48 91.765 26.808 ;
     RECT  90.785 27.936 91.781 30.456 ;
     RECT  91.001 31.44 91.781 31.944 ;
     RECT  91.765 22.752 91.813 26.808 ;
     RECT  91.781 27.936 91.813 31.944 ;
     RECT  91.813 22.752 91.901 31.944 ;
     RECT  91.901 25.104 91.996 31.944 ;
     RECT  91.331 1.152 92.117 1.176 ;
     RECT  91.901 22.752 92.185 23.688 ;
     RECT  91.996 25.104 92.225 28.824 ;
     RECT  91.525 0.096 92.293 0.12 ;
     RECT  92.225 25.248 92.297 28.824 ;
     RECT  91.613 16.608 92.401 21.528 ;
     RECT  92.401 16.608 92.581 21.672 ;
     RECT  92.185 22.704 92.581 23.688 ;
     RECT  92.581 16.608 92.653 23.688 ;
     RECT  91.609 3.792 92.869 15 ;
     RECT  92.297 25.728 92.873 28.824 ;
     RECT  92.873 25.92 93.013 28.824 ;
     RECT  91.996 29.808 93.013 31.944 ;
     RECT  92.653 16.512 93.193 23.688 ;
     RECT  93.193 16.512 93.301 23.976 ;
     RECT  92.293 0.096 93.449 0.6 ;
     RECT  93.449 0.576 93.589 0.6 ;
     RECT  92.869 3.408 93.949 15 ;
     RECT  93.949 3.36 94.057 15 ;
     RECT  94.057 3.312 94.069 15 ;
     RECT  94.069 3.312 94.129 15.336 ;
     RECT  93.769 1.68 94.163 1.704 ;
     RECT  93.301 16.512 94.201 24.216 ;
     RECT  93.013 25.92 94.201 31.944 ;
     RECT  94.129 3.312 94.208 15.528 ;
     RECT  94.201 16.512 94.208 31.944 ;
     RECT  89.104 35.424 94.208 35.448 ;
     RECT  94.208 2.148 94.312 69.132 ;
     RECT  93.589 0.576 94.316 0.696 ;
     RECT  94.312 2.418 94.504 68.862 ;
     RECT  94.504 31.2 94.529 31.944 ;
     RECT  94.316 0.576 94.597 1.128 ;
     RECT  94.504 3.312 94.637 5.496 ;
     RECT  94.504 6.624 94.637 29.736 ;
     RECT  94.637 6.672 94.643 29.736 ;
     RECT  94.643 18.96 94.673 29.736 ;
     RECT  94.673 18.96 94.739 19.032 ;
     RECT  94.637 3.408 94.745 5.496 ;
     RECT  94.597 0.096 94.925 1.128 ;
     RECT  94.925 0.576 95.125 1.128 ;
     RECT  94.504 35.424 95.219 35.88 ;
     RECT  94.529 31.296 95.285 31.944 ;
     RECT  94.643 6.672 95.321 17.736 ;
     RECT  95.125 0.576 95.365 1.176 ;
     RECT  94.673 20.112 95.393 29.736 ;
     RECT  95.321 6.672 95.429 9.144 ;
     RECT  95.219 35.856 95.459 35.88 ;
     RECT  95.393 20.16 95.465 29.736 ;
     RECT  95.365 0.576 95.501 1.224 ;
     RECT  95.468 40.32 95.555 40.344 ;
     RECT  95.465 20.352 95.609 29.736 ;
     RECT  95.501 1.152 95.653 1.224 ;
     RECT  94.739 18.96 95.677 18.984 ;
     RECT  95.653 1.152 95.681 1.272 ;
     RECT  94.504 44.304 95.701 44.328 ;
     RECT  94.504 67.824 95.701 67.848 ;
     RECT  95.569 45.648 95.747 45.672 ;
     RECT  94.504 51.312 95.747 51.336 ;
     RECT  95.701 66.864 95.747 67.848 ;
     RECT  95.609 20.4 95.753 29.736 ;
     RECT  95.701 43.92 95.788 44.328 ;
     RECT  95.753 20.592 95.789 29.736 ;
     RECT  95.321 10.176 95.795 17.736 ;
     RECT  95.789 25.008 95.897 29.736 ;
     RECT  94.745 3.408 95.965 5.448 ;
     RECT  95.429 6.672 95.965 6.84 ;
     RECT  95.681 1.2 96.035 1.272 ;
     RECT  95.795 13.104 96.037 17.736 ;
     RECT  95.677 18.768 96.037 18.984 ;
     RECT  96.035 1.248 96.041 1.272 ;
     RECT  95.965 3.408 96.049 6.84 ;
     RECT  96.037 13.104 96.401 18.984 ;
     RECT  96.049 6.672 96.545 6.84 ;
     RECT  96.401 13.104 96.545 17.64 ;
     RECT  96.401 18.672 96.545 18.984 ;
     RECT  95.429 7.92 96.829 9.144 ;
     RECT  95.795 10.176 96.829 11.976 ;
     RECT  96.545 13.104 96.833 17.448 ;
     RECT  96.833 13.104 96.869 17.256 ;
     RECT  95.788 44.304 96.897 44.328 ;
     RECT  95.509 38.16 96.899 38.184 ;
     RECT  95.897 25.296 96.941 29.736 ;
     RECT  95.747 66.864 96.947 66.888 ;
     RECT  96.545 6.816 97.045 6.84 ;
     RECT  96.829 7.92 97.045 11.976 ;
     RECT  95.789 20.592 97.157 23.88 ;
     RECT  97.109 1.728 97.193 1.752 ;
     RECT  96.805 61.008 97.193 61.032 ;
     RECT  97.045 6.816 97.221 11.976 ;
     RECT  97.221 9.12 97.261 11.976 ;
     RECT  96.869 13.104 97.261 17.112 ;
     RECT  96.941 25.296 97.292 28.824 ;
     RECT  97.292 24.864 97.301 28.824 ;
     RECT  97.009 55.824 97.369 55.848 ;
     RECT  97.157 20.592 97.379 23.832 ;
     RECT  97.301 24.864 97.379 28.152 ;
     RECT  95.701 50.112 97.379 50.136 ;
     RECT  97.379 20.592 97.405 23.64 ;
     RECT  96.901 65.616 97.405 65.64 ;
     RECT  97.333 48.432 97.42 48.456 ;
     RECT  97.34 54.096 97.427 54.12 ;
     RECT  96.853 37.008 97.445 37.032 ;
     RECT  97.369 55.296 97.453 55.848 ;
     RECT  97.453 55.824 97.475 55.848 ;
     RECT  94.504 56.88 97.475 56.904 ;
     RECT  97.388 59.664 97.475 59.688 ;
     RECT  95.497 62.976 97.475 63 ;
     RECT  97.405 65.616 97.475 65.784 ;
     RECT  96.829 32.352 97.477 32.376 ;
     RECT  97.405 20.448 97.513 23.64 ;
     RECT  97.429 61.296 97.517 61.32 ;
     RECT  96.049 3.408 97.585 5.544 ;
     RECT  97.221 6.816 97.585 8.04 ;
     RECT  97.261 9.12 97.589 17.112 ;
     RECT  97.477 32.352 97.619 33.096 ;
     RECT  96.545 18.96 97.621 18.984 ;
     RECT  97.585 3.408 97.661 8.04 ;
     RECT  97.379 25.776 97.763 28.152 ;
     RECT  97.621 18.864 97.765 18.984 ;
     RECT  97.765 18.576 97.805 18.984 ;
     RECT  97.589 10.608 97.877 17.112 ;
     RECT  95.893 0.096 97.909 0.168 ;
     RECT  97.333 46.752 98.053 46.776 ;
     RECT  97.877 13.152 98.057 17.112 ;
     RECT  95.509 42.864 98.099 42.888 ;
     RECT  97.873 44.784 98.099 44.808 ;
     RECT  98.053 46.752 98.099 47.208 ;
     RECT  97.877 11.712 98.129 11.976 ;
     RECT  98.057 14.352 98.237 17.112 ;
     RECT  97.877 10.608 98.309 10.632 ;
     RECT  98.237 16.032 98.309 17.112 ;
     RECT  98.129 11.712 98.381 11.736 ;
     RECT  97.513 20.352 98.381 23.64 ;
     RECT  97.909 0.096 98.489 0.84 ;
     RECT  97.661 3.456 98.521 8.04 ;
     RECT  97.589 9.12 98.521 9.144 ;
     RECT  98.237 14.352 98.525 14.856 ;
     RECT  97.763 25.776 98.525 26.952 ;
     RECT  98.489 0.816 98.557 0.84 ;
     RECT  97.405 30 98.557 30.216 ;
     RECT  98.521 3.456 98.561 9.144 ;
     RECT  98.525 14.352 98.561 14.808 ;
     RECT  98.381 20.352 98.593 23.352 ;
     RECT  97.619 33.072 98.765 33.096 ;
     RECT  97.805 18.576 98.953 18.6 ;
     RECT  98.557 0.816 98.965 1.128 ;
     RECT  98.953 18.24 98.989 18.6 ;
     RECT  98.989 24.624 99.02 24.648 ;
     RECT  98.525 25.776 99.02 26.472 ;
     RECT  99.02 24.624 99.493 26.472 ;
     RECT  97.763 28.032 99.493 28.152 ;
     RECT  98.561 4.08 99.608 9.144 ;
     RECT  98.057 13.152 99.608 13.32 ;
     RECT  98.561 14.4 99.608 14.808 ;
     RECT  98.309 16.032 99.608 16.056 ;
     RECT  98.309 17.088 99.608 17.112 ;
     RECT  98.989 18.24 99.608 18.84 ;
     RECT  98.593 19.872 99.608 23.352 ;
     RECT  99.493 24.624 99.608 28.152 ;
     RECT  98.557 29.376 99.608 30.216 ;
     RECT  98.765 33.072 99.608 33.624 ;
     RECT  98.773 35.328 99.608 35.352 ;
     RECT  98.053 41.568 99.608 41.592 ;
     RECT  98.099 47.184 99.608 47.208 ;
     RECT  97.381 52.992 99.608 53.016 ;
     RECT  97.429 58.464 99.608 58.488 ;
     RECT  98.869 64.368 99.608 64.392 ;
     RECT  97.475 65.76 99.608 65.784 ;
     RECT  99.025 68.4 99.608 68.424 ;
     RECT  99.608 2.148 99.712 69.132 ;
     RECT  98.965 0.816 99.785 1.176 ;
     RECT  99.712 2.418 99.904 68.862 ;
     RECT  99.904 22.752 100.001 22.776 ;
     RECT  99.904 14.112 100.019 16.008 ;
     RECT  100.019 14.112 100.073 14.136 ;
     RECT  99.904 7.392 100.109 8.04 ;
     RECT  99.785 1.152 100.145 1.176 ;
     RECT  99.904 24.624 100.217 25.8 ;
     RECT  99.904 4.512 100.289 6.312 ;
     RECT  99.904 18.24 100.289 18.84 ;
     RECT  99.904 19.872 100.396 20.568 ;
     RECT  100.289 18.24 100.433 18.264 ;
     RECT  100.396 19.872 100.433 19.896 ;
     RECT  100.217 25.776 100.433 25.8 ;
     RECT  100.289 4.656 100.897 6.312 ;
     RECT  99.904 3.312 100.901 3.336 ;
     RECT  100.897 4.656 100.937 6.888 ;
     RECT  100.933 2.832 100.969 2.856 ;
     RECT  100.937 6 101.045 6.888 ;
     RECT  100.969 2.736 101.189 2.856 ;
     RECT  100.109 8.016 101.225 8.04 ;
     RECT  101.977 39.984 103.561 40.008 ;
     RECT  103.561 39.888 103.601 40.008 ;
     RECT  102.481 1.68 103.644 1.704 ;
     RECT  103.561 3.12 103.644 3.144 ;
     RECT  103.525 4.512 103.644 4.536 ;
     RECT  101.977 5.952 103.644 5.976 ;
     RECT  103.561 7.344 103.644 7.368 ;
     RECT  101.905 8.784 103.644 8.808 ;
     RECT  102.013 10.176 103.644 10.2 ;
     RECT  101.905 11.616 103.644 11.64 ;
     RECT  101.905 13.008 103.644 13.032 ;
     RECT  101.473 14.4 103.644 14.424 ;
     RECT  102.013 15.84 103.644 15.864 ;
     RECT  102.553 17.232 103.644 17.256 ;
     RECT  102.553 18.672 103.644 18.696 ;
     RECT  101.977 20.064 103.644 20.088 ;
     RECT  102.553 21.504 103.644 21.528 ;
     RECT  102.013 22.896 103.644 22.92 ;
     RECT  102.553 24.336 103.644 24.36 ;
     RECT  102.553 25.728 103.644 25.752 ;
     RECT  102.553 27.168 103.644 27.192 ;
     RECT  102.589 28.56 103.644 28.584 ;
     RECT  102.553 29.952 103.644 29.976 ;
     RECT  101.977 31.392 103.644 31.416 ;
     RECT  101.977 32.784 103.644 32.808 ;
     RECT  101.977 34.224 103.644 34.248 ;
     RECT  102.553 35.616 103.644 35.64 ;
     RECT  101.905 37.056 103.644 37.08 ;
     RECT  101.977 38.448 103.644 38.472 ;
     RECT  103.601 39.888 103.644 39.912 ;
     RECT  102.553 41.28 103.644 41.304 ;
     RECT  102.553 42.72 103.644 42.744 ;
     RECT  101.437 44.112 103.644 44.136 ;
     RECT  102.553 45.504 103.644 45.528 ;
     RECT  101.473 46.944 103.644 46.968 ;
     RECT  101.365 48.336 103.644 48.36 ;
     RECT  101.977 49.776 103.644 49.8 ;
     RECT  102.553 51.168 103.644 51.192 ;
     RECT  102.553 52.608 103.644 52.632 ;
     RECT  101.905 54 103.644 54.024 ;
     RECT  101.977 55.44 103.644 55.464 ;
     RECT  102.553 56.832 103.644 56.856 ;
     RECT  102.553 58.272 103.644 58.296 ;
     RECT  102.553 59.664 103.644 59.688 ;
     RECT  101.905 61.056 103.644 61.08 ;
     RECT  101.977 62.496 103.644 62.52 ;
     RECT  102.553 63.888 103.644 63.912 ;
     RECT  101.977 65.328 103.644 65.352 ;
     RECT  101.905 66.72 103.644 66.744 ;
     RECT  101.437 68.16 103.644 68.184 ;
     RECT  100.789 69.552 103.644 69.576 ;
    LAYER M5 ;
     RECT  42 0.016 49.944 0.085 ;
     RECT  74.688 0.016 82.632 0.131 ;
     RECT  91.056 0.016 99 0.179 ;
     RECT  58.32 0.016 66.264 0.611 ;
     RECT  91.056 0.179 95.688 0.611 ;
     RECT  97.152 0.179 99 0.851 ;
     RECT  93.36 0.611 95.688 1.139 ;
     RECT  98.688 0.851 99 1.139 ;
     RECT  25.632 0.016 33.576 1.187 ;
     RECT  58.32 0.611 61.944 1.187 ;
     RECT  74.928 0.131 82.632 1.187 ;
     RECT  91.056 0.611 92.088 1.187 ;
     RECT  95.136 1.139 95.688 1.187 ;
     RECT  98.976 1.139 99 1.187 ;
     RECT  95.376 1.187 95.688 1.189 ;
     RECT  95.376 1.189 96.024 1.235 ;
     RECT  95.664 1.235 96.024 1.283 ;
     RECT  91.056 1.187 91.08 1.427 ;
     RECT  9.312 0.016 17.256 1.763 ;
     RECT  25.92 1.187 33.576 1.763 ;
     RECT  42 0.085 50.616 1.763 ;
     RECT  58.32 1.187 61.92 1.763 ;
     RECT  62.928 0.611 66.264 1.763 ;
     RECT  74.928 1.187 82.392 1.763 ;
     RECT  97.152 0.851 97.176 1.763 ;
     RECT  11.568 1.763 15.192 1.811 ;
     RECT  43.776 1.763 44.328 1.811 ;
     RECT  45.312 1.763 47.112 1.811 ;
     RECT  60.912 1.763 61.92 1.811 ;
     RECT  82.08 1.763 82.104 1.811 ;
     RECT  14.64 1.811 14.664 1.859 ;
     RECT  80.832 1.763 81.096 1.859 ;
     RECT  50.592 1.763 50.616 2.137 ;
     RECT  93.36 1.139 94.152 2.137 ;
     RECT  2.4 2.137 2.52 2.151 ;
     RECT  7.8 2.137 7.92 2.151 ;
     RECT  18.6 2.137 18.72 2.151 ;
     RECT  24 2.137 24.12 2.151 ;
     RECT  34.8 2.137 34.92 2.151 ;
     RECT  40.2 2.137 40.32 2.151 ;
     RECT  50.592 2.137 51.12 2.151 ;
     RECT  56.4 2.137 56.52 2.151 ;
     RECT  61.8 1.811 61.92 2.151 ;
     RECT  67.2 2.137 67.32 2.151 ;
     RECT  72.6 2.137 72.72 2.151 ;
     RECT  83.4 2.137 83.52 2.151 ;
     RECT  88.8 2.137 88.92 2.151 ;
     RECT  93.36 2.137 94.32 2.151 ;
     RECT  99.6 2.137 99.72 2.151 ;
     RECT  18.6 2.151 18.912 2.245 ;
     RECT  45.6 1.811 47.112 2.773 ;
     RECT  29.28 1.763 31.032 2.867 ;
     RECT  9.792 1.763 9.816 2.915 ;
     RECT  11.568 1.811 13.512 2.915 ;
     RECT  27.168 1.763 27.192 2.915 ;
     RECT  29.4 2.867 31.032 2.915 ;
     RECT  32.016 1.763 32.568 2.915 ;
     RECT  43.776 1.811 43.8 2.915 ;
     RECT  45.504 2.773 47.112 2.915 ;
     RECT  48.384 1.763 48.648 2.915 ;
     RECT  59.376 1.763 59.4 2.915 ;
     RECT  63.696 1.763 63.816 2.915 ;
     RECT  76.752 1.763 78.312 2.915 ;
     RECT  80.832 1.859 80.856 2.915 ;
     RECT  40.2 2.151 40.512 3.109 ;
     RECT  48.384 2.915 48.408 3.157 ;
     RECT  4.464 2.821 4.488 3.301 ;
     RECT  56.4 2.151 56.712 3.349 ;
     RECT  34.8 2.151 35.112 3.397 ;
     RECT  18.336 2.245 18.912 3.443 ;
     RECT  48.288 3.157 48.408 3.443 ;
     RECT  32.544 2.915 32.568 3.491 ;
     RECT  48.288 3.443 48.312 3.491 ;
     RECT  34.176 3.397 35.112 3.637 ;
     RECT  37.056 3.301 37.08 3.731 ;
     RECT  21.408 2.821 21.432 3.925 ;
     RECT  45.504 2.915 46.344 3.925 ;
     RECT  78 2.915 78.312 3.925 ;
     RECT  83.4 2.151 83.712 3.925 ;
     RECT  29.4 2.915 29.712 4.021 ;
     RECT  40.08 3.109 40.512 4.021 ;
     RECT  45.408 3.925 46.344 4.117 ;
     RECT  54.144 3.877 54.168 4.117 ;
     RECT  77.328 3.925 78.312 4.213 ;
     RECT  93.36 2.151 94.512 4.213 ;
     RECT  29.088 4.021 29.712 4.259 ;
     RECT  53.04 4.117 53.064 4.259 ;
     RECT  24 2.151 24.312 4.309 ;
     RECT  29.28 4.259 29.712 4.355 ;
     RECT  38.688 3.541 38.712 4.357 ;
     RECT  54.048 4.117 54.168 4.501 ;
     RECT  93.024 4.213 94.512 4.549 ;
     RECT  4.272 3.301 4.488 4.595 ;
     RECT  37.824 4.357 38.712 4.645 ;
     RECT  39.984 4.021 40.512 4.645 ;
     RECT  31.344 3.541 31.368 4.693 ;
     RECT  93.024 4.549 94.68 4.835 ;
     RECT  34.176 3.637 35.208 4.837 ;
     RECT  45.408 4.117 46.728 4.885 ;
     RECT  56.4 3.349 57.624 4.885 ;
     RECT  76.944 4.213 78.312 4.931 ;
     RECT  37.824 4.645 40.512 4.933 ;
     RECT  56.256 4.885 57.624 4.981 ;
     RECT  88.8 2.151 89.112 5.029 ;
     RECT  44.784 4.885 46.728 5.075 ;
     RECT  61.8 2.151 62.112 5.077 ;
     RECT  56.112 4.981 57.624 5.123 ;
     RECT  93.36 4.835 94.68 5.123 ;
     RECT  31.344 4.693 31.56 5.125 ;
     RECT  37.824 4.933 41.208 5.125 ;
     RECT  21.312 3.925 21.432 5.171 ;
     RECT  34.176 4.837 35.352 5.171 ;
     RECT  37.056 5.125 41.208 5.171 ;
     RECT  13.104 2.915 13.512 5.173 ;
     RECT  72.6 2.151 72.912 5.173 ;
     RECT  21.408 5.171 21.432 5.267 ;
     RECT  44.976 5.075 46.728 5.315 ;
     RECT  4.464 4.595 4.488 5.317 ;
     RECT  61.2 5.077 62.112 5.317 ;
     RECT  11.088 5.173 11.112 5.365 ;
     RECT  18.6 3.443 18.912 5.365 ;
     RECT  65.904 4.645 65.928 5.365 ;
     RECT  67.2 2.151 67.512 5.365 ;
     RECT  45.6 5.315 46.728 5.461 ;
     RECT  80.928 5.269 80.952 5.507 ;
     RECT  34.8 5.171 35.352 5.509 ;
     RECT  37.056 5.171 37.224 5.509 ;
     RECT  34.8 5.509 37.224 5.555 ;
     RECT  65.904 5.365 67.512 5.555 ;
     RECT  31.296 5.125 31.56 5.605 ;
     RECT  32.976 4.453 33 5.605 ;
     RECT  31.296 5.605 33 5.699 ;
     RECT  34.8 5.555 36.264 5.699 ;
     RECT  68.544 5.509 68.568 5.701 ;
     RECT  25.44 4.645 25.464 5.747 ;
     RECT  38.688 5.171 41.208 5.747 ;
     RECT  47.856 5.029 47.88 5.749 ;
     RECT  72.6 5.173 73.224 5.749 ;
     RECT  93.36 5.123 94.512 5.845 ;
     RECT  43.296 5.749 43.32 5.891 ;
     RECT  48.912 5.173 48.936 5.939 ;
     RECT  4.464 5.317 4.584 5.989 ;
     RECT  7.8 2.151 8.112 5.989 ;
     RECT  47.856 5.749 47.928 6.035 ;
     RECT  91.776 4.165 91.8 6.083 ;
     RECT  53.184 4.501 55.08 6.179 ;
     RECT  45.6 5.461 46.776 6.181 ;
     RECT  47.856 6.035 47.88 6.181 ;
     RECT  3.84 5.989 4.584 6.323 ;
     RECT  11.088 5.365 11.496 6.323 ;
     RECT  53.568 6.179 55.08 6.323 ;
     RECT  96 1.283 96.024 6.323 ;
     RECT  34.8 5.699 35.352 6.371 ;
     RECT  39.6 5.747 41.208 6.371 ;
     RECT  34.8 6.371 35.256 6.419 ;
     RECT  54.288 6.323 55.08 6.467 ;
     RECT  23.904 4.309 24.312 6.517 ;
     RECT  13.104 5.173 14.136 6.659 ;
     RECT  85.488 5.269 85.512 6.661 ;
     RECT  77.328 4.931 78.312 6.755 ;
     RECT  15.888 4.501 15.912 6.757 ;
     RECT  66 5.555 67.512 6.803 ;
     RECT  7.8 5.989 8.232 6.805 ;
     RECT  40.08 6.371 41.208 6.805 ;
     RECT  45.6 6.181 47.88 6.805 ;
     RECT  11.088 6.323 11.112 6.851 ;
     RECT  40.08 6.805 41.736 6.851 ;
     RECT  45.024 6.805 47.88 6.851 ;
     RECT  88.368 5.029 89.112 6.851 ;
     RECT  61.152 5.317 62.112 6.899 ;
     RECT  93.168 5.845 94.512 6.899 ;
     RECT  45.024 6.851 46.344 6.947 ;
     RECT  68.544 5.701 68.712 7.043 ;
     RECT  74.832 5.221 74.856 7.043 ;
     RECT  50.592 2.151 51.312 7.093 ;
     RECT  66.672 6.803 67.512 7.093 ;
     RECT  68.544 7.043 68.568 7.093 ;
     RECT  29.4 4.355 29.712 7.141 ;
     RECT  31.152 6.229 31.176 7.141 ;
     RECT  2.4 2.151 2.712 7.237 ;
     RECT  3.84 6.323 3.864 7.237 ;
     RECT  47.568 6.851 47.88 7.237 ;
     RECT  94.2 6.899 94.512 7.237 ;
     RECT  2.4 7.237 3.864 7.283 ;
     RECT  66.672 7.093 68.568 7.283 ;
     RECT  72.48 5.749 73.224 7.331 ;
     RECT  15.888 6.757 16.488 7.333 ;
     RECT  29.4 7.141 31.176 7.379 ;
     RECT  34.8 6.419 35.208 7.381 ;
     RECT  88.656 6.851 89.112 7.427 ;
     RECT  7.344 6.805 8.232 7.429 ;
     RECT  47.568 7.237 48.456 7.475 ;
     RECT  63.792 2.915 63.816 7.477 ;
     RECT  82.08 7.429 82.104 7.477 ;
     RECT  83.28 3.925 83.712 7.477 ;
     RECT  5.424 7.477 5.448 7.619 ;
     RECT  36.912 6.805 36.936 7.619 ;
     RECT  54.288 6.467 54.312 7.619 ;
     RECT  31.152 7.379 31.176 7.765 ;
     RECT  32.16 5.699 33 7.765 ;
     RECT  23.664 6.517 24.312 7.811 ;
     RECT  31.152 7.765 33 7.811 ;
     RECT  41.712 6.851 41.736 7.907 ;
     RECT  63.792 7.477 63.864 7.907 ;
     RECT  13.2 6.659 14.136 7.909 ;
     RECT  45.6 6.947 46.344 7.909 ;
     RECT  93.168 6.899 93.192 7.909 ;
     RECT  82.08 7.477 83.712 7.955 ;
     RECT  83.28 7.955 83.712 7.957 ;
     RECT  2.4 7.283 3.432 8.003 ;
     RECT  83.28 7.957 84.024 8.005 ;
     RECT  85.392 6.661 85.512 8.005 ;
     RECT  49.488 7.429 49.512 8.051 ;
     RECT  26.448 6.277 26.472 8.053 ;
     RECT  82.08 7.955 82.2 8.147 ;
     RECT  92.256 7.909 93.192 8.149 ;
     RECT  94.2 7.237 95.256 8.149 ;
     RECT  76.944 8.005 76.968 8.195 ;
     RECT  87.072 8.005 87.096 8.195 ;
     RECT  92.256 8.149 95.256 8.195 ;
     RECT  97.152 5.461 97.176 8.195 ;
     RECT  83.28 8.005 85.512 8.243 ;
     RECT  31.296 7.811 33 8.245 ;
     RECT  40.08 6.851 40.512 8.245 ;
     RECT  42.816 7.909 42.84 8.245 ;
     RECT  13.2 7.909 14.232 8.293 ;
     RECT  56.256 5.123 57.624 8.339 ;
     RECT  50.496 7.093 51.312 8.437 ;
     RECT  99.6 2.151 99.912 8.437 ;
     RECT  82.176 8.147 82.2 8.483 ;
     RECT  47.568 7.475 48.216 8.485 ;
     RECT  83.28 8.243 84.072 8.531 ;
     RECT  91.2 7.189 91.224 8.531 ;
     RECT  71.52 7.765 71.544 8.533 ;
     RECT  31.296 8.245 33.048 8.579 ;
     RECT  70.752 8.533 71.544 8.579 ;
     RECT  70.752 8.579 70.776 8.675 ;
     RECT  44.064 7.621 44.088 8.771 ;
     RECT  37.2 8.293 37.224 8.773 ;
     RECT  45.456 7.909 46.344 8.819 ;
     RECT  34.416 7.381 35.208 8.869 ;
     RECT  12.672 8.293 14.232 8.965 ;
     RECT  15.84 7.333 16.488 8.965 ;
     RECT  25.632 8.053 26.472 9.011 ;
     RECT  37.008 8.773 37.224 9.011 ;
     RECT  18.6 5.365 19.032 9.013 ;
     RECT  53.04 7.813 53.064 9.013 ;
     RECT  63.792 7.907 63.816 9.013 ;
     RECT  78 6.755 78.312 9.013 ;
     RECT  88.8 7.427 89.112 9.061 ;
     RECT  12.672 8.965 16.488 9.107 ;
     RECT  37.008 9.011 37.032 9.107 ;
     RECT  25.632 9.011 25.656 9.155 ;
     RECT  45.6 8.819 46.344 9.155 ;
     RECT  53.04 9.013 53.16 9.155 ;
     RECT  72.6 7.331 73.224 9.155 ;
     RECT  93.408 8.195 95.256 9.155 ;
     RECT  98.832 8.437 99.912 9.155 ;
     RECT  13.2 9.107 16.488 9.203 ;
     RECT  42.816 8.245 43.08 9.203 ;
     RECT  45.6 9.155 46.2 9.299 ;
     RECT  31.968 8.579 33.048 9.301 ;
     RECT  34.224 8.869 35.208 9.301 ;
     RECT  7.056 7.429 8.232 9.395 ;
     RECT  21.648 7.381 21.672 9.395 ;
     RECT  68.544 7.283 68.568 9.397 ;
     RECT  42.816 9.203 42.84 9.541 ;
     RECT  83.28 8.531 84.024 9.541 ;
     RECT  31.968 9.301 35.208 9.637 ;
     RECT  36.864 9.253 36.888 9.637 ;
     RECT  63.696 9.013 63.816 9.637 ;
     RECT  13.2 9.203 15.96 9.731 ;
     RECT  31.968 9.637 36.888 9.731 ;
     RECT  42.144 9.541 42.84 9.731 ;
     RECT  53.136 9.155 53.16 9.731 ;
     RECT  56.256 8.339 57.576 9.731 ;
     RECT  88.704 9.061 89.112 9.731 ;
     RECT  47.568 8.485 49.128 9.779 ;
     RECT  66.672 7.283 67.512 9.781 ;
     RECT  83.232 9.541 84.024 9.781 ;
     RECT  85.392 8.243 85.512 9.827 ;
     RECT  24 7.811 24.312 9.877 ;
     RECT  3.984 9.061 4.008 9.923 ;
     RECT  66.624 9.781 67.512 9.923 ;
     RECT  17.616 9.013 19.032 9.925 ;
     RECT  83.04 9.781 84.024 9.925 ;
     RECT  70.464 9.253 70.488 10.067 ;
     RECT  42.144 9.731 42.168 10.069 ;
     RECT  92.256 8.195 92.28 10.069 ;
     RECT  42.048 10.069 42.168 10.211 ;
     RECT  31.968 9.731 35.928 10.259 ;
     RECT  13.2 9.731 14.232 10.307 ;
     RECT  47.76 9.779 49.128 10.307 ;
     RECT  63.696 9.637 64.68 10.307 ;
     RECT  68.496 9.397 68.568 10.307 ;
     RECT  92.16 10.069 92.28 10.307 ;
     RECT  56.256 9.731 56.712 10.405 ;
     RECT  37.056 10.213 37.08 10.499 ;
     RECT  59.088 7.909 59.112 10.693 ;
     RECT  4.032 10.213 4.056 10.883 ;
     RECT  23.376 9.877 24.312 10.883 ;
     RECT  34.224 10.259 35.928 10.883 ;
     RECT  93.408 9.155 95.16 10.883 ;
     RECT  97.392 9.637 97.416 10.883 ;
     RECT  9.648 7.957 9.672 10.931 ;
     RECT  55.44 10.405 56.712 10.933 ;
     RECT  77.904 9.013 78.312 10.981 ;
     RECT  92.16 10.307 92.184 11.027 ;
     RECT  16.992 9.925 19.032 11.123 ;
     RECT  53.232 10.213 53.256 11.171 ;
     RECT  76.944 10.981 78.312 11.171 ;
     RECT  45.6 9.299 45.912 11.173 ;
     RECT  7.296 9.395 8.232 11.221 ;
     RECT  7.296 11.221 8.52 11.267 ;
     RECT  43.584 10.789 43.608 11.317 ;
     RECT  83.04 9.925 84.12 11.365 ;
     RECT  31.968 10.259 32.568 11.413 ;
     RECT  68.544 10.307 68.568 11.461 ;
     RECT  17.616 11.123 19.032 11.555 ;
     RECT  55.344 10.933 56.712 11.651 ;
     RECT  2.4 8.003 2.712 11.701 ;
     RECT  42.144 10.211 42.168 11.701 ;
     RECT  43.584 11.317 43.704 11.845 ;
     RECT  31.968 11.413 33.144 11.891 ;
     RECT  41.568 11.701 42.168 11.939 ;
     RECT  13.2 10.307 13.512 11.941 ;
     RECT  55.44 11.651 56.712 11.941 ;
     RECT  85.392 9.827 85.416 11.987 ;
     RECT  13.2 11.941 13.608 11.989 ;
     RECT  47.856 10.307 48.312 12.035 ;
     RECT  68.544 11.461 69.288 12.035 ;
     RECT  69.264 12.035 69.288 12.133 ;
     RECT  7.8 11.267 8.52 12.229 ;
     RECT  45.6 11.173 46.248 12.325 ;
     RECT  72.6 9.155 72.912 12.325 ;
     RECT  43.584 11.845 44.568 12.419 ;
     RECT  43.68 12.419 44.568 12.421 ;
     RECT  45.6 12.325 46.728 12.421 ;
     RECT  7.8 12.229 9.144 12.515 ;
     RECT  31.968 11.891 32.568 12.517 ;
     RECT  39.168 8.245 40.512 12.517 ;
     RECT  41.568 11.939 41.592 12.517 ;
     RECT  43.68 12.421 46.728 12.517 ;
     RECT  53.568 11.941 53.592 12.517 ;
     RECT  77.904 11.171 78.312 12.517 ;
     RECT  13.104 11.989 13.608 12.563 ;
     RECT  39.168 12.517 41.592 12.563 ;
     RECT  90.48 11.941 90.504 12.563 ;
     RECT  93.408 10.883 94.512 12.563 ;
     RECT  13.104 12.563 13.512 12.611 ;
     RECT  92.016 11.365 92.04 12.707 ;
     RECT  7.8 12.515 8.52 12.755 ;
     RECT  53.568 12.517 53.976 12.755 ;
     RECT  79.296 10.165 79.32 12.755 ;
     RECT  95.76 11.941 95.784 12.755 ;
     RECT  61.44 6.899 62.112 12.757 ;
     RECT  63.696 10.307 63.72 12.757 ;
     RECT  39.168 12.563 41.256 12.803 ;
     RECT  43.68 12.517 46.824 12.901 ;
     RECT  59.088 10.693 59.208 12.997 ;
     RECT  43.68 12.901 46.872 13.045 ;
     RECT  47.856 12.035 48.168 13.045 ;
     RECT  66.672 9.923 67.512 13.045 ;
     RECT  2.304 11.701 2.712 13.091 ;
     RECT  77.568 12.517 78.312 13.091 ;
     RECT  31.728 12.517 32.568 13.093 ;
     RECT  31.728 13.093 33.096 13.139 ;
     RECT  50.208 8.437 51.312 13.139 ;
     RECT  81.984 12.517 82.008 13.139 ;
     RECT  83.04 11.365 84.216 13.139 ;
     RECT  33.072 13.139 33.096 13.189 ;
     RECT  34.416 10.883 35.928 13.189 ;
     RECT  33.072 13.189 35.928 13.235 ;
     RECT  60.576 12.757 62.112 13.477 ;
     RECT  33.552 13.235 35.928 13.523 ;
     RECT  66.096 13.045 67.512 13.525 ;
     RECT  88.8 9.731 89.112 13.573 ;
     RECT  13.2 12.611 13.512 13.621 ;
     RECT  85.2 13.189 85.224 13.621 ;
     RECT  97.728 11.221 97.752 13.621 ;
     RECT  72.6 12.325 73.656 13.715 ;
     RECT  58.656 12.997 59.208 13.811 ;
     RECT  85.2 13.621 85.752 13.861 ;
     RECT  31.968 13.139 31.992 13.955 ;
     RECT  60.576 13.477 62.568 14.101 ;
     RECT  63.552 12.757 63.72 14.101 ;
     RECT  99.456 9.155 99.912 14.101 ;
     RECT  33.552 13.523 35.208 14.195 ;
     RECT  77.856 13.091 78.312 14.195 ;
     RECT  85.2 13.861 85.8 14.195 ;
     RECT  53.952 12.755 53.976 14.197 ;
     RECT  59.088 13.811 59.208 14.197 ;
     RECT  66.096 13.525 67.752 14.245 ;
     RECT  69.264 12.133 69.816 14.245 ;
     RECT  15.936 9.731 15.96 14.291 ;
     RECT  81.456 13.525 81.48 14.291 ;
     RECT  85.728 14.195 85.8 14.291 ;
     RECT  88.704 13.573 89.112 14.291 ;
     RECT  37.056 13.093 37.08 14.387 ;
     RECT  85.776 14.291 85.8 14.485 ;
     RECT  85.776 14.485 86.088 14.531 ;
     RECT  13.2 13.621 14.184 14.675 ;
     RECT  66.096 14.245 69.816 14.723 ;
     RECT  7.8 12.755 8.112 14.725 ;
     RECT  94.08 12.563 94.512 14.725 ;
     RECT  7.392 14.725 8.112 14.773 ;
     RECT  72.6 13.715 72.912 14.773 ;
     RECT  88.8 14.291 89.112 14.773 ;
     RECT  97.392 13.621 97.752 14.819 ;
     RECT  66.096 14.723 69.288 14.867 ;
     RECT  10.8 14.821 10.824 15.011 ;
     RECT  53.808 14.197 53.976 15.011 ;
     RECT  91.44 14.773 91.464 15.059 ;
     RECT  24 10.883 24.312 15.061 ;
     RECT  34.416 14.195 35.208 15.251 ;
     RECT  50.352 13.139 51.312 15.253 ;
     RECT  12 14.869 12.024 15.299 ;
     RECT  83.28 13.139 84.216 15.301 ;
     RECT  15.216 14.533 15.24 15.349 ;
     RECT  79.776 14.581 79.8 15.349 ;
     RECT  59.088 14.197 59.304 15.397 ;
     RECT  55.44 11.941 57.24 15.443 ;
     RECT  66.672 14.867 69.288 15.443 ;
     RECT  71.568 14.773 71.592 15.443 ;
     RECT  23.376 15.061 24.312 15.493 ;
     RECT  29.4 7.379 29.712 15.541 ;
     RECT  7.392 14.773 8.904 15.683 ;
     RECT  39.216 12.803 41.256 15.685 ;
     RECT  42.432 13.861 42.456 15.685 ;
     RECT  68.976 15.443 69.288 15.829 ;
     RECT  72.6 14.773 73.56 15.829 ;
     RECT  79.728 15.349 79.8 15.829 ;
     RECT  39.216 15.685 42.456 15.877 ;
     RECT  43.68 13.045 48.168 15.877 ;
     RECT  53.856 15.011 53.976 15.971 ;
     RECT  78 14.195 78.312 15.973 ;
     RECT  79.728 15.829 80.088 15.973 ;
     RECT  7.392 15.683 8.112 16.019 ;
     RECT  87.408 14.773 87.432 16.019 ;
     RECT  99.456 14.101 100.008 16.019 ;
     RECT  23.376 15.493 25.128 16.067 ;
     RECT  29.04 15.541 29.712 16.115 ;
     RECT  86.064 14.531 86.088 16.259 ;
     RECT  4.224 15.301 4.248 16.307 ;
     RECT  22.32 15.397 22.344 16.357 ;
     RECT  91.392 15.301 91.416 16.403 ;
     RECT  22.224 16.357 22.344 16.453 ;
     RECT  23.376 16.067 24.312 16.453 ;
     RECT  27.024 15.973 27.048 16.453 ;
     RECT  32.16 15.877 32.184 16.453 ;
     RECT  10.848 15.637 10.872 16.499 ;
     RECT  22.224 16.453 24.312 16.499 ;
     RECT  32.16 16.453 33.048 16.501 ;
     RECT  34.416 15.251 35.112 16.501 ;
     RECT  15.216 15.349 16.008 16.547 ;
     RECT  81.984 15.733 82.008 16.547 ;
     RECT  78 15.973 80.088 16.549 ;
     RECT  83.088 15.301 84.216 16.549 ;
     RECT  76.944 15.349 76.968 16.595 ;
     RECT  68.976 15.829 69.864 16.643 ;
     RECT  71.76 15.829 73.56 16.645 ;
     RECT  74.784 15.877 74.808 16.645 ;
     RECT  13.2 14.675 13.512 16.693 ;
     RECT  38.208 16.453 38.232 16.789 ;
     RECT  39.216 15.877 48.168 16.789 ;
     RECT  66.672 15.443 67.512 16.789 ;
     RECT  15.216 16.547 15.24 16.835 ;
     RECT  22.32 16.499 24.312 16.835 ;
     RECT  60.576 14.101 63.72 16.835 ;
     RECT  97.728 14.819 97.752 16.837 ;
     RECT  97.728 16.837 98.04 16.883 ;
     RECT  78 16.549 80.424 16.885 ;
     RECT  38.208 16.789 48.168 16.931 ;
     RECT  78 16.885 81 16.979 ;
     RECT  17.616 11.555 18.912 16.981 ;
     RECT  9.12 16.885 9.144 17.029 ;
     RECT  32.16 16.501 35.112 17.029 ;
     RECT  39.744 16.931 48.168 17.029 ;
     RECT  9.12 17.029 9.528 17.075 ;
     RECT  21.12 16.405 21.144 17.077 ;
     RECT  22.608 16.835 24.312 17.077 ;
     RECT  58.704 15.397 59.304 17.077 ;
     RECT  60.576 16.835 62.112 17.077 ;
     RECT  32.16 17.029 35.736 17.123 ;
     RECT  79.728 16.979 81 17.123 ;
     RECT  7.8 16.019 8.112 17.125 ;
     RECT  39.744 17.029 48.456 17.171 ;
     RECT  79.728 17.123 80.904 17.267 ;
     RECT  17.088 16.981 18.912 17.411 ;
     RECT  13.2 16.693 13.608 17.459 ;
     RECT  58.704 17.077 62.112 17.461 ;
     RECT  71.76 16.645 74.808 17.461 ;
     RECT  86.64 16.789 86.664 17.461 ;
     RECT  38.208 16.931 38.76 17.507 ;
     RECT  86.544 17.461 86.664 17.603 ;
     RECT  5.28 16.885 5.304 17.605 ;
     RECT  13.2 17.459 13.512 17.605 ;
     RECT  29.4 16.115 29.712 17.605 ;
     RECT  33.792 17.123 35.736 17.605 ;
     RECT  49.824 15.253 51.312 17.605 ;
     RECT  92.544 17.461 92.568 17.605 ;
     RECT  94.08 14.725 95.448 17.605 ;
     RECT  88.8 14.773 89.928 17.651 ;
     RECT  92.448 17.605 92.568 17.651 ;
     RECT  94.08 17.605 95.736 17.651 ;
     RECT  76.368 17.077 76.392 17.699 ;
     RECT  66.528 16.789 67.512 17.845 ;
     RECT  69.12 16.643 69.864 17.845 ;
     RECT  55.44 15.443 56.712 17.893 ;
     RECT  58.368 17.461 62.112 17.987 ;
     RECT  17.088 17.411 17.352 17.989 ;
     RECT  55.248 17.893 56.712 17.989 ;
     RECT  58.368 17.987 59.208 18.035 ;
     RECT  55.2 17.989 56.712 18.131 ;
     RECT  48.432 17.171 48.456 18.133 ;
     RECT  49.44 17.605 51.312 18.133 ;
     RECT  86.64 17.603 86.664 18.179 ;
     RECT  29.4 17.605 30.696 18.181 ;
     RECT  22.608 17.077 25.08 18.275 ;
     RECT  5.28 17.605 6.024 18.373 ;
     RECT  7.2 17.125 8.112 18.373 ;
     RECT  10.848 17.605 10.872 18.419 ;
     RECT  12.624 17.605 13.512 18.419 ;
     RECT  33.792 17.605 36.168 18.517 ;
     RECT  15.408 18.181 15.432 18.565 ;
     RECT  16.704 17.989 17.352 18.565 ;
     RECT  18.6 17.411 18.912 18.613 ;
     RECT  39.744 17.171 47.304 18.659 ;
     RECT  58.704 18.035 59.208 18.659 ;
     RECT  22.608 18.275 24.312 18.661 ;
     RECT  28.656 18.181 30.696 18.661 ;
     RECT  20.976 17.077 21.144 18.757 ;
     RECT  22.416 18.661 24.312 18.757 ;
     RECT  94.08 17.651 94.728 18.803 ;
     RECT  5.28 18.373 8.112 18.851 ;
     RECT  15.408 18.565 17.352 18.851 ;
     RECT  39.744 18.659 42.648 18.851 ;
     RECT  53.952 15.971 53.976 18.851 ;
     RECT  60.576 17.987 62.112 18.851 ;
     RECT  65.28 16.933 65.304 18.851 ;
     RECT  66.528 17.845 69.864 18.851 ;
     RECT  71.76 17.461 75.24 18.851 ;
     RECT  88.8 17.651 89.784 18.851 ;
     RECT  39.888 18.851 42.648 18.899 ;
     RECT  55.248 18.131 56.712 18.899 ;
     RECT  92.448 17.651 92.472 18.901 ;
     RECT  61.056 18.851 62.112 18.947 ;
     RECT  71.76 18.851 74.808 18.997 ;
     RECT  92.112 18.901 92.472 19.043 ;
     RECT  94.2 18.803 94.728 19.043 ;
     RECT  28.656 18.661 30.792 19.045 ;
     RECT  32.16 17.123 32.328 19.045 ;
     RECT  48.432 18.133 51.312 19.045 ;
     RECT  90.816 18.901 90.84 19.045 ;
     RECT  90.624 19.045 90.84 19.091 ;
     RECT  48.432 19.045 51.432 19.235 ;
     RECT  9.504 17.075 9.528 19.237 ;
     RECT  79.728 17.267 80.808 19.283 ;
     RECT  28.656 19.045 32.328 19.285 ;
     RECT  33.408 18.517 36.168 19.285 ;
     RECT  38.208 17.507 38.232 19.285 ;
     RECT  71.328 18.997 74.808 19.331 ;
     RECT  22.224 18.757 24.312 19.379 ;
     RECT  82.464 16.549 85.176 19.379 ;
     RECT  28.656 19.285 36.168 19.427 ;
     RECT  40.032 18.899 42.648 19.427 ;
     RECT  55.44 18.899 56.712 19.427 ;
     RECT  88.8 18.851 89.496 19.427 ;
     RECT  20.832 18.757 21.144 19.523 ;
     RECT  9.12 19.237 9.528 19.573 ;
     RECT  5.28 18.851 6.024 19.621 ;
     RECT  37.872 19.285 38.232 19.621 ;
     RECT  61.632 18.947 62.112 19.621 ;
     RECT  63.12 16.835 63.72 19.621 ;
     RECT  78 16.979 78.312 19.621 ;
     RECT  28.656 19.427 35.736 19.667 ;
     RECT  71.424 19.331 74.808 19.763 ;
     RECT  79.728 19.283 79.8 19.765 ;
     RECT  26.832 16.453 27.048 19.813 ;
     RECT  48.48 19.235 51.432 19.861 ;
     RECT  99.456 16.019 99.912 19.861 ;
     RECT  26.784 19.813 27.048 19.909 ;
     RECT  79.68 19.765 79.8 19.955 ;
     RECT  37.872 19.621 38.76 20.003 ;
     RECT  43.68 18.659 47.304 20.003 ;
     RECT  82.56 19.379 85.176 20.005 ;
     RECT  61.632 19.621 63.72 20.101 ;
     RECT  90.624 19.091 90.648 20.101 ;
     RECT  7.2 18.851 8.112 20.149 ;
     RECT  13.056 18.419 13.512 20.149 ;
     RECT  22.416 19.379 24.312 20.195 ;
     RECT  28.656 19.667 30.264 20.197 ;
     RECT  77.904 19.621 78.312 20.339 ;
     RECT  12 19.765 12.024 20.341 ;
     RECT  13.056 20.149 13.752 20.341 ;
     RECT  22.416 20.195 22.488 20.341 ;
     RECT  9.12 19.573 10.44 20.389 ;
     RECT  12 20.341 13.752 20.435 ;
     RECT  82.56 20.005 85.32 20.437 ;
     RECT  71.424 19.763 71.448 20.483 ;
     RECT  26.784 19.909 27.48 20.485 ;
     RECT  28.512 20.197 30.264 20.485 ;
     RECT  72.6 19.763 74.808 20.533 ;
     RECT  90.624 20.101 90.744 20.533 ;
     RECT  26.784 20.485 30.264 20.579 ;
     RECT  79.728 19.955 79.8 20.579 ;
     RECT  99.456 19.861 100.344 20.579 ;
     RECT  95.712 17.651 95.736 20.581 ;
     RECT  79.728 20.579 79.752 20.723 ;
     RECT  80.784 19.283 80.808 20.725 ;
     RECT  82.464 20.437 85.32 20.725 ;
     RECT  18.384 18.613 18.912 20.773 ;
     RECT  40.032 19.427 42.456 20.773 ;
     RECT  22.368 20.341 22.488 20.819 ;
     RECT  26.832 20.579 30.264 20.915 ;
     RECT  61.008 20.101 63.72 21.059 ;
     RECT  48.48 19.861 52.152 21.107 ;
     RECT  80.784 20.725 85.32 21.107 ;
     RECT  95.712 20.581 96.456 21.107 ;
     RECT  58.8 18.659 59.208 21.157 ;
     RECT  28.656 20.915 30.264 21.203 ;
     RECT  31.248 19.667 35.736 21.205 ;
     RECT  29.4 21.203 30.264 21.395 ;
     RECT  95.712 21.107 95.736 21.395 ;
     RECT  43.68 20.003 46.488 21.443 ;
     RECT  12 20.435 13.656 21.539 ;
     RECT  88.8 19.427 89.448 21.541 ;
     RECT  5.136 19.621 6.024 21.637 ;
     RECT  26.832 20.915 27.48 21.637 ;
     RECT  9.12 20.389 10.488 21.683 ;
     RECT  66.528 18.851 67.512 21.683 ;
     RECT  92.448 19.043 92.472 21.683 ;
     RECT  12 21.539 13.512 21.731 ;
     RECT  72.6 20.533 74.952 21.731 ;
     RECT  23.472 20.195 24.312 21.829 ;
     RECT  49.344 21.107 52.152 21.875 ;
     RECT  2.4 13.091 2.712 21.877 ;
     RECT  26.208 21.637 27.48 21.923 ;
     RECT  85.2 21.107 85.272 21.923 ;
     RECT  39.984 20.773 42.456 21.971 ;
     RECT  15.504 18.851 17.352 21.973 ;
     RECT  78 20.339 78.312 21.973 ;
     RECT  15.408 21.973 17.352 22.019 ;
     RECT  16.512 22.019 17.352 22.021 ;
     RECT  18.384 20.773 19.56 22.021 ;
     RECT  16.512 22.021 19.56 22.069 ;
     RECT  20.832 19.523 21.096 22.069 ;
     RECT  80.784 21.107 84.216 22.165 ;
     RECT  85.2 21.923 85.224 22.165 ;
     RECT  94.2 19.043 94.512 22.165 ;
     RECT  2.4 21.877 3.432 22.213 ;
     RECT  88.8 21.541 89.544 22.259 ;
     RECT  58.56 21.157 59.208 22.307 ;
     RECT  7.056 20.149 8.112 22.309 ;
     RECT  9.12 21.683 9.144 22.309 ;
     RECT  7.056 22.309 9.144 22.355 ;
     RECT  10.32 21.683 10.488 22.355 ;
     RECT  23.472 21.829 24.792 22.453 ;
     RECT  26.208 21.923 26.856 22.453 ;
     RECT  29.4 21.395 29.712 22.453 ;
     RECT  31.248 21.205 35.976 22.453 ;
     RECT  37.872 20.003 37.896 22.453 ;
     RECT  23.472 22.453 26.856 22.499 ;
     RECT  28.992 22.453 29.712 22.595 ;
     RECT  22.464 20.819 22.488 22.741 ;
     RECT  49.344 21.875 51.72 22.741 ;
     RECT  90.624 20.533 90.936 22.741 ;
     RECT  98.016 16.883 98.04 22.741 ;
     RECT  5.088 21.637 6.024 22.787 ;
     RECT  97.728 22.741 98.04 22.787 ;
     RECT  7.2 22.355 9.144 22.789 ;
     RECT  59.088 22.307 59.208 22.789 ;
     RECT  72.6 21.731 74.808 22.789 ;
     RECT  7.2 22.789 9.288 22.835 ;
     RECT  16.512 22.069 21.096 22.835 ;
     RECT  72.384 22.789 74.808 22.835 ;
     RECT  10.368 22.355 10.488 22.837 ;
     RECT  97.728 22.787 97.752 22.837 ;
     RECT  68.88 18.851 69.864 22.885 ;
     RECT  31.248 22.453 36.456 22.933 ;
     RECT  77.52 21.973 78.312 22.979 ;
     RECT  37.728 22.453 37.896 22.981 ;
     RECT  80.784 22.165 85.224 23.027 ;
     RECT  43.68 21.443 46.152 23.077 ;
     RECT  57.888 22.981 57.912 23.123 ;
     RECT  59.088 22.789 59.448 23.315 ;
     RECT  40.08 21.971 42.456 23.363 ;
     RECT  5.28 22.787 6.024 23.411 ;
     RECT  30.72 22.933 36.456 23.459 ;
     RECT  61.632 21.059 63.72 23.459 ;
     RECT  2.4 22.213 3.912 23.555 ;
     RECT  20.832 22.835 21.096 23.555 ;
     RECT  47.712 22.357 47.736 23.603 ;
     RECT  29.4 22.595 29.712 23.653 ;
     RECT  30.72 23.459 32.616 23.699 ;
     RECT  22.128 22.741 22.488 23.701 ;
     RECT  23.472 22.499 25.656 23.701 ;
     RECT  49.296 22.741 51.72 23.701 ;
     RECT  55.584 19.427 56.712 23.701 ;
     RECT  22.128 23.701 25.656 23.747 ;
     RECT  29.184 23.653 29.712 23.797 ;
     RECT  12.192 21.731 13.512 23.845 ;
     RECT  43.68 23.077 46.68 23.845 ;
     RECT  7.2 22.835 8.232 23.893 ;
     RECT  81.744 23.027 85.224 23.893 ;
     RECT  88.8 22.259 89.112 23.941 ;
     RECT  33.792 23.459 36.456 23.987 ;
     RECT  72.384 22.835 74.424 23.987 ;
     RECT  43.68 23.845 46.728 24.085 ;
     RECT  87.936 23.941 89.112 24.085 ;
     RECT  90.624 22.741 91.8 24.085 ;
     RECT  22.464 23.747 25.656 24.131 ;
     RECT  26.832 22.499 26.856 24.131 ;
     RECT  21.072 23.555 21.096 24.133 ;
     RECT  49.296 23.701 51.768 24.181 ;
     RECT  43.68 24.085 47.256 24.227 ;
     RECT  23.904 24.131 25.656 24.325 ;
     RECT  23.904 24.325 26.232 24.371 ;
     RECT  43.68 24.227 46.68 24.467 ;
     RECT  2.4 23.555 3.672 24.469 ;
     RECT  5.28 23.411 5.832 24.469 ;
     RECT  6.864 23.893 8.232 24.469 ;
     RECT  15.408 22.019 15.528 24.469 ;
     RECT  33.792 23.987 35.352 24.469 ;
     RECT  80.736 23.893 80.76 24.469 ;
     RECT  81.744 23.893 85.896 24.469 ;
     RECT  87.936 24.085 91.8 24.515 ;
     RECT  16.512 22.835 19.56 24.563 ;
     RECT  22.464 24.131 22.872 24.563 ;
     RECT  23.904 24.371 24.792 24.563 ;
     RECT  10.368 22.837 10.584 24.613 ;
     RECT  99.456 20.579 99.912 24.613 ;
     RECT  14.928 24.469 15.528 24.659 ;
     RECT  17.136 24.563 19.56 24.709 ;
     RECT  21.072 24.133 21.432 24.709 ;
     RECT  5.28 24.469 8.232 24.755 ;
     RECT  12.192 23.845 13.944 24.853 ;
     RECT  14.928 24.659 15.096 24.853 ;
     RECT  17.136 24.709 21.432 24.899 ;
     RECT  97.344 22.837 97.752 24.899 ;
     RECT  17.712 24.899 21.432 24.901 ;
     RECT  22.464 24.563 22.488 24.901 ;
     RECT  72.6 23.987 74.424 24.901 ;
     RECT  78 22.979 78.312 24.901 ;
     RECT  31.632 23.699 32.616 25.045 ;
     RECT  33.648 24.469 35.352 25.045 ;
     RECT  87.936 24.515 90.936 25.091 ;
     RECT  31.632 25.045 35.352 25.093 ;
     RECT  26.208 24.371 26.232 25.187 ;
     RECT  68.784 22.885 69.864 25.187 ;
     RECT  99.072 24.613 99.912 25.187 ;
     RECT  2.304 24.469 3.672 25.235 ;
     RECT  31.632 25.093 35.448 25.283 ;
     RECT  80.736 24.469 85.896 25.285 ;
     RECT  68.88 25.187 69.864 25.429 ;
     RECT  80.736 25.285 86.376 25.429 ;
     RECT  87.936 25.091 90.648 25.523 ;
     RECT  5.376 24.755 8.232 25.525 ;
     RECT  9.264 22.835 9.288 25.525 ;
     RECT  12.192 24.853 15.096 25.763 ;
     RECT  17.712 24.901 22.488 25.763 ;
     RECT  40.2 23.363 42.456 25.765 ;
     RECT  77.616 24.901 78.312 25.907 ;
     RECT  94.2 22.165 95.448 25.909 ;
     RECT  88.8 25.523 90.648 25.955 ;
     RECT  10.368 24.613 10.92 25.957 ;
     RECT  18.24 25.763 22.488 26.003 ;
     RECT  13.056 25.763 15.096 26.005 ;
     RECT  28.56 23.797 29.712 26.005 ;
     RECT  43.68 24.467 46.488 26.053 ;
     RECT  48.048 24.805 48.168 26.053 ;
     RECT  37.536 22.981 37.896 26.099 ;
     RECT  61.8 23.459 63.72 26.149 ;
     RECT  10.272 25.957 10.92 26.197 ;
     RECT  49.296 24.181 51.864 26.243 ;
     RECT  75.984 24.469 76.008 26.243 ;
     RECT  79.824 25.429 86.376 26.291 ;
     RECT  90.624 25.955 90.648 26.291 ;
     RECT  40.2 25.765 42.504 26.293 ;
     RECT  36.432 23.987 36.456 26.341 ;
     RECT  37.536 26.099 37.752 26.341 ;
     RECT  72.6 24.901 74.712 26.341 ;
     RECT  43.68 26.053 48.168 26.389 ;
     RECT  5.376 25.525 9.288 26.483 ;
     RECT  99.456 25.187 99.912 26.483 ;
     RECT  83.28 26.291 85.512 26.531 ;
     RECT  54.144 23.893 54.168 26.627 ;
     RECT  79.824 26.291 81.816 26.629 ;
     RECT  18.24 26.003 21.48 26.675 ;
     RECT  38.88 26.533 38.904 26.675 ;
     RECT  83.28 26.531 85.224 26.675 ;
     RECT  28.56 26.005 30.456 26.677 ;
     RECT  40.08 26.293 42.504 26.725 ;
     RECT  61.8 26.149 63.768 26.725 ;
     RECT  53.04 25.573 53.064 26.771 ;
     RECT  13.056 26.005 15.336 26.773 ;
     RECT  22.464 26.003 22.488 26.819 ;
     RECT  31.632 25.283 33.048 26.819 ;
     RECT  59.088 23.315 59.208 26.819 ;
     RECT  72.48 26.341 74.712 26.819 ;
     RECT  93.744 25.909 95.448 26.819 ;
     RECT  39.84 26.725 42.504 26.821 ;
     RECT  43.488 26.389 48.168 26.821 ;
     RECT  55.44 23.701 56.712 26.821 ;
     RECT  5.376 26.483 8.232 26.867 ;
     RECT  61.8 26.725 64.392 26.867 ;
     RECT  9.264 26.483 9.288 26.869 ;
     RECT  10.272 26.197 11.544 26.869 ;
     RECT  12.528 26.773 15.336 26.869 ;
     RECT  9.264 26.869 11.544 26.915 ;
     RECT  72.6 26.819 74.712 26.963 ;
     RECT  9.936 26.915 11.544 27.059 ;
     RECT  64.752 26.917 64.776 27.059 ;
     RECT  83.28 26.675 84.36 27.059 ;
     RECT  5.376 26.867 8.112 27.109 ;
     RECT  36.432 26.341 37.752 27.109 ;
     RECT  97.728 24.899 97.752 27.203 ;
     RECT  24 24.563 24.792 27.205 ;
     RECT  66.672 21.683 67.512 27.205 ;
     RECT  39.84 26.821 48.168 27.251 ;
     RECT  27.936 26.677 30.456 27.301 ;
     RECT  34.416 25.283 35.448 27.301 ;
     RECT  36.432 27.109 37.896 27.301 ;
     RECT  92.016 26.677 92.04 27.301 ;
     RECT  27.936 27.301 30.552 27.395 ;
     RECT  59.184 26.819 59.208 27.395 ;
     RECT  34.416 27.301 37.896 27.397 ;
     RECT  28.56 27.395 30.552 27.443 ;
     RECT  54.48 26.821 56.712 27.587 ;
     RECT  91.824 27.301 92.04 27.587 ;
     RECT  2.4 25.235 3.672 27.635 ;
     RECT  66.432 27.205 67.512 27.683 ;
     RECT  18.6 26.675 21.48 27.685 ;
     RECT  34.416 27.397 38.136 27.779 ;
     RECT  24 27.205 25.032 27.781 ;
     RECT  83.28 27.059 84.216 27.829 ;
     RECT  5.232 27.109 8.112 27.877 ;
     RECT  26.304 27.205 26.328 27.877 ;
     RECT  61.8 26.867 63.768 27.877 ;
     RECT  68.88 25.429 70.392 27.877 ;
     RECT  78 25.907 78.312 27.877 ;
     RECT  79.632 26.629 81.816 27.877 ;
     RECT  48 27.251 48.168 27.971 ;
     RECT  9.936 27.059 10.92 28.261 ;
     RECT  9.936 28.261 11.208 28.405 ;
     RECT  49.296 26.243 49.368 28.405 ;
     RECT  50.496 26.243 51.864 28.405 ;
     RECT  87.456 26.053 87.48 28.405 ;
     RECT  88.8 25.955 89.112 28.405 ;
     RECT  2.4 27.635 2.856 28.451 ;
     RECT  23.376 27.781 25.032 28.453 ;
     RECT  49.296 28.405 51.864 28.453 ;
     RECT  68.88 27.877 70.536 28.453 ;
     RECT  48 27.971 48.072 28.501 ;
     RECT  83.184 27.829 84.216 28.501 ;
     RECT  18.432 27.685 21.48 28.547 ;
     RECT  34.416 27.779 37.896 28.547 ;
     RECT  47.904 28.501 48.072 28.547 ;
     RECT  66.672 27.683 67.512 28.547 ;
     RECT  90.72 27.925 90.744 28.643 ;
     RECT  9.12 28.405 11.208 28.691 ;
     RECT  28.896 27.443 30.552 28.789 ;
     RECT  61.248 27.877 63.768 28.931 ;
     RECT  26.304 27.877 27.144 28.981 ;
     RECT  28.8 28.789 30.552 28.981 ;
     RECT  76.32 27.877 76.344 28.981 ;
     RECT  76.32 28.981 76.776 29.027 ;
     RECT  61.8 28.931 63.768 29.029 ;
     RECT  78 27.877 81.816 29.029 ;
     RECT  83.184 28.501 84.312 29.029 ;
     RECT  9.12 28.691 10.536 29.075 ;
     RECT  54.912 27.587 56.712 29.075 ;
     RECT  3.936 27.877 8.112 29.123 ;
     RECT  26.304 28.981 30.552 29.123 ;
     RECT  96.288 28.117 96.312 29.123 ;
     RECT  78 29.029 84.312 29.171 ;
     RECT  3.936 29.123 6.36 29.267 ;
     RECT  18.432 28.547 21.432 29.267 ;
     RECT  23.328 28.453 25.032 29.269 ;
     RECT  80.832 29.171 84.312 29.315 ;
     RECT  20.832 29.267 21.432 29.509 ;
     RECT  23.328 29.269 25.128 29.509 ;
     RECT  26.304 29.123 29.712 29.509 ;
     RECT  49.296 28.453 52.296 29.603 ;
     RECT  12.528 26.869 15.96 29.651 ;
     RECT  39.84 27.251 46.488 29.651 ;
     RECT  23.328 29.509 29.712 29.699 ;
     RECT  47.904 28.547 48.024 29.699 ;
     RECT  83.184 29.315 84.312 29.699 ;
     RECT  87.456 28.405 89.112 29.699 ;
     RECT  76.752 29.027 76.776 29.795 ;
     RECT  78 29.171 79.752 29.795 ;
     RECT  87.456 29.699 87.48 29.893 ;
     RECT  50.496 29.603 52.296 30.035 ;
     RECT  68.544 28.453 70.536 30.037 ;
     RECT  83.184 29.699 84.216 30.131 ;
     RECT  68.544 30.037 71.064 30.179 ;
     RECT  31.632 26.819 32.616 30.181 ;
     RECT  61.8 29.029 63.816 30.181 ;
     RECT  99.504 26.483 99.912 30.181 ;
     RECT  55.104 29.075 56.712 30.227 ;
     RECT  67.2 28.547 67.512 30.229 ;
     RECT  68.544 30.179 70.584 30.229 ;
     RECT  93.744 26.819 94.512 30.323 ;
     RECT  31.632 30.181 33.48 30.325 ;
     RECT  67.2 30.229 70.584 30.325 ;
     RECT  30.72 30.325 33.48 30.467 ;
     RECT  61.8 30.181 64.632 30.565 ;
     RECT  18.432 29.267 19.56 30.611 ;
     RECT  30.72 30.467 31.272 30.611 ;
     RECT  80.832 29.315 81.816 30.611 ;
     RECT  90.144 29.509 90.168 30.611 ;
     RECT  30.816 30.611 31.272 30.659 ;
     RECT  67.008 30.325 70.584 30.659 ;
     RECT  3.936 29.267 3.96 30.661 ;
     RECT  5.232 29.267 6.36 30.661 ;
     RECT  12.528 29.651 15.432 30.661 ;
     RECT  3.936 30.661 6.36 30.707 ;
     RECT  9.936 29.075 10.536 30.709 ;
     RECT  11.664 30.661 15.432 30.709 ;
     RECT  61.8 30.565 65.592 30.709 ;
     RECT  16.944 25.909 16.968 30.757 ;
     RECT  39.84 29.651 44.568 30.757 ;
     RECT  78 29.795 78.312 30.757 ;
     RECT  34.8 28.547 37.896 30.803 ;
     RECT  18.432 30.611 19.08 30.805 ;
     RECT  23.376 29.699 29.712 30.851 ;
     RECT  32.496 30.467 33.48 30.851 ;
     RECT  60.96 30.709 65.592 30.851 ;
     RECT  67.2 30.659 70.584 30.851 ;
     RECT  88.704 29.699 89.112 30.851 ;
     RECT  39.312 30.757 44.568 30.853 ;
     RECT  7.68 29.123 8.112 30.947 ;
     RECT  55.44 30.227 56.712 30.949 ;
     RECT  9.936 30.709 15.432 30.995 ;
     RECT  39.216 30.853 44.568 30.995 ;
     RECT  91.824 27.587 91.944 30.997 ;
     RECT  12.528 30.995 15.432 31.043 ;
     RECT  48 29.699 48.024 31.045 ;
     RECT  49.296 29.603 49.368 31.045 ;
     RECT  48 31.045 49.368 31.091 ;
     RECT  68.64 30.851 70.584 31.139 ;
     RECT  23.376 30.851 27.144 31.141 ;
     RECT  16.464 30.757 16.968 31.187 ;
     RECT  77.664 30.757 78.312 31.189 ;
     RECT  79.728 29.795 79.752 31.189 ;
     RECT  70.56 31.139 70.584 31.237 ;
     RECT  87.072 29.893 87.48 31.285 ;
     RECT  65.568 30.851 65.592 31.331 ;
     RECT  72.6 26.963 74.52 31.333 ;
     RECT  77.664 31.189 79.752 31.379 ;
     RECT  91.824 30.997 92.136 31.379 ;
     RECT  45.6 29.651 46.488 31.475 ;
     RECT  20.832 29.509 21.48 31.477 ;
     RECT  20.832 31.477 21.672 31.523 ;
     RECT  60.96 30.851 63.72 31.523 ;
     RECT  21.456 31.523 21.672 31.669 ;
     RECT  23.136 31.141 27.144 31.669 ;
     RECT  39.312 30.995 44.568 31.765 ;
     RECT  45.6 31.475 46.344 31.765 ;
     RECT  58.416 31.285 58.44 31.765 ;
     RECT  59.808 30.037 59.832 31.765 ;
     RECT  9.936 30.995 11.448 31.811 ;
     RECT  94.2 30.323 94.512 31.861 ;
     RECT  61.8 31.523 63.72 31.907 ;
     RECT  4.464 30.707 6.36 31.909 ;
     RECT  7.8 30.947 8.112 31.909 ;
     RECT  83.28 30.131 84.216 31.909 ;
     RECT  86.832 31.285 87.48 31.909 ;
     RECT  31.248 30.659 31.272 31.955 ;
     RECT  70.56 31.237 71.448 31.955 ;
     RECT  78 31.379 79.752 31.955 ;
     RECT  92.112 31.379 92.136 31.955 ;
     RECT  16.944 31.187 16.968 32.003 ;
     RECT  12.528 31.043 15.192 32.005 ;
     RECT  55.44 30.949 56.856 32.005 ;
     RECT  71.424 31.955 71.448 32.005 ;
     RECT  72.6 31.333 74.664 32.005 ;
     RECT  4.464 31.909 8.112 32.051 ;
     RECT  71.424 32.005 74.664 32.051 ;
     RECT  74.64 32.051 74.664 32.101 ;
     RECT  55.44 32.005 57 32.147 ;
     RECT  74.64 32.101 75.144 32.195 ;
     RECT  79.728 31.955 79.752 32.243 ;
     RECT  67.2 30.851 67.512 32.293 ;
     RECT  75.12 32.195 75.144 32.339 ;
     RECT  78 31.955 78.648 32.339 ;
     RECT  97.584 29.989 97.608 32.341 ;
     RECT  97.488 32.341 97.608 32.387 ;
     RECT  34.8 30.803 37.368 32.437 ;
     RECT  71.808 32.051 73.32 32.531 ;
     RECT  32.736 30.851 33.48 32.533 ;
     RECT  68.64 31.139 69.528 32.533 ;
     RECT  58.416 31.765 59.832 32.581 ;
     RECT  32.736 32.533 33.624 32.675 ;
     RECT  47.328 31.861 47.352 32.723 ;
     RECT  55.44 32.147 56.808 32.771 ;
     RECT  58.08 32.581 59.832 32.771 ;
     RECT  72.6 32.531 73.32 32.771 ;
     RECT  86.544 31.909 87.48 32.771 ;
     RECT  32.736 32.675 33.48 32.821 ;
     RECT  12.432 32.005 15.192 32.867 ;
     RECT  58.08 32.771 58.44 33.011 ;
     RECT  32.64 32.821 33.48 33.013 ;
     RECT  61.8 31.907 62.376 33.013 ;
     RECT  63.696 31.907 63.72 33.013 ;
     RECT  21.456 31.669 27.144 33.107 ;
     RECT  34.8 32.437 38.184 33.107 ;
     RECT  97.488 32.387 97.512 33.107 ;
     RECT  39.312 31.765 46.344 33.155 ;
     RECT  68.64 32.533 69.864 33.251 ;
     RECT  83.28 31.909 84.264 33.251 ;
     RECT  4.464 32.051 6.36 33.299 ;
     RECT  21.456 33.107 25.944 33.299 ;
     RECT  68.64 33.251 68.664 33.299 ;
     RECT  80.832 30.611 80.856 33.299 ;
     RECT  7.8 32.051 8.112 33.349 ;
     RECT  4.512 33.299 6.36 33.395 ;
     RECT  28.8 30.851 29.712 33.445 ;
     RECT  40.2 33.155 46.344 33.539 ;
     RECT  98.832 30.181 99.912 33.589 ;
     RECT  20.208 32.437 20.232 33.635 ;
     RECT  18.336 30.805 19.08 33.683 ;
     RECT  58.08 33.011 58.104 33.683 ;
     RECT  67.2 32.293 67.608 33.683 ;
     RECT  69.84 33.251 69.864 33.683 ;
     RECT  61.8 33.013 63.72 33.731 ;
     RECT  4.512 33.395 5.256 33.827 ;
     RECT  6.336 33.395 6.36 33.827 ;
     RECT  9.936 31.811 10.632 33.827 ;
     RECT  12.432 32.867 15.096 33.827 ;
     RECT  48.48 31.091 49.368 33.827 ;
     RECT  59.808 32.771 59.832 33.827 ;
     RECT  66.096 32.485 66.12 33.827 ;
     RECT  61.8 33.731 62.76 33.971 ;
     RECT  45.6 33.539 46.344 34.165 ;
     RECT  56.256 32.771 56.808 34.165 ;
     RECT  28.704 33.445 29.712 34.213 ;
     RECT  32.448 33.013 33.48 34.213 ;
     RECT  12.768 33.827 15.096 34.259 ;
     RECT  27.072 33.107 27.144 34.309 ;
     RECT  28.704 34.213 29.832 34.309 ;
     RECT  4.512 33.827 4.536 34.355 ;
     RECT  27.072 34.309 29.832 34.355 ;
     RECT  45.6 34.165 46.968 34.403 ;
     RECT  27.12 34.355 29.832 34.451 ;
     RECT  28.176 34.451 29.832 34.453 ;
     RECT  28.176 34.453 29.928 34.499 ;
     RECT  38.16 33.107 38.184 34.643 ;
     RECT  18.336 33.683 19.032 34.645 ;
     RECT  18.24 34.645 19.032 34.691 ;
     RECT  32.352 34.213 33.48 34.741 ;
     RECT  40.2 33.539 44.568 34.741 ;
     RECT  31.584 34.741 33.48 34.787 ;
     RECT  28.176 34.499 28.2 34.835 ;
     RECT  27.12 34.451 27.144 34.883 ;
     RECT  23.136 33.299 25.944 34.931 ;
     RECT  55.44 34.165 56.808 35.027 ;
     RECT  34.8 33.107 37.032 35.125 ;
     RECT  39.552 34.741 44.568 35.125 ;
     RECT  45.6 34.403 45.912 35.125 ;
     RECT  12.768 34.259 14.712 35.171 ;
     RECT  34.704 35.125 37.032 35.315 ;
     RECT  39.552 35.125 45.912 35.315 ;
     RECT  10.272 33.827 10.632 35.317 ;
     RECT  29.4 34.499 29.928 35.363 ;
     RECT  39.552 35.315 44.568 35.363 ;
     RECT  46.944 34.403 46.968 35.363 ;
     RECT  86.832 32.771 87.48 35.363 ;
     RECT  98.784 33.589 99.912 35.363 ;
     RECT  86.832 35.363 86.856 35.459 ;
     RECT  34.8 35.315 37.032 35.507 ;
     RECT  18.24 34.691 18.912 35.555 ;
     RECT  10.272 35.317 10.776 35.701 ;
     RECT  49.344 33.827 49.368 35.701 ;
     RECT  21.456 33.299 21.48 35.747 ;
     RECT  49.152 35.701 49.368 35.747 ;
     RECT  55.584 35.027 56.808 35.795 ;
     RECT  94.2 31.861 95.208 35.845 ;
     RECT  23.52 34.931 25.944 35.939 ;
     RECT  56.256 35.795 56.808 35.939 ;
     RECT  10.272 35.701 10.92 35.941 ;
     RECT  29.4 35.363 29.712 35.941 ;
     RECT  7.8 33.349 8.472 35.987 ;
     RECT  50.496 30.035 51.864 36.035 ;
     RECT  12.768 35.171 14.28 36.037 ;
     RECT  40.08 35.363 44.568 36.275 ;
     RECT  23.76 35.939 25.944 36.323 ;
     RECT  10.272 35.941 11.256 36.421 ;
     RECT  54.048 35.509 54.072 36.467 ;
     RECT  12.72 36.037 14.28 36.515 ;
     RECT  32.64 34.787 33.48 36.515 ;
     RECT  50.832 36.035 51.576 36.515 ;
     RECT  56.256 35.939 56.712 36.515 ;
     RECT  83.28 33.251 84.216 36.515 ;
     RECT  28.512 35.941 29.712 36.517 ;
     RECT  45.6 35.315 45.912 36.517 ;
     RECT  47.328 36.037 47.352 36.803 ;
     RECT  37.008 35.507 37.032 36.805 ;
     RECT  12.72 36.515 13.608 36.851 ;
     RECT  23.76 36.323 25.752 36.901 ;
     RECT  38.16 36.421 38.184 36.901 ;
     RECT  31.584 34.787 31.608 36.997 ;
     RECT  32.64 36.515 33.048 36.997 ;
     RECT  50.832 36.515 51.432 36.997 ;
     RECT  9.84 36.421 11.256 37.091 ;
     RECT  18.48 35.555 18.912 37.091 ;
     RECT  28.512 36.517 30.456 37.093 ;
     RECT  31.584 36.997 33.048 37.093 ;
     RECT  15.456 36.373 15.48 37.139 ;
     RECT  28.512 37.093 33.048 37.139 ;
     RECT  7.8 35.987 8.112 37.141 ;
     RECT  41.952 36.275 44.568 37.235 ;
     RECT  21.792 36.085 21.816 37.283 ;
     RECT  23.376 36.901 25.752 37.331 ;
     RECT  23.376 37.331 25.032 37.379 ;
     RECT  28.512 37.139 32.664 37.427 ;
     RECT  12.72 36.851 13.512 37.429 ;
     RECT  28.512 37.427 30.456 37.571 ;
     RECT  31.872 37.427 32.664 37.571 ;
     RECT  40.08 36.275 40.512 37.573 ;
     RECT  41.952 37.235 41.976 37.573 ;
     RECT  7.8 37.141 8.232 37.715 ;
     RECT  28.512 37.571 29.712 37.859 ;
     RECT  10.752 37.091 11.256 37.907 ;
     RECT  40.08 37.573 41.976 37.907 ;
     RECT  23.376 37.379 24.552 37.955 ;
     RECT  94.2 35.845 95.448 38.149 ;
     RECT  96.864 36.997 96.888 38.195 ;
     RECT  50.736 36.997 51.432 38.243 ;
     RECT  50.736 38.243 51.312 38.291 ;
     RECT  16.512 37.381 16.536 38.435 ;
     RECT  31.872 37.571 31.896 38.435 ;
     RECT  45.6 36.517 46.008 38.435 ;
     RECT  38.16 36.901 38.808 38.675 ;
     RECT  36.912 36.805 37.032 38.725 ;
     RECT  38.16 38.675 38.184 38.725 ;
     RECT  40.2 37.907 41.976 38.725 ;
     RECT  43.104 37.235 44.568 38.725 ;
     RECT  12.432 37.429 13.512 38.771 ;
     RECT  24 37.955 24.552 38.771 ;
     RECT  36.912 38.725 38.184 38.771 ;
     RECT  49.152 35.747 49.176 38.819 ;
     RECT  21.024 38.149 21.048 39.011 ;
     RECT  34.8 35.507 35.736 39.253 ;
     RECT  36.912 38.771 37.656 39.253 ;
     RECT  34.8 39.253 37.656 39.395 ;
     RECT  36.144 39.395 37.656 39.539 ;
     RECT  26.832 37.381 26.856 39.587 ;
     RECT  40.2 38.725 44.568 39.635 ;
     RECT  36.144 39.539 37.032 39.683 ;
     RECT  40.2 39.635 40.512 39.829 ;
     RECT  36.144 39.683 36.888 40.067 ;
     RECT  39.312 39.829 40.512 40.355 ;
     RECT  43.104 39.635 44.568 40.693 ;
     RECT  43.056 40.693 44.568 42.467 ;
     RECT  43.056 42.467 43.704 42.661 ;
     RECT  43.008 42.661 43.704 42.755 ;
     RECT  43.008 42.755 43.128 42.803 ;
     RECT  94.2 38.149 95.544 42.853 ;
     RECT  36.864 40.067 36.888 43.955 ;
     RECT  43.056 42.803 43.128 44.003 ;
     RECT  94.2 42.853 95.736 44.339 ;
     RECT  34.8 39.395 35.112 44.341 ;
     RECT  38.448 40.357 38.472 44.387 ;
     RECT  95.712 44.339 95.736 45.683 ;
     RECT  10.752 37.907 10.776 46.307 ;
     RECT  96.816 44.293 96.84 46.741 ;
     RECT  98.064 41.557 98.088 46.741 ;
     RECT  43.104 44.003 43.128 47.075 ;
     RECT  96.816 46.741 98.088 47.219 ;
     RECT  83.28 36.515 84.024 47.363 ;
     RECT  33.984 44.341 35.112 47.845 ;
     RECT  83.4 47.363 84.024 48.179 ;
     RECT  41.952 39.635 41.976 48.419 ;
     RECT  2.4 28.451 2.712 49.477 ;
     RECT  33.936 47.845 35.112 49.523 ;
     RECT  96.816 47.219 97.368 50.147 ;
     RECT  95.712 50.101 95.736 51.347 ;
     RECT  96.816 50.147 96.84 52.981 ;
     RECT  96.816 52.981 97.416 55.813 ;
     RECT  96.816 55.813 97.464 61.043 ;
     RECT  43.056 62.581 43.08 62.723 ;
     RECT  2.4 49.477 3.384 63.299 ;
     RECT  99.6 35.363 99.912 64.357 ;
     RECT  97.44 61.043 97.464 65.605 ;
     RECT  96.912 65.605 97.464 65.651 ;
     RECT  98.88 64.357 99.912 65.795 ;
     RECT  96.912 65.651 96.936 66.899 ;
     RECT  95.712 66.853 95.736 67.859 ;
     RECT  99.072 65.795 99.912 68.435 ;
     RECT  2.4 63.299 2.712 69.129 ;
     RECT  7.8 37.715 8.112 69.129 ;
     RECT  13.2 38.771 13.512 69.129 ;
     RECT  18.6 37.091 18.912 69.129 ;
     RECT  24 38.771 24.312 69.129 ;
     RECT  29.4 37.859 29.712 69.129 ;
     RECT  34.8 49.523 35.112 69.129 ;
     RECT  40.2 40.355 40.512 69.129 ;
     RECT  45.6 38.435 45.912 69.129 ;
     RECT  51 38.291 51.312 69.129 ;
     RECT  56.4 36.515 56.712 69.129 ;
     RECT  61.8 33.971 62.112 69.129 ;
     RECT  67.2 33.683 67.512 69.129 ;
     RECT  72.6 32.771 72.912 69.129 ;
     RECT  78 32.339 78.312 69.129 ;
     RECT  83.4 48.179 83.712 69.129 ;
     RECT  88.8 30.851 89.112 69.129 ;
     RECT  94.2 44.339 94.512 69.129 ;
     RECT  99.6 68.435 99.912 69.129 ;
     RECT  2.4 69.129 2.52 69.143 ;
     RECT  7.8 69.129 7.92 69.143 ;
     RECT  13.2 69.129 13.32 69.143 ;
     RECT  18.6 69.129 18.72 69.143 ;
     RECT  24 69.129 24.12 69.143 ;
     RECT  29.4 69.129 29.52 69.143 ;
     RECT  34.8 69.129 34.92 69.143 ;
     RECT  40.2 69.129 40.32 69.143 ;
     RECT  83.4 69.129 83.52 69.143 ;
     RECT  88.8 69.129 88.92 69.143 ;
     RECT  94.2 69.129 94.32 69.143 ;
     RECT  99.6 69.129 99.72 69.143 ;
  END
END ot_hgi_coll_fj_n2s1_r128
END LIBRARY
